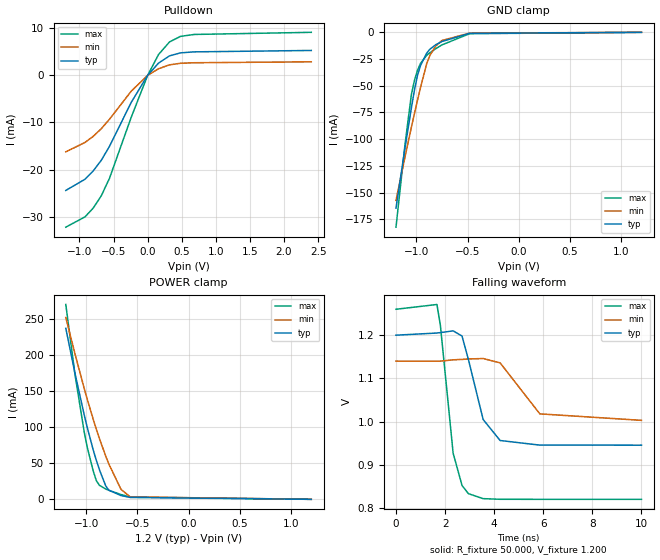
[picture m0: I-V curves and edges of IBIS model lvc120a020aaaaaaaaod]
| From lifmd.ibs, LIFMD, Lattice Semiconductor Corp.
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|   Model lvc120a020aaaaaaaaod
[Model] lvc120a020aaaaaaaaod
Model_type I/O_open_drain
Polarity   Non-Inverting
Enable   Active-Low
Vinl =  0.420V
Vinh =  0.780V
Vmeas =  0.600V
Cref =  0.0F
Rref =  10.000k
Vref =  1.20V
C_comp   5.000pF   4.000pF   5.500pF
[Temperature Range]   25.000   0.125k   -40.000
[Voltage Range]   1.200V   1.140V   1.260V
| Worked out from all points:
|   slope of the pulldown table from 0 to 0.18 V, typ, clamps not added: 63.3 ohm
|   GND clamp passes 1 mA (typ) near -0.48 V on its own axis
|   POWER clamp passes 1 mA (typ) near -0.49 V on its own axis
|   falling waveform, R_fixture 50.000, V_fixture 1.200: 20-80 % time 688ps typ, 991ps min, 500ps max; typ from 1.2 V to 0.946 V
[Pulldown]
|Voltage   I(typ)   I(min)   I(max)
-1.2V     -24.43mA   -16.24mA   -32.23mA
-920mV    -22.07mA   -14.25mA   -30.06mA
-800mV    -20.33mA   -12.97mA   -28.22mA
-680mV    -18.04mA   -11.33mA   -25.58mA
-560mV    -15.08mA   -9.331mA   -21.88mA
-240mV    -5.719mA   -3.347mA   -8.876mA
0V        -2.383fA   10.6fA     -4.549fA
160mV     2.605mA    1.409mA    4.427mA
320mV     4.133mA    2.229mA    7.092mA
480mV     4.774mA    2.565mA    8.275mA
680mV     4.991mA    2.68mA     8.687mA
2.4V      5.291mA    2.878mA    9.14mA
[GND_clamp]
|Voltage   I(typ)   I(min)   I(max)
-1.2V     -164.5mA   -157.3mA   -182.3mA
-1.11V    -107mA     -115.7mA   -103.5mA
-1.05V    -71.11mA   -89.05mA   -58.53mA
-1.02V    -54.23mA   -76.19mA   -45.11mA
-990mV    -40.37mA   -63.68mA   -35.65mA
-960mV    -31.12mA   -51.57mA   -29.01mA
-900mV    -19.51mA   -29.36mA   -21.51mA
-870mV    -15.95mA   -21.89mA   -19.19mA
-810mV    -11.49mA   -12.65mA   -15.26mA
-750mV    -8.556mA   -7.618mA   -11.71mA
-480mV    -930.3uA   -744.4uA   -1.274mA
1.2V      0A         0A         0A
[POWER_clamp]
|Voltage   I(typ)   I(min)   I(max)
-1.2V     237mA      251.9mA    270mA
-1.11V    174.5mA    201.4mA    172.7mA
-1.02V    117mA      153.7mA    93.32mA
-990mV    99.45mA    138.6mA    72.01mA
-930mV    67.46mA    109.9mA    38.25mA
-900mV    53.33mA    96.45mA    25.43mA
-870mV    40.57mA    83.67mA    19.3mA
-810mV    18.72mA    59.99mA    14.34mA
-780mV    12.67mA    49.18mA    12.59mA
-660mV    5.246mA    13.71mA    6.607mA
-570mV    2.605mA    3.346mA    3.25mA
1.2V      0A         0A         0A
[Ramp]
| variable   typ   min   max
dV/dt_r   0.156/0.663n   82.378m/1.038n   0.264/0.449n
dV/dt_f   0.153/0.704n   82.378m/0.991n   0.264/0.501n
R_load = 50.000
[Falling Waveform]
R_fixture= 50.000
V_fixture= 1.200
V_fixture_min= 1.140
V_fixture_max= 1.260
|time   V(typ)   V(min)   V(max)
0s        1.2V       1.14V      1.26V
1.668ns   1.205V     1.14V      1.271V
1.808ns   1.206V     1.14V      1.223V
2.328ns   1.21V      1.143V     927mV
2.69ns    1.198V     1.144V     852.5mV
2.949ns   1.144V     1.145V     833.5mV
3.55ns    1.005V     1.146V     821.9mV
4.242ns   956.4mV    1.136V     820.4mV
5.86ns    945.7mV    1.018V     820.3mV
10ns      945.6mV    1.003V     820.3mV
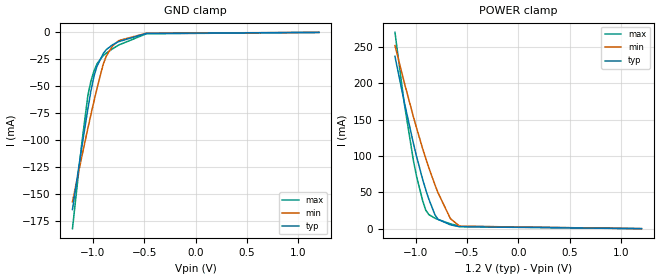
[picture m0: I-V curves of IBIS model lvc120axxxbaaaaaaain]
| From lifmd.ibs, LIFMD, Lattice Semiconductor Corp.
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|   Model lvc120axxxbaaaaaaain
[Model] lvc120axxxbaaaaaaain
Model_type Input
Polarity   Non-Inverting
Vinl =  0.420V
Vinh =  0.780V
C_comp   5.000pF   4.000pF   5.500pF
[Temperature Range]   25.000   0.125k   -40.000
[Voltage Range]   1.200V   1.140V   1.260V
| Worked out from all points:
|   GND clamp passes 1 mA (typ) near -0.48 V on its own axis
|   POWER clamp passes 1 mA (typ) near -0.48 V on its own axis
[GND_clamp]
|Voltage   I(typ)   I(min)   I(max)
-1.2V     -164.5mA   -157.3mA   -182.3mA
-1.11V    -107mA     -115.7mA   -103.5mA
-1.05V    -71.12mA   -89.05mA   -58.53mA
-1.02V    -54.24mA   -76.19mA   -45.12mA
-990mV    -40.38mA   -63.68mA   -35.66mA
-960mV    -31.12mA   -51.57mA   -29.02mA
-900mV    -19.51mA   -29.36mA   -21.52mA
-870mV    -15.95mA   -21.89mA   -19.2mA
-810mV    -11.49mA   -12.65mA   -15.26mA
-750mV    -8.56mA    -7.62mA    -11.71mA
-480mV    -934.9uA   -747.3uA   -1.282mA
1.2V      0A         0A         0A
[POWER_clamp]
|Voltage   I(typ)   I(min)   I(max)
-1.2V     237mA      251.9mA    270mA
-1.11V    174.5mA    201.4mA    172.7mA
-1.02V    117mA      153.7mA    93.33mA
-990mV    99.46mA    138.6mA    72.02mA
-930mV    67.46mA    109.9mA    38.28mA
-900mV    53.34mA    96.46mA    25.46mA
-870mV    40.58mA    83.67mA    19.34mA
-810mV    18.74mA    59.99mA    14.38mA
-780mV    12.68mA    49.19mA    12.62mA
-660mV    5.265mA    13.72mA    6.635mA
-570mV    2.622mA    3.356mA    3.275mA
1.2V      0A         0A         0A
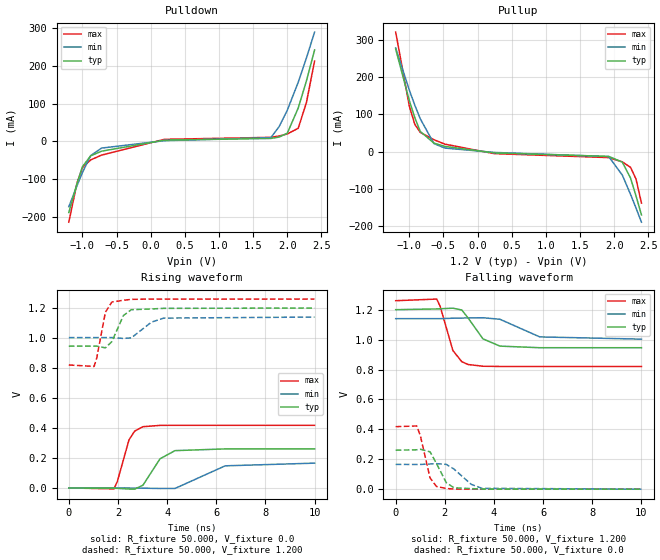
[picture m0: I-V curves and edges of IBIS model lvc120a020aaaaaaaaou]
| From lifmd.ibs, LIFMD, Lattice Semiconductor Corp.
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|   Model lvc120a020aaaaaaaaou
[Model] lvc120a020aaaaaaaaou
Model_type Output
Polarity   Non-Inverting
Vmeas =  0.600V
Cref =  0.0F
Rref =  1.000M
Vref =  0.0V
C_comp   5.000pF   4.000pF   5.500pF
[Temperature Range]   25.000   0.125k   -40.000
[Voltage Range]   1.200V   1.140V   1.260V
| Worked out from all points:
|   slope of the pulldown table from 0 to 0.18 V, typ, clamps not added: 63.3 ohm
|   slope of the pullup table from 0 to 0.18 V, typ, clamps not added: 65.9 ohm
|   rising waveform, R_fixture 50.000, V_fixture 0.0: 20-80 % time 645ps typ, 1.04ns min, 445ps max; typ from 0 V to 0.26 V
|   rising waveform, R_fixture 50.000, V_fixture 1.200: 20-80 % time 413ps typ, 647ps min, 302ps max; typ from 0.946 V to 1.2 V
|   falling waveform, R_fixture 50.000, V_fixture 1.200: 20-80 % time 688ps typ, 991ps min, 500ps max; typ from 1.2 V to 0.946 V
|   falling waveform, R_fixture 50.000, V_fixture 0.0: 20-80 % time 470ps typ, 678ps min, 346ps max; typ from 0.26 V to 0 V
[Pulldown]
|Voltage   I(typ)   I(min)   I(max)
-1.2V     -188.9mA   -173.6mA   -214.6mA
-1.08V    -112.3mA   -117.7mA   -110.6mA
-1V       -67.22mA   -82.71mA   -69.33mA
-880mV    -38.56mA   -37.96mA   -49.45mA
-720mV    -26.17mA   -17.96mA   -36.61mA
200mV     3.083mA    1.667mA    5.25mA
1.76V     7.593mA    9.833mA    10.51mA
1.88V     11.21mA    38.85mA    14.05mA
2V        21.42mA    82.4mA     19.52mA
2.16V     88.15mA    156.5mA    34.54mA
2.28V     159.9mA    220.8mA    102.5mA
2.4V      242.3mA    289.8mA    212.7mA
[Pullup]
|Voltage   I(typ)   I(min)   I(max)
-1.2V     275.5mA    278.5mA    321.2mA
-1V       136.8mA    165.1mA    122mA
-920mV    91.32mA    124.8mA    73.32mA
-840mV    54.36mA    88.32mA    51.77mA
-640mV    22.91mA    21.63mA    32.04mA
-480mV    14.02mA    9.615mA    20.14mA
240mV     -3.395mA   -2.134mA   -5.356mA
1.92V     -12.86mA   -13.28mA   -16.03mA
2.12V     -28.22mA   -63.16mA   -27.54mA
2.24V     -71.02mA   -114.7mA   -42.24mA
2.32V     -118.8mA   -151.5mA   -73.53mA
2.4V      -170.1mA   -189.6mA   -138.1mA
[Ramp]
| variable   typ   min   max
dV/dt_r   0.156/0.663n   99.250m/1.038n   0.251/0.449n
dV/dt_f   0.153/0.704n   82.378m/1.005n   0.264/0.501n
R_load = 50.000
[Rising Waveform]
R_fixture= 50.000
V_fixture= 0.0
V_fixture_min= 0.0
V_fixture_max= 0.0
|time   V(typ)   V(min)   V(max)
0s        0V         0V         0V
1.837ns   -2.233mV   48.45uV    -6.174mV
1.978ns   -2.673mV   133.1uV    44.76mV
2.448ns   -7.473mV   -303.9uV   320.6mV
2.678ns   -8.199mV   -1.148mV   379mV
3.018ns   18.57mV    -1.655mV   408.6mV
3.711ns   194.4mV    -3.758mV   417.3mV
4.321ns   248.9mV    -3.486mV   417.8mV
6.362ns   260.4mV    147.5mV    417.8mV
10ns      260.4mV    165.4mV    417.8mV
[Rising Waveform]
R_fixture= 50.000
V_fixture= 1.200
V_fixture_min= 1.140
V_fixture_max= 1.260
|time   V(typ)   V(min)   V(max)
0s        945.6mV    1.003V     820.3mV
1.028ns   946mV      1.003V     810.6mV
1.137ns   946.3mV    1.003V     867.6mV
1.488ns   934.5mV    1.003V     1.172V
1.751ns   976mV      1.003V     1.24V
2.221ns   1.15V      997.3mV    1.252V
2.541ns   1.189V     1.001V     1.258V
3.362ns   1.194V     1.106V     1.26V
3.862ns   1.198V     1.133V     1.26V
10ns      1.2V       1.14V      1.26V
[Falling Waveform]
R_fixture= 50.000
V_fixture= 1.200
V_fixture_min= 1.140
V_fixture_max= 1.260
|time   V(typ)   V(min)   V(max)
0s        1.2V       1.14V      1.26V
1.668ns   1.205V     1.14V      1.271V
1.808ns   1.206V     1.14V      1.223V
2.328ns   1.21V      1.143V     926.8mV
2.69ns    1.198V     1.144V     852.4mV
2.949ns   1.144V     1.145V     833.4mV
3.55ns    1.005V     1.146V     821.9mV
4.241ns   956.4mV    1.136V     820.4mV
5.86ns    945.7mV    1.018V     820.3mV
10ns      945.6mV    1.003V     820.3mV
[Falling Waveform]
R_fixture= 50.000
V_fixture= 0.0
V_fixture_min= 0.0
V_fixture_max= 0.0
|time   V(typ)   V(min)   V(max)
0s        260.4mV    165.4mV    417.8mV
858ps     263.3mV    165.1mV    422.7mV
1.008ns   266.7mV    165.5mV    354.4mV
1.399ns   249.7mV    168.2mV    75.16mV
1.658ns   172mV      170.6mV    18.11mV
2.061ns   42.79mV    165.4mV    4.147mV
2.37ns    9.655mV    134.8mV    1.251mV
3.071ns   3.631mV    32.44mV    83.11uV
3.51ns    1.247mV    5.804mV    14.76uV
10ns      0V         0V         0V
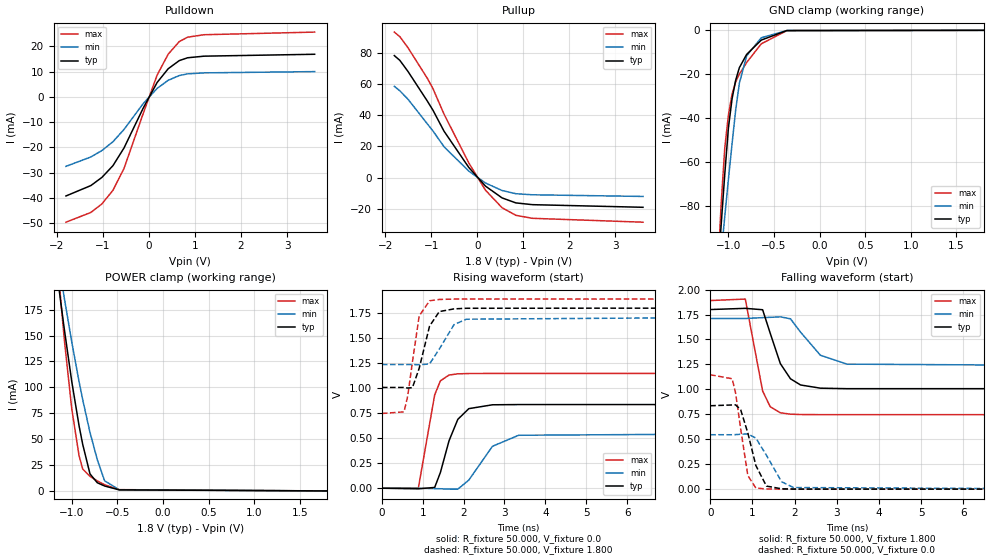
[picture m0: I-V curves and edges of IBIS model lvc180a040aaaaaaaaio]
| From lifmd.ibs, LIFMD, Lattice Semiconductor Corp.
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|   Model lvc180a040aaaaaaaaio
[Model] lvc180a040aaaaaaaaio
Model_type I/O
Polarity   Non-Inverting
Enable   Active-Low
Vinl =  0.630V
Vinh =  1.170V
Vmeas =  0.900V
Cref =  0.0F
Rref =  1.000M
Vref =  0.0V
C_comp   5.000pF   4.000pF   5.500pF
[Temperature Range]   25.000   0.125k   -40.000
[Voltage Range]   1.800V   1.710V   1.890V
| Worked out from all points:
|   slope of the pulldown table from 0 to 0.27 V, typ, clamps not added: 33.9 ohm
|   slope of the pullup table from 0 to 0.27 V, typ, clamps not added: 35.2 ohm
|   GND clamp passes 1 mA (typ) near -0.48 V on its own axis
|   POWER clamp passes 1 mA (typ) near -0.48 V on its own axis
|   rising waveform, R_fixture 50.000, V_fixture 0.0: 20-80 % time 392ps typ, 585ps min, 271ps max; typ from 0 V to 0.836 V
|   rising waveform, R_fixture 50.000, V_fixture 1.800: 20-80 % time 290ps typ, 401ps min, 231ps max; typ from 1.01 V to 1.8 V
|   falling waveform, R_fixture 50.000, V_fixture 1.800: 20-80 % time 412ps typ, 573ps min, 296ps max; typ from 1.8 V to 1.01 V
|   falling waveform, R_fixture 50.000, V_fixture 0.0: 20-80 % time 305ps typ, 420ps min, 231ps max; typ from 0.836 V to 0 V
[Pulldown]
|Voltage   I(typ)   I(min)   I(max)
-1.8V     -39.21mA   -27.5mA    -49.58mA
-1.26V    -35.1mA    -23.79mA   -45.73mA
-1.02V    -31.88mA   -21.25mA   -42.36mA
-780mV    -27.23mA   -17.76mA   -36.96mA
-540mV    -20.24mA   -12.9mA    -28.33mA
-120mV    -4.361mA   -2.624mA   -6.449mA
180mV     5.683mA    3.341mA    8.607mA
420mV     11.11mA    6.532mA    16.87mA
660mV     14.32mA    8.419mA    21.84mA
840mV     15.44mA    9.082mA    23.58mA
1.2V      16.08mA    9.469mA    24.56mA
3.6V      16.83mA    9.972mA    25.6mA
[Pullup]
|Voltage   I(typ)   I(min)   I(max)
-1.8V     78.1mA     58.42mA    93.12mA
-1.68V    75.05mA    55.59mA    90.22mA
-1.5V     67.82mA    50.08mA    83.01mA
-1.08V    48.87mA    34.31mA    63.42mA
-960mV    43.13mA    29.86mA    56.91mA
-720mV    29.72mA    19.78mA    40.63mA
-180mV    6.435mA    4.131mA    9.321mA
180mV     -5.407mA   -3.409mA   -8.023mA
540mV     -12.95mA   -8.221mA   -19.22mA
840mV     -16.14mA   -10.27mA   -24.09mA
1.2V      -17.27mA   -10.95mA   -26mA
3.6V      -18.95mA   -12.01mA   -28.48mA
[GND_clamp]
|Voltage   I(typ)   I(min)   I(max)
-1.8V     -588.7mA   -460.3mA   -776.6mA
-1.12V    -113.2mA   -120.2mA   -111.9mA
-1.08V    -88.74mA   -102.2mA   -79.17mA
-1.04V    -65.4mA    -84.73mA   -53.47mA
-1V       -44.35mA   -67.81mA   -38.46mA
-960mV    -31.12mA   -51.57mA   -29.01mA
-920mV    -22.62mA   -36.09mA   -23.42mA
-880mV    -17mA      -24.08mA   -19.92mA
-800mV    -10.94mA   -11.58mA   -14.64mA
-640mV    -4.44mA    -3.389mA   -6.157mA
-360mV    -108.5uA   -102uA     -131.2uA
1.8V      0A         0A         0A
[POWER_clamp]
|Voltage   I(typ)   I(min)   I(max)
-1.8V     714mA      632.1mA    1.122A
-1.16V    209.1mA    229.4mA    225.8mA
-1.12V    181.6mA    207.1mA    183.6mA
-1.08V    155.1mA    185.3mA    144.6mA
-1V       105.6mA    143.8mA    79.25mA
-920mV    62.93mA    105.5mA    33.98mA
-880mV    44.97mA    88.06mA    21.16mA
-800mV    16.41mA    56.47mA    14.05mA
-720mV    7.909mA    30.12mA    9.679mA
-640mV    4.764mA    9.804mA    6.006mA
-480mV    1.023mA    1.146mA    1.242mA
1.8V      0A         0A         0A
[Ramp]
| variable   typ   min   max
dV/dt_r   0.502/0.398n   0.327/0.588n   0.688/0.275n
dV/dt_f   0.476/0.412n   0.285/0.578n   0.686/0.301n
R_load = 50.000
[Rising Waveform]
R_fixture= 50.000
V_fixture= 0.0
V_fixture_min= 0.0
V_fixture_max= 0.0
|time   V(typ)   V(min)   V(max)
0s        0V         0V         0V
893ps     -5.807mV   279.4uV    2.343mV
1.292ns   7.969mV    -3.757mV   932.5mV
1.432ns   157.5mV    -5.28mV    1.073V
1.643ns   474mV      -9.08mV    1.131V
1.858ns   688.2mV    -9.315mV   1.143V
2.127ns   795.1mV    81.27mV    1.146V
2.706ns   833.7mV    419.2mV    1.147V
3.346ns   835.9mV    529.2mV    1.147V
10ns      835.9mV    545.6mV    1.147V
[Rising Waveform]
R_fixture= 50.000
V_fixture= 1.800
V_fixture_min= 1.710
V_fixture_max= 1.890
|time   V(typ)   V(min)   V(max)
0s        1.007V     1.236V     746.7mV
543ps     1.007V     1.236V     763.1mV
633ps     1.001V     1.236V     922.7mV
748ps     1.005V     1.236V     1.262V
913ps     1.198V     1.233V     1.721V
1.167ns   1.62V      1.242V     1.873V
1.406ns   1.765V     1.391V     1.886V
1.766ns   1.792V     1.635V     1.89V
2.067ns   1.798V     1.689V     1.89V
10ns      1.8V       1.71V      1.89V
[Falling Waveform]
R_fixture= 50.000
V_fixture= 1.800
V_fixture_min= 1.710
V_fixture_max= 1.890
|time   V(typ)   V(min)   V(max)
0s        1.8V       1.71V      1.89V
832ps     1.812V     1.71V      1.905V
1.243ns   1.798V     1.719V     983.2mV
1.423ns   1.562V     1.722V     826.1mV
1.663ns   1.258V     1.727V     765.5mV
1.903ns   1.106V     1.707V     751.6mV
2.143ns   1.044V     1.573V     748mV
2.612ns   1.012V     1.342V     746.8mV
3.242ns   1.007V     1.253V     746.7mV
10ns      1.007V     1.236V     746.7mV
[Falling Waveform]
R_fixture= 50.000
V_fixture= 0.0
V_fixture_min= 0.0
V_fixture_max= 0.0
|time   V(typ)   V(min)   V(max)
0s        835.9mV    545.6mV    1.147V
522ps     843.8mV    545.3mV    1.106V
602ps     844.8mV    546.6mV    964mV
722ps     796.7mV    550.2mV    605.5mV
892ps     563.3mV    553.3mV    136.9mV
1.082ns   237.4mV    512.3mV    11.2mV
1.333ns   30.97mV    339.4mV    1.971mV
1.693ns   3.658mV    74.06mV    196.9uV
1.973ns   1.052mV    16.19mV    32.28uV
10ns      0V         0V         0V
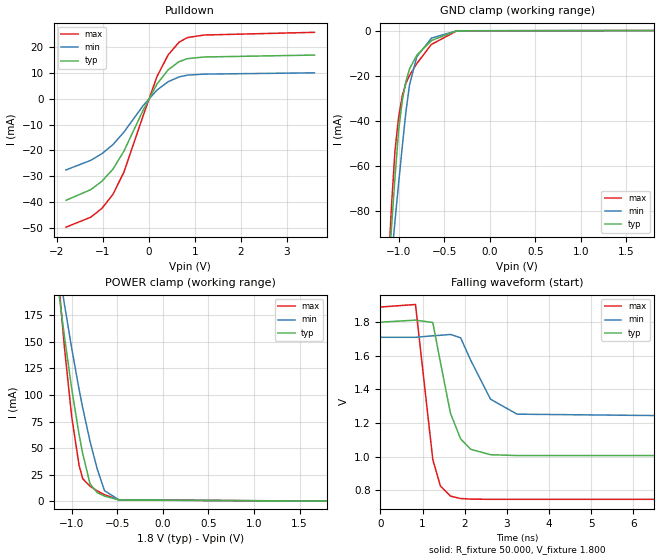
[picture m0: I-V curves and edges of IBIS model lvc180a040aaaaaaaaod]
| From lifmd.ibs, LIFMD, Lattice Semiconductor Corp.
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|   Model lvc180a040aaaaaaaaod
[Model] lvc180a040aaaaaaaaod
Model_type I/O_open_drain
Polarity   Non-Inverting
Enable   Active-Low
Vinl =  0.630V
Vinh =  1.170V
Vmeas =  0.900V
Cref =  0.0F
Rref =  10.000k
Vref =  1.80V
C_comp   5.000pF   4.000pF   5.500pF
[Temperature Range]   25.000   0.125k   -40.000
[Voltage Range]   1.800V   1.710V   1.890V
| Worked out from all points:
|   slope of the pulldown table from 0 to 0.27 V, typ, clamps not added: 33.9 ohm
|   GND clamp passes 1 mA (typ) near -0.48 V on its own axis
|   POWER clamp passes 1 mA (typ) near -0.48 V on its own axis
|   falling waveform, R_fixture 50.000, V_fixture 1.800: 20-80 % time 412ps typ, 573ps min, 296ps max; typ from 1.8 V to 1.01 V
[Pulldown]
|Voltage   I(typ)   I(min)   I(max)
-1.8V     -39.21mA   -27.5mA    -49.58mA
-1.26V    -35.1mA    -23.79mA   -45.73mA
-1.02V    -31.88mA   -21.25mA   -42.36mA
-780mV    -27.23mA   -17.76mA   -36.96mA
-540mV    -20.24mA   -12.9mA    -28.33mA
-120mV    -4.361mA   -2.624mA   -6.449mA
180mV     5.683mA    3.341mA    8.607mA
420mV     11.11mA    6.532mA    16.87mA
660mV     14.32mA    8.419mA    21.84mA
840mV     15.44mA    9.082mA    23.58mA
1.2V      16.08mA    9.469mA    24.56mA
3.6V      16.83mA    9.972mA    25.6mA
[GND_clamp]
|Voltage   I(typ)   I(min)   I(max)
-1.8V     -588.7mA   -460.3mA   -776.6mA
-1.12V    -113.2mA   -120.2mA   -111.9mA
-1.08V    -88.74mA   -102.2mA   -79.17mA
-1.04V    -65.4mA    -84.73mA   -53.47mA
-1V       -44.35mA   -67.81mA   -38.46mA
-960mV    -31.12mA   -51.57mA   -29.01mA
-920mV    -22.62mA   -36.09mA   -23.42mA
-880mV    -17mA      -24.08mA   -19.92mA
-800mV    -10.94mA   -11.58mA   -14.64mA
-640mV    -4.44mA    -3.389mA   -6.157mA
-360mV    -108.5uA   -102uA     -131.2uA
1.8V      0A         0A         0A
[POWER_clamp]
|Voltage   I(typ)   I(min)   I(max)
-1.8V     714mA      632.1mA    1.122A
-1.16V    209.1mA    229.4mA    225.8mA
-1.12V    181.6mA    207.1mA    183.6mA
-1.08V    155.1mA    185.3mA    144.6mA
-1V       105.6mA    143.8mA    79.25mA
-920mV    62.93mA    105.5mA    33.98mA
-880mV    44.97mA    88.06mA    21.16mA
-800mV    16.41mA    56.47mA    14.05mA
-720mV    7.909mA    30.12mA    9.679mA
-640mV    4.764mA    9.804mA    6.006mA
-480mV    1.023mA    1.146mA    1.242mA
1.8V      0A         0A         0A
[Ramp]
| variable   typ   min   max
dV/dt_r   0.476/0.398n   0.285/0.588n   0.688/0.275n
dV/dt_f   0.476/0.412n   0.285/0.578n   0.686/0.301n
R_load = 50.000
[Falling Waveform]
R_fixture= 50.000
V_fixture= 1.800
V_fixture_min= 1.710
V_fixture_max= 1.890
|time   V(typ)   V(min)   V(max)
0s        1.8V       1.71V      1.89V
832ps     1.812V     1.71V      1.905V
1.243ns   1.798V     1.719V     983.2mV
1.423ns   1.562V     1.722V     826.1mV
1.663ns   1.258V     1.727V     765.5mV
1.903ns   1.106V     1.707V     751.6mV
2.143ns   1.044V     1.573V     748mV
2.612ns   1.012V     1.342V     746.8mV
3.242ns   1.007V     1.253V     746.7mV
10ns      1.007V     1.236V     746.7mV
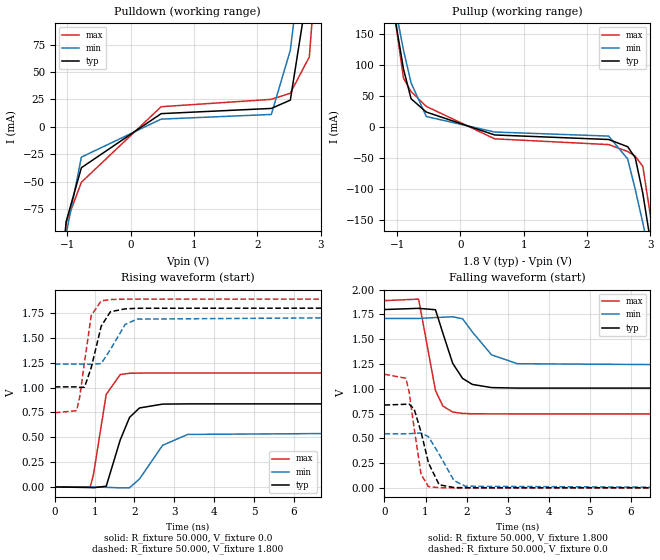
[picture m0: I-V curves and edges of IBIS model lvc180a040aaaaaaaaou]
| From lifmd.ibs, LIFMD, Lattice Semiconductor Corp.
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|   Model lvc180a040aaaaaaaaou
[Model] lvc180a040aaaaaaaaou
Model_type Output
Polarity   Non-Inverting
Vmeas =  0.900V
Cref =  0.0F
Rref =  1.000M
Vref =  0.0V
C_comp   5.000pF   4.000pF   5.500pF
[Temperature Range]   25.000   0.125k   -40.000
[Voltage Range]   1.800V   1.710V   1.890V
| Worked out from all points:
|   slope of the pulldown table from 0 to 0.27 V, typ, clamps not added: 33.9 ohm
|   slope of the pullup table from 0 to 0.27 V, typ, clamps not added: 35.2 ohm
|   rising waveform, R_fixture 50.000, V_fixture 0.0: 20-80 % time 392ps typ, 584ps min, 270ps max; typ from 0 V to 0.836 V
|   rising waveform, R_fixture 50.000, V_fixture 1.800: 20-80 % time 290ps typ, 401ps min, 231ps max; typ from 1.01 V to 1.8 V
|   falling waveform, R_fixture 50.000, V_fixture 1.800: 20-80 % time 412ps typ, 573ps min, 296ps max; typ from 1.8 V to 1.01 V
|   falling waveform, R_fixture 50.000, V_fixture 0.0: 20-80 % time 305ps typ, 420ps min, 231ps max; typ from 0.836 V to 0 V
[Pulldown]
|Voltage   I(typ)   I(min)   I(max)
-1.8V     -627.9mA   -487.8mA   -826.2mA
-1.26V    -239.5mA   -209.8mA   -283.8mA
-1.2V     -198.9mA   -180.5mA   -227.3mA
-1.02V    -86.11mA   -97.45mA   -87.47mA
-780mV    -37.15mA   -27.51mA   -50.4mA
480mV     12.11mA    7.121mA    18.42mA
2.22V     16.85mA    11.38mA    25.12mA
2.52V     24.42mA    69.93mA    30.75mA
2.82V     134mA      211.4mA    63.84mA
3V        254.1mA    314.9mA    198.8mA
3.06V     297.8mA    351.1mA    262.1mA
3.6V      730.9mA    703.4mA    1.007A
[Pullup]
|Voltage   I(typ)   I(min)   I(max)
-1.8V     792.1mA    690.5mA    1.215A
-1.08V    204mA      219.7mA    208.1mA
-900mV    93.44mA    124mA      78.8mA
-780mV    45.47mA    71.17mA    57.09mA
-540mV    24.03mA    16.84mA    33.19mA
540mV     -12.95mA   -8.221mA   -19.22mA
2.34V     -20.28mA   -14.79mA   -28.51mA
2.64V     -31.95mA   -51.63mA   -39.63mA
2.76V     -49.73mA   -100.8mA   -47.2mA
2.88V     -107.4mA   -155.1mA   -63.74mA
3.06V     -223.2mA   -241.8mA   -183.5mA
3.6V      -607.7mA   -519.4mA   -712.9mA
[Ramp]
| variable   typ   min   max
dV/dt_r   0.502/0.398n   0.327/0.588n   0.688/0.278n
dV/dt_f   0.476/0.412n   0.285/0.578n   0.686/0.301n
R_load = 50.000
[Rising Waveform]
R_fixture= 50.000
V_fixture= 0.0
V_fixture_min= 0.0
V_fixture_max= 0.0
|time   V(typ)   V(min)   V(max)
0s        0V         0V         0V
891ps     -5.762mV   273.5uV    956.5uV
971ps     -7.862mV   451.4uV    125.7mV
1.291ns   7.418mV    -3.747mV   931.4mV
1.642ns   472.7mV    -9.061mV   1.131V
1.876ns   700mV      -8.083mV   1.144V
2.126ns   795mV      80.68mV    1.146V
2.706ns   833.7mV    419.2mV    1.147V
3.337ns   835.9mV    528.7mV    1.147V
10ns      835.9mV    545.6mV    1.147V
[Rising Waveform]
R_fixture= 50.000
V_fixture= 1.800
V_fixture_min= 1.710
V_fixture_max= 1.890
|time   V(typ)   V(min)   V(max)
0s        1.007V     1.236V     746.7mV
548ps     1.007V     1.236V     767.7mV
625ps     1.002V     1.236V     902.5mV
746ps     1.004V     1.236V     1.256V
915ps     1.201V     1.233V     1.726V
1.166ns   1.619V     1.242V     1.873V
1.396ns   1.763V     1.383V     1.886V
1.766ns   1.792V     1.635V     1.89V
2.067ns   1.798V     1.689V     1.89V
10ns      1.8V       1.71V      1.89V
[Falling Waveform]
R_fixture= 50.000
V_fixture= 1.800
V_fixture_min= 1.710
V_fixture_max= 1.890
|time   V(typ)   V(min)   V(max)
0s        1.8V       1.71V      1.89V
832ps     1.812V     1.71V      1.905V
1.243ns   1.798V     1.719V     982.7mV
1.423ns   1.562V     1.722V     825.8mV
1.663ns   1.257V     1.727V     765.4mV
1.903ns   1.105V     1.707V     751.4mV
2.143ns   1.044V     1.573V     747.9mV
2.612ns   1.012V     1.342V     746.8mV
3.242ns   1.007V     1.253V     746.7mV
10ns      1.007V     1.236V     746.7mV
[Falling Waveform]
R_fixture= 50.000
V_fixture= 0.0
V_fixture_min= 0.0
V_fixture_max= 0.0
|time   V(typ)   V(min)   V(max)
0s        835.9mV    545.6mV    1.147V
522ps     843.8mV    545.3mV    1.106V
602ps     844.8mV    546.6mV    963.7mV
722ps     796.7mV    550.3mV    604.8mV
892ps     563.1mV    553.3mV    136.3mV
1.073ns   250.9mV    516.2mV    12.12mV
1.333ns   30.95mV    339.4mV    1.97mV
1.693ns   3.657mV    74.05mV    196.5uV
1.973ns   1.052mV    16.18mV    32.23uV
10ns      0V         0V         0V
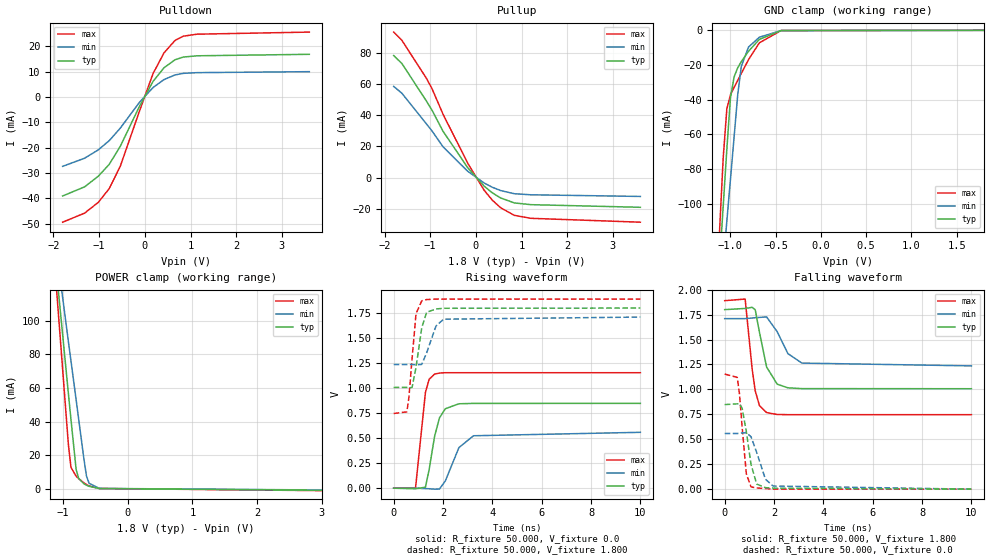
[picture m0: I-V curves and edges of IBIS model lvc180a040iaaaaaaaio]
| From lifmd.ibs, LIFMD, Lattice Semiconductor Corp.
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|   Model lvc180a040iaaaaaaaio
[Model] lvc180a040iaaaaaaaio
Model_type I/O
Polarity   Non-Inverting
Enable   Active-Low
Vinl =  0.630V
Vinh =  1.170V
Vmeas =  0.900V
Cref =  0.0F
Rref =  1.000M
Vref =  0.0V
C_comp   5.000pF   4.000pF   5.500pF
[Temperature Range]   25.000   0.125k   -40.000
[Voltage Range]   1.800V   1.710V   1.890V
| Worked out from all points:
|   slope of the pulldown table from 0 to 0.27 V, typ, clamps not added: 34.2 ohm
|   slope of the pullup table from 0 to 0.27 V, typ, clamps not added: 35.2 ohm
|   GND clamp passes 1 mA (typ) near -0.54 V on its own axis
|   POWER clamp passes 1 mA (typ) near -0.56 V on its own axis
|   rising waveform, R_fixture 50.000, V_fixture 0.0: 20-80 % time 394ps typ, 606ps min, 265ps max; typ from 0 V to 0.848 V
|   rising waveform, R_fixture 50.000, V_fixture 1.800: 20-80 % time 285ps typ, 399ps min, 225ps max; typ from 1.01 V to 1.8 V
|   falling waveform, R_fixture 50.000, V_fixture 1.800: 20-80 % time 419ps typ, 589ps min, 297ps max; typ from 1.8 V to 1.01 V
|   falling waveform, R_fixture 50.000, V_fixture 0.0: 20-80 % time 308ps typ, 433ps min, 231ps max; typ from 0.848 V to 0 V
[Pulldown]
|Voltage   I(typ)   I(min)   I(max)
-1.8V     -39.12mA   -27.42mA   -49.46mA
-1.32V    -35.52mA   -24.22mA   -45.9mA
-1.02V    -31.32mA   -20.92mA   -41.65mA
-780mV    -26.63mA   -17.28mA   -36.21mA
-540mV    -19.59mA   -12.39mA   -27.48mA
-120mV    -3.808mA   -2.191mA   -5.729mA
180mV     6.15mA     3.704mA    9.22mA
420mV     11.5mA     6.838mA    17.4mA
660mV     14.65mA    8.668mA    22.28mA
840mV     15.72mA    9.289mA    23.96mA
1.14V     16.22mA    9.571mA    24.75mA
3.6V      16.81mA    9.957mA    25.58mA
[Pullup]
|Voltage   I(typ)   I(min)   I(max)
-1.8V     78.1mA     58.42mA    93.12mA
-1.62V    73.05mA    53.99mA    87.86mA
-1.08V    48.87mA    34.31mA    63.42mA
-960mV    43.13mA    29.86mA    56.91mA
-720mV    29.72mA    19.78mA    40.63mA
-180mV    6.435mA    4.131mA    9.321mA
180mV     -5.407mA   -3.409mA   -8.023mA
360mV     -9.708mA   -6.144mA   -14.39mA
540mV     -12.95mA   -8.221mA   -19.22mA
840mV     -16.14mA   -10.27mA   -24.09mA
1.2V      -17.27mA   -10.95mA   -26mA
3.6V      -18.95mA   -12.01mA   -28.48mA
[GND_clamp]
|Voltage   I(typ)   I(min)   I(max)
-1.8V     -696.3mA   -577.9mA   -833.3mA
-1.12V    -133.9mA   -158.6mA   -115.3mA
-1.08V    -101.3mA   -134.3mA   -73.45mA
-1.04V    -68.65mA   -110.1mA   -45.28mA
-1V       -38.97mA   -85.9mA    -37.19mA
-960mV    -26.91mA   -61.71mA   -32.92mA
-920mV    -21.64mA   -37.35mA   -28.96mA
-880mV    -18.02mA   -20.78mA   -24.84mA
-800mV    -12.05mA   -9.617mA   -16.87mA
-680mV    -5.205mA   -3.967mA   -7.195mA
-440mV    -125.3uA   -155.5uA   -107.7uA
1.8V      0A         0A         0A
[POWER_clamp]
|Voltage   I(typ)   I(min)   I(max)
-1.8V     417mA      358.2mA    486.8mA
-1.16V    151.7mA    158.7mA    147.8mA
-1.12V    135.7mA    146.8mA    127.3mA
-920mV    56.89mA    87.77mA    26.5mA
-880mV    41.38mA    76.25mA    12.77mA
-800mV    11.56mA    53.05mA    7.539mA
-760mV    6.141mA    41.32mA    6.086mA
-680mV    3.009mA    17.95mA    3.597mA
-640mV    2.17mA     7.684mA    2.581mA
-600mV    1.495mA    3.327mA    1.736mA
-440mV    197.7uA    253.9uA    205.9uA
3.6V      -1.035mA   -849.1uA   -1.289mA
[Ramp]
| variable   typ   min   max
dV/dt_r   0.509/0.398n   0.335/0.606n   0.693/0.270n
dV/dt_f   0.476/0.418n   0.285/0.591n   0.686/0.299n
R_load = 50.000
[Rising Waveform]
R_fixture= 50.000
V_fixture= 0.0
V_fixture_min= 0.0
V_fixture_max= 0.0
|time   V(typ)   V(min)   V(max)
0s        0V         0V         0V
887ps     -5.81mV    301.7uV    3.354mV
1.288ns   10.34mV    -3.84mV    956.6mV
1.437ns   184.5mV    -5.464mV   1.088V
1.658ns   517.2mV    -9.519mV   1.14V
1.856ns   702mV      -8.556mV   1.151V
2.096ns   794.3mV    73.54mV    1.154V
2.646ns   843.7mV    406.2mV    1.154V
3.236ns   847.5mV    524.2mV    1.154V
10ns      847.7mV    558.5mV    1.154V
[Rising Waveform]
R_fixture= 50.000
V_fixture= 1.800
V_fixture_min= 1.710
V_fixture_max= 1.890
|time   V(typ)   V(min)   V(max)
0s        1.007V     1.236V     746.7mV
536ps     1.007V     1.236V     762.6mV
617ps     1.002V     1.236V     904.4mV
748ps     1.008V     1.236V     1.298V
907ps     1.208V     1.233V     1.744V
1.138ns   1.602V     1.237V     1.872V
1.336ns   1.758V     1.352V     1.885V
1.716ns   1.791V     1.621V     1.89V
2.026ns   1.798V     1.689V     1.89V
10ns      1.8V       1.71V      1.89V
[Falling Waveform]
R_fixture= 50.000
V_fixture= 1.800
V_fixture_min= 1.710
V_fixture_max= 1.890
|time   V(typ)   V(min)   V(max)
0s        1.8V       1.71V      1.89V
829ps     1.812V     1.71V      1.906V
1.115ns   1.823V     1.716V     1.2V
1.237ns   1.799V     1.719V     986.2mV
1.408ns   1.574V     1.722V     839.1mV
1.698ns   1.225V     1.727V     767.8mV
2.127ns   1.053V     1.579V     748.8mV
2.561ns   1.016V     1.359V     747mV
3.131ns   1.008V     1.264V     746.7mV
10ns      1.007V     1.236V     746.7mV
[Falling Waveform]
R_fixture= 50.000
V_fixture= 0.0
V_fixture_min= 0.0
V_fixture_max= 0.0
|time   V(typ)   V(min)   V(max)
0s        847.7mV    558.5mV    1.154V
509ps     855.5mV    558.3mV    1.121V
598ps     856.3mV    559.8mV    958.1mV
707ps     812.2mV    563.3mV    624.6mV
877ps     576.8mV    566.6mV    153.6mV
1.067ns   248.3mV    525.6mV    22.68mV
1.297ns   51.01mV    368mV      11.95mV
1.651ns   14.96mV    99.99mV    6.54mV
1.961ns   10.47mV    31.38mV    886.6uV
10ns      0V         0V         0V
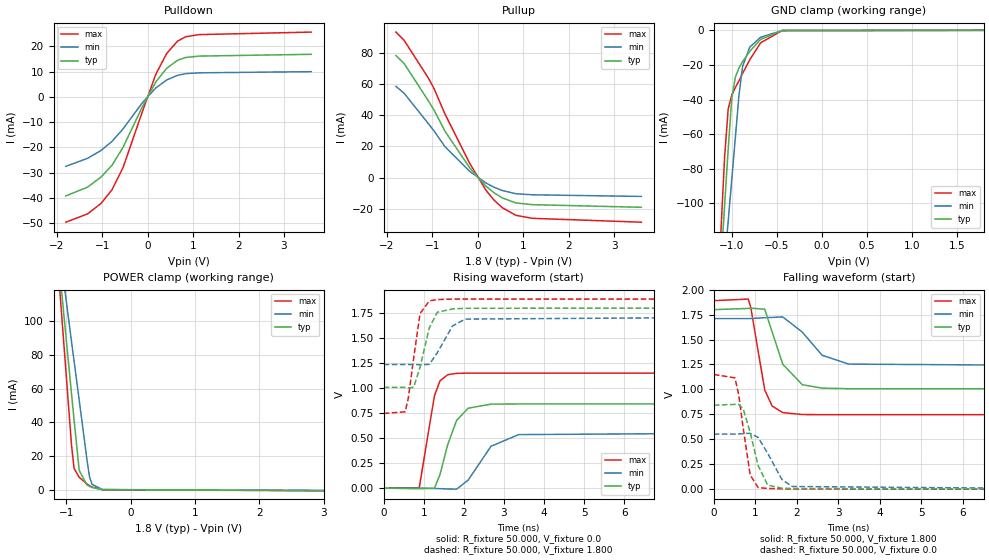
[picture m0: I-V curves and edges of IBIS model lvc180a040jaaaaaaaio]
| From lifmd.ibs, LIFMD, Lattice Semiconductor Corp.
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|   Model lvc180a040jaaaaaaaio
[Model] lvc180a040jaaaaaaaio
Model_type I/O
Polarity   Non-Inverting
Enable   Active-Low
Vinl =  0.630V
Vinh =  1.170V
Vmeas =  0.900V
Cref =  0.0F
Rref =  1.000M
Vref =  0.0V
C_comp   5.000pF   4.000pF   5.500pF
[Temperature Range]   25.000   0.125k   -40.000
[Voltage Range]   1.800V   1.710V   1.890V
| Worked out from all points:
|   slope of the pulldown table from 0 to 0.27 V, typ, clamps not added: 34 ohm
|   slope of the pullup table from 0 to 0.27 V, typ, clamps not added: 35.2 ohm
|   GND clamp passes 1 mA (typ) near -0.54 V on its own axis
|   POWER clamp passes 1 mA (typ) near -0.57 V on its own axis
|   rising waveform, R_fixture 50.000, V_fixture 0.0: 20-80 % time 388ps typ, 591ps min, 263ps max; typ from 0 V to 0.842 V
|   rising waveform, R_fixture 50.000, V_fixture 1.800: 20-80 % time 285ps typ, 399ps min, 225ps max; typ from 1.01 V to 1.8 V
|   falling waveform, R_fixture 50.000, V_fixture 1.800: 20-80 % time 414ps typ, 582ps min, 293ps max; typ from 1.8 V to 1.01 V
|   falling waveform, R_fixture 50.000, V_fixture 0.0: 20-80 % time 302ps typ, 422ps min, 228ps max; typ from 0.842 V to 0 V
[Pulldown]
|Voltage   I(typ)   I(min)   I(max)
-1.8V     -39.16mA   -27.46mA   -49.52mA
-1.32V    -35.66mA   -24.28mA   -46.23mA
-1.02V    -31.61mA   -21.12mA   -42.01mA
-780mV    -26.94mA   -17.53mA   -36.6mA
-540mV    -19.92mA   -12.65mA   -27.92mA
-120mV    -4.086mA   -2.409mA   -6.091mA
180mV     5.915mA    3.521mA    8.911mA
420mV     11.3mA     6.684mA    17.14mA
660mV     14.48mA    8.542mA    22.06mA
840mV     15.58mA    9.185mA    23.77mA
1.14V     16.12mA    9.503mA    24.61mA
3.6V      16.82mA    9.969mA    25.6mA
[Pullup]
|Voltage   I(typ)   I(min)   I(max)
-1.8V     78.1mA     58.42mA    93.12mA
-1.62V    73.05mA    53.99mA    87.86mA
-1.08V    48.87mA    34.31mA    63.42mA
-960mV    43.13mA    29.86mA    56.91mA
-720mV    29.72mA    19.78mA    40.63mA
-180mV    6.435mA    4.131mA    9.321mA
180mV     -5.407mA   -3.409mA   -8.023mA
360mV     -9.708mA   -6.144mA   -14.39mA
540mV     -12.95mA   -8.221mA   -19.22mA
840mV     -16.14mA   -10.27mA   -24.09mA
1.2V      -17.27mA   -10.95mA   -26mA
3.6V      -18.95mA   -12.01mA   -28.48mA
[GND_clamp]
|Voltage   I(typ)   I(min)   I(max)
-1.8V     -696.8mA   -578.3mA   -833.9mA
-1.12V    -134.1mA   -158.8mA   -115.5mA
-1.08V    -101.4mA   -134.5mA   -73.62mA
-1.04V    -68.77mA   -110.2mA   -45.44mA
-1V       -39.08mA   -86.02mA   -37.35mA
-960mV    -27.01mA   -61.81mA   -33.06mA
-920mV    -21.74mA   -37.43mA   -29.09mA
-880mV    -18.1mA    -20.85mA   -24.96mA
-800mV    -12.12mA   -9.665mA   -16.97mA
-680mV    -5.239mA   -3.993mA   -7.242mA
-440mV    -125.9uA   -156.3uA   -108.1uA
1.8V      0A         0A         0A
[POWER_clamp]
|Voltage   I(typ)   I(min)   I(max)
-1.8V     417mA      358.2mA    486.8mA
-1.16V    151.7mA    158.7mA    147.8mA
-1.12V    135.7mA    146.8mA    127.3mA
-1.08V    119.8mA    134.8mA    106.9mA
-920mV    56.85mA    87.76mA    26.37mA
-880mV    41.32mA    76.23mA    12.64mA
-800mV    11.47mA    53.02mA    7.417mA
-680mV    2.92mA     17.91mA    3.486mA
-640mV    2.084mA    7.63mA     2.474mA
-600mV    1.414mA    3.267mA    1.634mA
-440mV    134uA      201.9uA    126.5uA
3.6V      -514.2uA   -421.9uA   -640.6uA
[Ramp]
| variable   typ   min   max
dV/dt_r   0.505/0.392n   0.331/0.593n   0.690/0.265n
dV/dt_f   0.476/0.411n   0.285/0.581n   0.686/0.293n
R_load = 50.000
[Rising Waveform]
R_fixture= 50.000
V_fixture= 0.0
V_fixture_min= 0.0
V_fixture_max= 0.0
|time   V(typ)   V(min)   V(max)
0s        0V         0V         0V
887ps     -5.81mV    301.7uV    3.354mV
1.267ns   -307uV     -3.625mV   924.6mV
1.406ns   138.3mV    -5.068mV   1.073V
1.598ns   435.7mV    -8.414mV   1.134V
1.818ns   676mV      -10.3mV    1.147V
2.108ns   799mV      80.86mV    1.15V
2.678ns   839.7mV    418.6mV    1.15V
3.366ns   841.7mV    535.1mV    1.15V
10ns      841.8mV    552mV      1.15V
[Rising Waveform]
R_fixture= 50.000
V_fixture= 1.800
V_fixture_min= 1.710
V_fixture_max= 1.890
|time   V(typ)   V(min)   V(max)
0s        1.007V     1.236V     746.7mV
536ps     1.007V     1.236V     762.6mV
617ps     1.002V     1.236V     904.4mV
748ps     1.008V     1.236V     1.298V
907ps     1.208V     1.233V     1.744V
1.138ns   1.602V     1.237V     1.872V
1.338ns   1.758V     1.353V     1.885V
1.716ns   1.791V     1.621V     1.89V
2.036ns   1.798V     1.69V      1.89V
10ns      1.8V       1.71V      1.89V
[Falling Waveform]
R_fixture= 50.000
V_fixture= 1.800
V_fixture_min= 1.710
V_fixture_max= 1.890
|time   V(typ)   V(min)   V(max)
0s        1.8V       1.71V      1.89V
829ps     1.812V     1.71V      1.906V
890ps     1.814V     1.711V     1.824V
1.227ns   1.805V     1.719V     994.3mV
1.407ns   1.575V     1.722V     832.9mV
1.662ns   1.252V     1.727V     767.7mV
2.133ns   1.047V     1.574V     748.3mV
2.611ns   1.013V     1.342V     746.9mV
3.251ns   1.007V     1.254V     746.7mV
10ns      1.007V     1.236V     746.7mV
[Falling Waveform]
R_fixture= 50.000
V_fixture= 0.0
V_fixture_min= 0.0
V_fixture_max= 0.0
|time   V(typ)   V(min)   V(max)
0s        841.8mV    552mV      1.15V
509ps     849.7mV    551.8mV    1.116V
598ps     850.5mV    553.3mV    952.4mV
707ps     806.2mV    556.8mV    616.6mV
877ps     569.7mV    560.1mV    142.1mV
1.067ns   238.8mV    519.1mV    16.45mV
1.297ns   41.25mV    360.8mV    7.101mV
1.642ns   9.73mV     95.98mV    3.258mV
1.891ns   6.249mV    26.81mV    713.8uV
10ns      0V         0V         0V
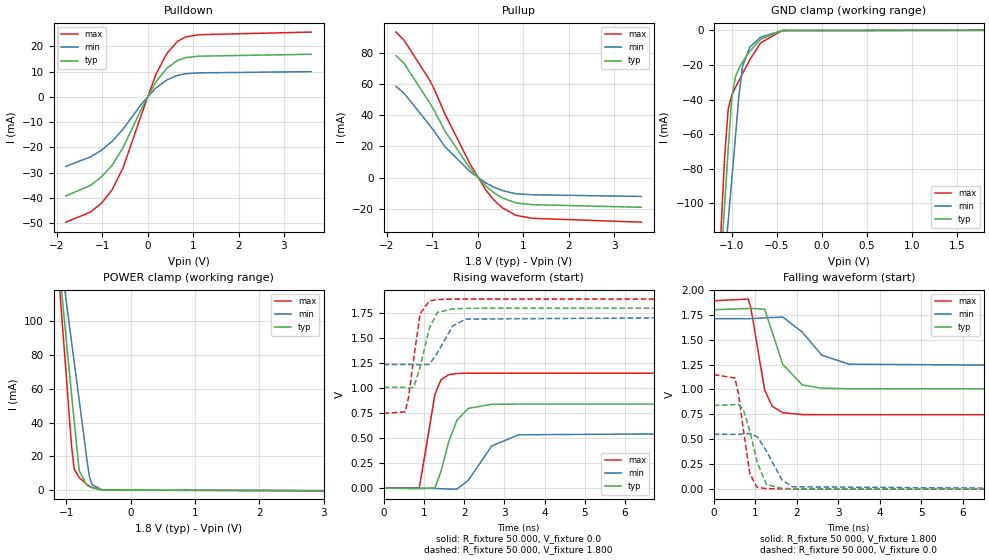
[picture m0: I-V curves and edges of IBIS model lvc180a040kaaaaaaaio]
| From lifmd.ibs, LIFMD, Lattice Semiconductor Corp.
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|   Model lvc180a040kaaaaaaaio
[Model] lvc180a040kaaaaaaaio
Model_type I/O
Polarity   Non-Inverting
Enable   Active-Low
Vinl =  0.630V
Vinh =  1.170V
Vmeas =  0.900V
Cref =  0.0F
Rref =  1.000M
Vref =  0.0V
C_comp   5.000pF   4.000pF   5.500pF
[Temperature Range]   25.000   0.125k   -40.000
[Voltage Range]   1.800V   1.710V   1.890V
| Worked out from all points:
|   slope of the pulldown table from 0 to 0.27 V, typ, clamps not added: 34 ohm
|   slope of the pullup table from 0 to 0.27 V, typ, clamps not added: 35.2 ohm
|   GND clamp passes 1 mA (typ) near -0.54 V on its own axis
|   POWER clamp passes 1 mA (typ) near -0.57 V on its own axis
|   rising waveform, R_fixture 50.000, V_fixture 0.0: 20-80 % time 387ps typ, 586ps min, 263ps max; typ from 0 V to 0.84 V
|   rising waveform, R_fixture 50.000, V_fixture 1.800: 20-80 % time 285ps typ, 399ps min, 225ps max; typ from 1.01 V to 1.8 V
|   falling waveform, R_fixture 50.000, V_fixture 1.800: 20-80 % time 412ps typ, 580ps min, 292ps max; typ from 1.8 V to 1.01 V
|   falling waveform, R_fixture 50.000, V_fixture 0.0: 20-80 % time 300ps typ, 419ps min, 227ps max; typ from 0.84 V to 0 V
[Pulldown]
|Voltage   I(typ)   I(min)   I(max)
-1.8V     -39.18mA   -27.47mA   -49.54mA
-1.26V    -35.03mA   -23.76mA   -45.57mA
-1.02V    -31.7mA    -21.17mA   -42.12mA
-780mV    -27.03mA   -17.6mA    -36.72mA
-540mV    -20.03mA   -12.73mA   -28.05mA
-120mV    -4.173mA   -2.476mA   -6.206mA
180mV     5.841mA    3.465mA    8.814mA
420mV     11.24mA    6.637mA    17.05mA
660mV     14.43mA    8.504mA    21.99mA
840mV     15.54mA    9.153mA    23.71mA
1.14V     16.09mA    9.482mA    24.57mA
3.6V      16.83mA    9.971mA    25.6mA
[Pullup]
|Voltage   I(typ)   I(min)   I(max)
-1.8V     78.1mA     58.42mA    93.12mA
-1.62V    73.05mA    53.99mA    87.86mA
-1.08V    48.87mA    34.31mA    63.42mA
-960mV    43.13mA    29.86mA    56.91mA
-720mV    29.72mA    19.78mA    40.63mA
-180mV    6.435mA    4.131mA    9.321mA
180mV     -5.407mA   -3.409mA   -8.023mA
360mV     -9.708mA   -6.144mA   -14.39mA
540mV     -12.95mA   -8.221mA   -19.22mA
840mV     -16.14mA   -10.27mA   -24.09mA
1.2V      -17.27mA   -10.95mA   -26mA
3.6V      -18.95mA   -12.01mA   -28.48mA
[GND_clamp]
|Voltage   I(typ)   I(min)   I(max)
-1.8V     -697mA     -578.4mA   -834.1mA
-1.12V    -134.1mA   -158.9mA   -115.6mA
-1.08V    -101.4mA   -134.6mA   -73.68mA
-1.04V    -68.81mA   -110.3mA   -45.5mA
-1V       -39.12mA   -86.06mA   -37.4mA
-960mV    -27.05mA   -61.84mA   -33.11mA
-920mV    -21.77mA   -37.46mA   -29.14mA
-880mV    -18.14mA   -20.87mA   -25.01mA
-800mV    -12.15mA   -9.683mA   -17.01mA
-680mV    -5.255mA   -4.004mA   -7.264mA
-440mV    -126.4uA   -157uA     -108.5uA
1.8V      0A         0A         0A
[POWER_clamp]
|Voltage   I(typ)   I(min)   I(max)
-1.8V     417mA      358.2mA    486.8mA
-1.16V    151.7mA    158.7mA    147.8mA
-1.12V    135.7mA    146.8mA    127.3mA
-1.08V    119.8mA    134.8mA    106.9mA
-920mV    56.84mA    87.75mA    26.36mA
-880mV    41.31mA    76.23mA    12.62mA
-800mV    11.46mA    53.02mA    7.396mA
-680mV    2.899mA    17.9mA     3.46mA
-640mV    2.062mA    7.617mA    2.446mA
-600mV    1.391mA    3.253mA    1.605mA
-440mV    114.2uA    186.3uA    101.5uA
3.6V      -351.3uA   -290.5uA   -436uA
[Ramp]
| variable   typ   min   max
dV/dt_r   0.504/0.391n   0.330/0.588n   0.690/0.264n
dV/dt_f   0.476/0.410n   0.285/0.579n   0.686/0.292n
R_load = 50.000
[Rising Waveform]
R_fixture= 50.000
V_fixture= 0.0
V_fixture_min= 0.0
V_fixture_max= 0.0
|time   V(typ)   V(min)   V(max)
0s        0V         0V         0V
887ps     -5.81mV    301.7uV    3.354mV
1.276ns   3.868mV    -3.718mV   938.4mV
1.425ns   166.4mV    -5.305mV   1.083V
1.622ns   469.6mV    -8.876mV   1.135V
1.822ns   678.9mV    -10.18mV   1.146V
2.106ns   797.8mV    79.62mV    1.149V
2.686ns   837.9mV    421.6mV    1.149V
3.356ns   839.9mV    533.5mV    1.149V
10ns      839.9mV    550mV      1.149V
[Rising Waveform]
R_fixture= 50.000
V_fixture= 1.800
V_fixture_min= 1.710
V_fixture_max= 1.890
|time   V(typ)   V(min)   V(max)
0s        1.007V     1.236V     746.7mV
536ps     1.007V     1.236V     762.6mV
617ps     1.002V     1.236V     904.4mV
748ps     1.008V     1.236V     1.298V
907ps     1.208V     1.233V     1.744V
1.138ns   1.602V     1.237V     1.872V
1.338ns   1.758V     1.353V     1.885V
1.716ns   1.791V     1.621V     1.89V
2.036ns   1.798V     1.69V      1.89V
10ns      1.8V       1.71V      1.89V
[Falling Waveform]
R_fixture= 50.000
V_fixture= 1.800
V_fixture_min= 1.710
V_fixture_max= 1.890
|time   V(typ)   V(min)   V(max)
0s        1.8V       1.71V      1.89V
829ps     1.812V     1.71V      1.907V
890ps     1.814V     1.711V     1.824V
1.227ns   1.805V     1.719V     992.9mV
1.407ns   1.575V     1.722V     831mV
1.661ns   1.252V     1.727V     767.1mV
2.131ns   1.046V     1.576V     748.3mV
2.602ns   1.013V     1.344V     746.9mV
3.251ns   1.007V     1.254V     746.7mV
10ns      1.007V     1.236V     746.7mV
[Falling Waveform]
R_fixture= 50.000
V_fixture= 0.0
V_fixture_min= 0.0
V_fixture_max= 0.0
|time   V(typ)   V(min)   V(max)
0s        839.9mV    550mV      1.149V
509ps     847.8mV    549.7mV    1.115V
598ps     848.7mV    551.3mV    950.7mV
707ps     804.3mV    554.8mV    614.3mV
870ps     579.9mV    558.3mV    152.7mV
1.047ns   267mV      525.5mV    16.77mV
1.267ns   47.5mV     383.5mV    6.11mV
1.642ns   8.016mV    93.28mV    2.678mV
1.891ns   4.77mV     24.06mV    676.6uV
10ns      0V         0V         0V
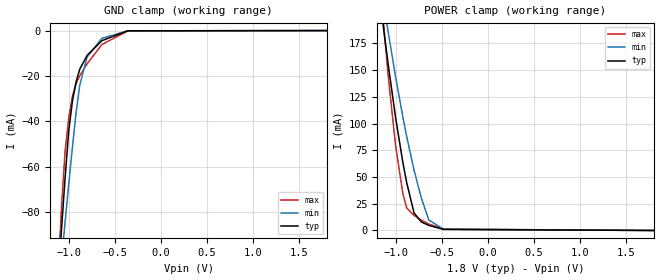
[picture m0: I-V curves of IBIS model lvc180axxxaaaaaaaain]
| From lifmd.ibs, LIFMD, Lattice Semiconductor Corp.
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|   Model lvc180axxxaaaaaaaain
[Model] lvc180axxxaaaaaaaain
Model_type Input
Polarity   Non-Inverting
Vinl =  0.630V
Vinh =  1.170V
C_comp   5.000pF   4.000pF   5.500pF
[Temperature Range]   25.000   0.125k   -40.000
[Voltage Range]   1.800V   1.710V   1.890V
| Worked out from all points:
|   GND clamp passes 1 mA (typ) near -0.48 V on its own axis
|   POWER clamp passes 1 mA (typ) near -0.48 V on its own axis
[GND_clamp]
|Voltage   I(typ)   I(min)   I(max)
-1.8V     -588.7mA   -460.3mA   -776.6mA
-1.12V    -113.2mA   -120.2mA   -111.9mA
-1.08V    -88.74mA   -102.2mA   -79.17mA
-1.04V    -65.4mA    -84.73mA   -53.47mA
-1V       -44.35mA   -67.81mA   -38.46mA
-960mV    -31.12mA   -51.57mA   -29.01mA
-920mV    -22.62mA   -36.09mA   -23.42mA
-880mV    -17mA      -24.08mA   -19.92mA
-800mV    -10.94mA   -11.58mA   -14.64mA
-640mV    -4.44mA    -3.389mA   -6.157mA
-360mV    -108.5uA   -102uA     -131.2uA
1.8V      0A         0A         0A
[POWER_clamp]
|Voltage   I(typ)   I(min)   I(max)
-1.8V     714mA      632.1mA    1.122A
-1.16V    209.1mA    229.4mA    225.8mA
-1.12V    181.6mA    207.1mA    183.6mA
-1.08V    155.1mA    185.3mA    144.6mA
-1V       105.6mA    143.8mA    79.25mA
-920mV    62.93mA    105.5mA    33.98mA
-880mV    44.97mA    88.06mA    21.16mA
-800mV    16.41mA    56.47mA    14.05mA
-720mV    7.909mA    30.12mA    9.679mA
-640mV    4.764mA    9.804mA    6.006mA
-480mV    1.023mA    1.146mA    1.242mA
1.8V      0A         0A         0A
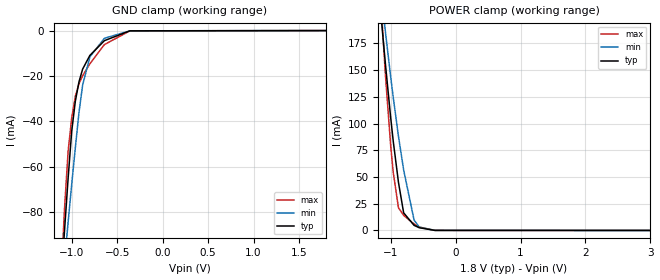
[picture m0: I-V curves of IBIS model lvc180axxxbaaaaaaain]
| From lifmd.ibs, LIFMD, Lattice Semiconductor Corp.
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|   Model lvc180axxxbaaaaaaain
[Model] lvc180axxxbaaaaaaain
Model_type Input
Polarity   Non-Inverting
Vinl =  0.630V
Vinh =  1.170V
C_comp   5.000pF   4.000pF   5.500pF
[Temperature Range]   25.000   0.125k   -40.000
[Voltage Range]   1.800V   1.710V   1.890V
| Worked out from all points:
|   GND clamp passes 1 mA (typ) near -0.48 V on its own axis
|   POWER clamp passes 1 mA (typ) near -0.48 V on its own axis
[GND_clamp]
|Voltage   I(typ)   I(min)   I(max)
-1.8V     -588.7mA   -460.2mA   -776.6mA
-1.12V    -113.2mA   -120.2mA   -111.9mA
-1.08V    -88.73mA   -102.2mA   -79.16mA
-1.04V    -65.39mA   -84.72mA   -53.46mA
-1V       -44.34mA   -67.8mA    -38.45mA
-960mV    -31.11mA   -51.56mA   -29mA
-920mV    -22.61mA   -36.09mA   -23.41mA
-880mV    -17mA      -24.08mA   -19.91mA
-800mV    -10.93mA   -11.58mA   -14.64mA
-640mV    -4.438mA   -3.387mA   -6.152mA
-360mV    -108.4uA   -101.9uA   -131.1uA
1.8V      0A         0A         0A
[POWER_clamp]
|Voltage   I(typ)   I(min)   I(max)
-1.8V     714.1mA    632.1mA    1.122A
-1.16V    209.1mA    229.4mA    225.8mA
-1.12V    181.6mA    207.1mA    183.6mA
-1.08V    155.1mA    185.3mA    144.6mA
-1V       105.6mA    143.8mA    79.28mA
-960mV    83.25mA    124.2mA    54.12mA
-880mV    44.99mA    88.06mA    21.21mA
-800mV    16.44mA    56.48mA    14.1mA
-640mV    4.792mA    9.816mA    6.046mA
-560mV    2.546mA    3.061mA    3.181mA
-320mV    52.57uA    91.81uA    52.14uA
3.6V      -18.59uA   -11.5uA    -29.6uA
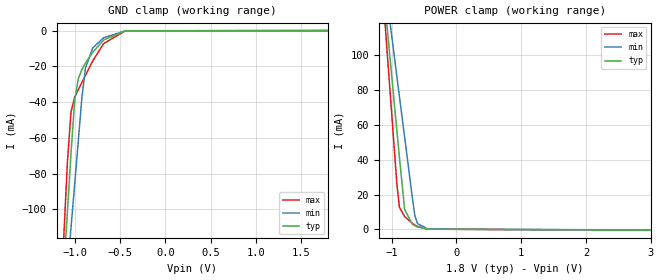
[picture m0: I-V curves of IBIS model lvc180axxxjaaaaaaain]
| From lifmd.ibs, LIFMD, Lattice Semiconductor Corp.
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|   Model lvc180axxxjaaaaaaain
[Model] lvc180axxxjaaaaaaain
Model_type Input
Polarity   Non-Inverting
Vinl =  0.630V
Vinh =  1.170V
C_comp   5.000pF   4.000pF   5.500pF
[Temperature Range]   25.000   0.125k   -40.000
[Voltage Range]   1.800V   1.710V   1.890V
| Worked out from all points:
|   GND clamp passes 1 mA (typ) near -0.54 V on its own axis
|   POWER clamp passes 1 mA (typ) near -0.57 V on its own axis
[GND_clamp]
|Voltage   I(typ)   I(min)   I(max)
-1.8V     -696.8mA   -578.3mA   -833.9mA
-1.12V    -134.1mA   -158.8mA   -115.5mA
-1.08V    -101.4mA   -134.5mA   -73.62mA
-1.04V    -68.77mA   -110.2mA   -45.44mA
-1V       -39.08mA   -86.02mA   -37.35mA
-960mV    -27.01mA   -61.81mA   -33.06mA
-920mV    -21.74mA   -37.43mA   -29.09mA
-880mV    -18.1mA    -20.85mA   -24.96mA
-800mV    -12.12mA   -9.665mA   -16.97mA
-680mV    -5.239mA   -3.993mA   -7.242mA
-440mV    -125.9uA   -156.3uA   -108.1uA
1.8V      0A         0A         0A
[POWER_clamp]
|Voltage   I(typ)   I(min)   I(max)
-1.8V     417mA      358.2mA    486.8mA
-1.16V    151.7mA    158.7mA    147.8mA
-1.12V    135.7mA    146.8mA    127.3mA
-1.08V    119.8mA    134.8mA    106.9mA
-920mV    56.85mA    87.76mA    26.37mA
-880mV    41.32mA    76.23mA    12.64mA
-800mV    11.47mA    53.02mA    7.417mA
-680mV    2.92mA     17.91mA    3.486mA
-640mV    2.084mA    7.63mA     2.474mA
-600mV    1.414mA    3.267mA    1.634mA
-440mV    134uA      201.9uA    126.5uA
3.6V      -514.2uA   -421.9uA   -640.6uA
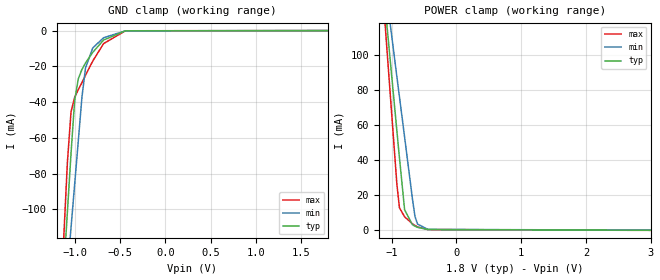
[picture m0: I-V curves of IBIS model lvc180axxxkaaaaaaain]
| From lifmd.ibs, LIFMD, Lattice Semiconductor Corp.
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|   Model lvc180axxxkaaaaaaain
[Model] lvc180axxxkaaaaaaain
Model_type Input
Polarity   Non-Inverting
Vinl =  0.630V
Vinh =  1.170V
C_comp   5.000pF   4.000pF   5.500pF
[Temperature Range]   25.000   0.125k   -40.000
[Voltage Range]   1.800V   1.710V   1.890V
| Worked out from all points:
|   GND clamp passes 1 mA (typ) near -0.54 V on its own axis
|   POWER clamp passes 1 mA (typ) near -0.57 V on its own axis
[GND_clamp]
|Voltage   I(typ)   I(min)   I(max)
-1.8V     -697mA     -578.4mA   -834.1mA
-1.12V    -134.1mA   -158.9mA   -115.6mA
-1.08V    -101.4mA   -134.6mA   -73.68mA
-1.04V    -68.81mA   -110.3mA   -45.5mA
-1V       -39.12mA   -86.06mA   -37.4mA
-960mV    -27.05mA   -61.84mA   -33.11mA
-920mV    -21.77mA   -37.46mA   -29.14mA
-880mV    -18.14mA   -20.87mA   -25.01mA
-800mV    -12.15mA   -9.683mA   -17.01mA
-680mV    -5.255mA   -4.004mA   -7.264mA
-440mV    -126.4uA   -157uA     -108.5uA
1.8V      0A         0A         0A
[POWER_clamp]
|Voltage   I(typ)   I(min)   I(max)
-1.8V     417mA      358.2mA    486.8mA
-1.16V    151.7mA    158.7mA    147.8mA
-1.12V    135.7mA    146.8mA    127.3mA
-1.08V    119.8mA    134.8mA    106.9mA
-920mV    56.84mA    87.75mA    26.36mA
-880mV    41.31mA    76.23mA    12.62mA
-800mV    11.46mA    53.02mA    7.396mA
-680mV    2.899mA    17.9mA     3.46mA
-640mV    2.062mA    7.617mA    2.446mA
-600mV    1.391mA    3.253mA    1.605mA
-440mV    114.2uA    186.3uA    101.5uA
3.6V      -351.3uA   -290.5uA   -436uA
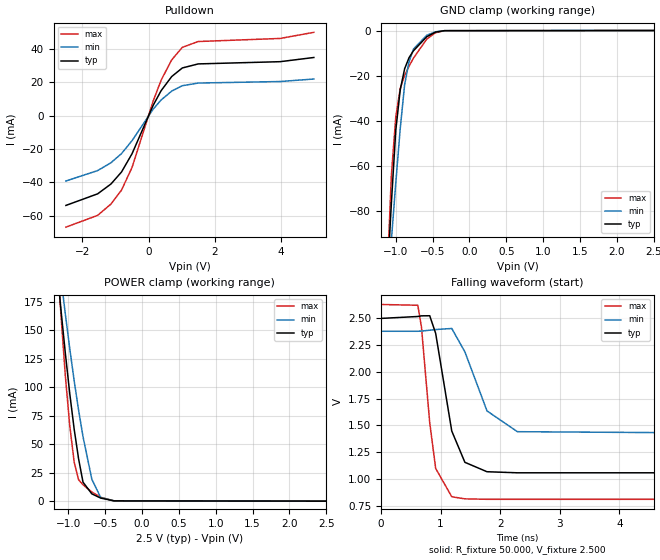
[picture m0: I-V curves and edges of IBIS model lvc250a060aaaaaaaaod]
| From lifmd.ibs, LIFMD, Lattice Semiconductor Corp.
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|   Model lvc250a060aaaaaaaaod
[Model] lvc250a060aaaaaaaaod
Model_type I/O_open_drain
Polarity   Non-Inverting
Enable   Active-Low
Vinl =  0.700V
Vinh =  1.700V
Vmeas =  1.250V
Cref =  0.0F
Rref =  10.000k
Vref =  2.50V
C_comp   5.000pF   4.000pF   5.500pF
[Temperature Range]   25.000   0.125k   -40.000
[Voltage Range]   2.500V   2.380V   2.630V
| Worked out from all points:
|   slope of the pulldown table from 0 to 0.375 V, typ, clamps not added: 25.5 ohm
|   GND clamp passes 1 mA (typ) near -0.48 V on its own axis
|   POWER clamp passes 1 mA (typ) near -0.47 V on its own axis
|   falling waveform, R_fixture 50.000, V_fixture 2.500: 20-80 % time 282ps typ, 406ps min, 192ps max; typ from 2.5 V to 1.06 V
[Pulldown]
|Voltage   I(typ)   I(min)   I(max)
-2.5V     -53.73mA   -39.13mA   -66.73mA
-1.54V    -46.8mA    -32.9mA    -59.68mA
-1.14V    -40.97mA   -28.24mA   -52.95mA
-820mV    -33.79mA   -22.77mA   -44.63mA
-500mV    -22.83mA   -15.02mA   -31.03mA
140mV     6.15mA     3.852mA    8.723mA
380mV     14.88mA    9.328mA    21.16mA
700mV     23.33mA    14.63mA    33.3mA
1.02V     28.45mA    17.84mA    40.76mA
1.5V      30.88mA    19.43mA    44.27mA
3.98V     32.22mA    20.35mA    46.11mA
5V        34.72mA    21.86mA    49.77mA
[GND_clamp]
|Voltage   I(typ)   I(min)   I(max)
-2.5V     -1.11A     -830.4mA   -1.508A
-1.12V    -113.2mA   -120.2mA   -111.9mA
-1.06V    -76.91mA   -93.41mA   -64.42mA
-1V       -44.35mA   -67.81mA   -38.46mA
-940mV    -26.44mA   -43.73mA   -25.84mA
-880mV    -17mA      -24.08mA   -19.92mA
-820mV    -12.07mA   -13.83mA   -15.88mA
-760mV    -8.998mA   -8.257mA   -12.27mA
-580mV    -2.762mA   -2.111mA   -3.825mA
-460mV    -702.7uA   -570.8uA   -955.8uA
-340mV    -67.3uA    -66.5uA    -79.08uA
2.5V      0A         0A         0A
[POWER_clamp]
|Voltage   I(typ)   I(min)   I(max)
-2.5V     1.335A     1.134A     2.299A
-1.16V    209.6mA    229.7mA    226.6mA
-1.1V     168.7mA    196.5mA    164.4mA
-1.04V    130.1mA    164.5mA    110.3mA
-980mV    94.59mA    134.1mA    66.45mA
-920mV    63.27mA    105.8mA    34.35mA
-860mV    37.18mA    79.96mA    18.78mA
-800mV    16.66mA    56.66mA    14.36mA
-680mV    6.381mA    19.15mA    8.023mA
-560mV    2.685mA    3.173mA    3.362mA
-380mV    223.7uA    310.4uA    250.2uA
2.5V      0A         0A         0A
[Ramp]
| variable   typ   min   max
dV/dt_r   0.865/0.261n   0.580/0.413n   1.106/0.185n
dV/dt_f   0.865/0.289n   0.580/0.412n   1.092/0.198n
R_load = 50.000
[Falling Waveform]
R_fixture= 50.000
V_fixture= 2.500
V_fixture_min= 2.380
V_fixture_max= 2.630
|time   V(typ)   V(min)   V(max)
0s        2.5V       2.38V      2.63V
617ps     2.518V     2.38V      2.623V
678ps     2.524V     2.382V     2.421V
817ps     2.525V     2.39V      1.526V
917ps     2.36V      2.396V     1.099V
1.187ns   1.448V     2.406V     834.2mV
1.407ns   1.156V     2.188V     814.7mV
1.778ns   1.068V     1.636V     810.5mV
2.288ns   1.058V     1.442V     810.2mV
10ns      1.058V     1.414V     810.2mV
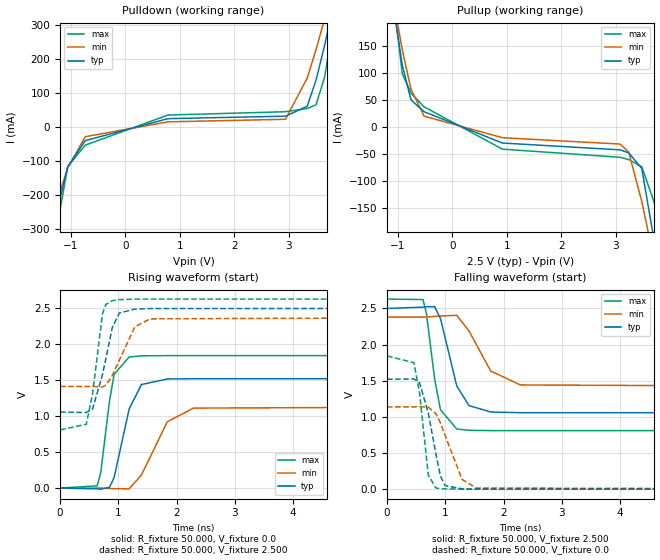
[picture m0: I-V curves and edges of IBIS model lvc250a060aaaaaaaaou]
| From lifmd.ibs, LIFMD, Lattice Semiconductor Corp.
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|   Model lvc250a060aaaaaaaaou
[Model] lvc250a060aaaaaaaaou
Model_type Output
Polarity   Non-Inverting
Vmeas =  1.250V
Cref =  0.0F
Rref =  1.000M
Vref =  0.0V
C_comp   5.000pF   4.000pF   5.500pF
[Temperature Range]   25.000   0.125k   -40.000
[Voltage Range]   2.500V   2.380V   2.630V
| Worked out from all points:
|   slope of the pulldown table from 0 to 0.375 V, typ, clamps not added: 25.5 ohm
|   slope of the pullup table from 0 to 0.375 V, typ, clamps not added: 25 ohm
|   rising waveform, R_fixture 50.000, V_fixture 0.0: 20-80 % time 257ps typ, 407ps min, 176ps max; typ from 0 V to 1.52 V
|   rising waveform, R_fixture 50.000, V_fixture 2.500: 20-80 % time 230ps typ, 319ps min, 166ps max; typ from 1.06 V to 2.5 V
|   falling waveform, R_fixture 50.000, V_fixture 2.500: 20-80 % time 282ps typ, 406ps min, 192ps max; typ from 2.5 V to 1.06 V
|   falling waveform, R_fixture 50.000, V_fixture 0.0: 20-80 % time 215ps typ, 310ps min, 147ps max; typ from 1.52 V to 0 V
[Pulldown]
|Voltage   I(typ)   I(min)   I(max)
-2.5V     -1.164A    -869.5mA   -1.575A
-1.46V    -388.7mA   -317.1mA   -491.1mA
-1.3V     -275.2mA   -235.7mA   -332.1mA
-1.06V    -116.4mA   -120.5mA   -115.7mA
-740mV    -39.66mA   -28.14mA   -53.12mA
780mV     24.92mA    15.62mA    35.6mA
2.94V     32.34mA    23.17mA    45.38mA
3.34V     61.42mA    144.5mA    54.97mA
3.5V      137.9mA    227.6mA    65.57mA
3.66V     241.6mA    319.6mA    147.9mA
3.82V     358.7mA    417.6mA    306mA
5V        1.369A     1.246A     2.12A
[Pullup]
|Voltage   I(typ)   I(min)   I(max)
-2.5V     1.42A      1.209A     2.387A
-1.16V    274.2mA    277.5mA    305.2mA
-920mV    114.7mA    143mA      98.81mA
-760mV    50.41mA    70.49mA    62.9mA
-520mV    28.57mA    20.35mA    37.57mA
920mV     -29.37mA   -19.52mA   -40.68mA
3.08V     -41.99mA   -31.27mA   -55.7mA
3.24V     -47.5mA    -46.08mA   -59.99mA
3.48V     -76.48mA   -137.4mA   -73.16mA
3.72V     -217.4mA   -251.4mA   -142.7mA
3.88V     -326.6mA   -331.7mA   -284.4mA
5V        -1.151A    -921.3mA   -1.428A
[Ramp]
| variable   typ   min   max
dV/dt_r   0.913/0.261n   0.682/0.412n   1.106/0.180n
dV/dt_f   0.865/0.289n   0.580/0.412n   1.092/0.198n
R_load = 50.000
[Rising Waveform]
R_fixture= 50.000
V_fixture= 0.0
V_fixture_min= 0.0
V_fixture_max= 0.0
|time   V(typ)   V(min)   V(max)
0s        0V         0V         0V
638ps     -10.9mV    640.9uV    31.66mV
698ps     -14.93mV   -44.11uV   221mV
848ps     10.75mV    -6.126mV   1.21V
928ps     148.8mV    -8.64mV    1.583V
1.186ns   1.101V     -10.49mV   1.824V
1.397ns   1.441V     181.1mV    1.84V
1.842ns   1.518V     923.5mV    1.843V
2.292ns   1.521V     1.113V     1.843V
10ns      1.521V     1.137V     1.843V
[Rising Waveform]
R_fixture= 50.000
V_fixture= 2.500
V_fixture_min= 2.380
V_fixture_max= 2.630
|time   V(typ)   V(min)   V(max)
0s        1.058V     1.414V     810.2mV
449ps     1.052V     1.414V     888.1mV
557ps     1.1V       1.414V     1.309V
728ps     1.581V     1.407V     2.426V
787ps     1.805V     1.433V     2.556V
896ps     2.232V     1.565V     2.608V
1.017ns   2.437V     1.778V     2.622V
1.282ns   2.49V      2.242V     2.629V
1.546ns   2.498V     2.355V     2.63V
10ns      2.5V       2.38V      2.63V
[Falling Waveform]
R_fixture= 50.000
V_fixture= 2.500
V_fixture_min= 2.380
V_fixture_max= 2.630
|time   V(typ)   V(min)   V(max)
0s        2.5V       2.38V      2.63V
617ps     2.518V     2.38V      2.623V
677ps     2.524V     2.382V     2.426V
817ps     2.525V     2.39V      1.524V
917ps     2.36V      2.396V     1.098V
1.197ns   1.426V     2.405V     832.1mV
1.407ns   1.156V     2.188V     814.6mV
1.778ns   1.068V     1.635V     810.5mV
2.288ns   1.058V     1.442V     810.2mV
10ns      1.058V     1.414V     810.2mV
[Falling Waveform]
R_fixture= 50.000
V_fixture= 0.0
V_fixture_min= 0.0
V_fixture_max= 0.0
|time   V(typ)   V(min)   V(max)
0s        1.521V     1.137V     1.843V
461ps     1.525V     1.138V     1.75V
558ps     1.472V     1.142V     1.331V
708ps     1.054V     1.135V     195.3mV
838ps     489.8mV    1.044V     16.16mV
917ps     179.9mV    915.2mV    7.447mV
997ps     49.54mV    741.3mV    3.837mV
1.288ns   4.055mV    134.3mV    356.4uV
1.528ns   933.2uV    15.86mV    50uV
10ns      0V         0V         0V
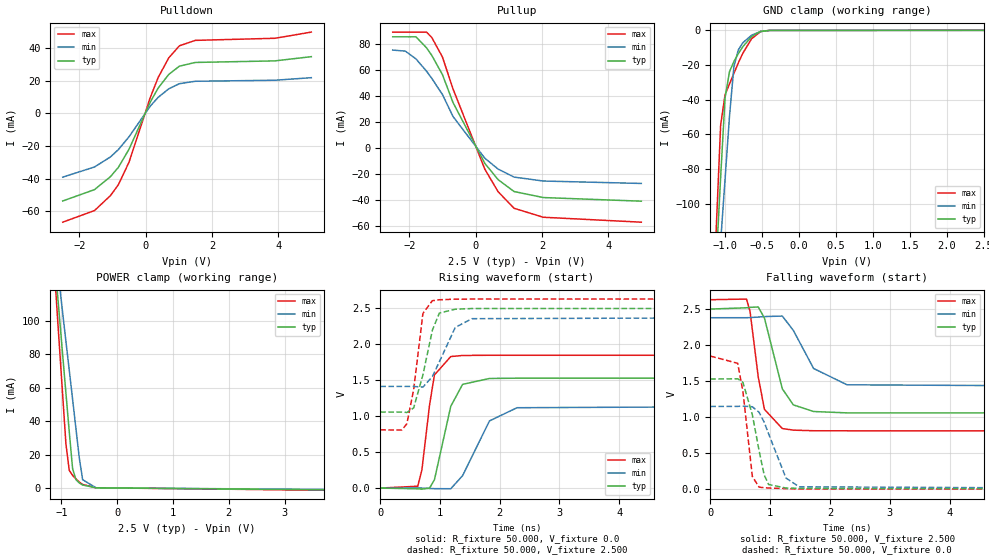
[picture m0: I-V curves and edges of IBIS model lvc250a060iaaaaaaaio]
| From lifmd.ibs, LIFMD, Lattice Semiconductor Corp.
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|   Model lvc250a060iaaaaaaaio
[Model] lvc250a060iaaaaaaaio
Model_type I/O
Polarity   Non-Inverting
Enable   Active-Low
Vinl =  0.700V
Vinh =  1.700V
Vmeas =  1.250V
Cref =  0.0F
Rref =  1.000M
Vref =  0.0V
C_comp   5.000pF   4.000pF   5.500pF
[Temperature Range]   25.000   0.125k   -40.000
[Voltage Range]   2.500V   2.380V   2.630V
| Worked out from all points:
|   slope of the pulldown table from 0 to 0.375 V, typ, clamps not added: 25.6 ohm
|   slope of the pullup table from 0 to 0.375 V, typ, clamps not added: 25 ohm
|   GND clamp passes 1 mA (typ) near -0.54 V on its own axis
|   POWER clamp passes 1 mA (typ) near -0.56 V on its own axis
|   rising waveform, R_fixture 50.000, V_fixture 0.0: 20-80 % time 250ps typ, 405ps min, 168ps max; typ from 0 V to 1.53 V
|   rising waveform, R_fixture 50.000, V_fixture 2.500: 20-80 % time 227ps typ, 316ps min, 162ps max; typ from 1.06 V to 2.5 V
|   falling waveform, R_fixture 50.000, V_fixture 2.500: 20-80 % time 282ps typ, 412ps min, 189ps max; typ from 2.5 V to 1.06 V
|   falling waveform, R_fixture 50.000, V_fixture 0.0: 20-80 % time 215ps typ, 311ps min, 146ps max; typ from 1.53 V to 0 V
[Pulldown]
|Voltage   I(typ)   I(min)   I(max)
-2.5V     -53.62mA   -39.03mA   -66.6mA
-1.54V    -46.66mA   -32.8mA    -59.47mA
-1.06V    -38.73mA   -26.67mA   -50.33mA
-820mV    -33.02mA   -22.14mA   -43.66mA
-500mV    -21.96mA   -14.34mA   -29.91mA
140mV     6.841mA    4.394mA    9.624mA
380mV     15.5mA     9.813mA    21.97mA
700mV     23.86mA    15.03mA    34mA
1.02V     28.89mA    18.17mA    41.35mA
1.5V      31.17mA    19.65mA    44.68mA
3.9V      32.12mA    20.28mA    45.96mA
5V        34.71mA    21.84mA    49.75mA
[Pullup]
|Voltage   I(typ)   I(min)   I(max)
-2.5V     85.63mA    75.44mA    89.24mA
-2.12V    85.63mA    74.62mA    89.24mA
-1.8V     85.63mA    68.69mA    89.24mA
-1.48V    77.18mA    59.23mA    89.24mA
-1.32V    71.31mA    53.67mA    85.06mA
-1V       56.6mA     41.33mA    70.1mA
-680mV    35.1mA     24.39mA    45.54mA
280mV     -11.59mA   -7.633mA   -16.08mA
680mV     -24.05mA   -15.94mA   -33.31mA
1.16V     -33.16mA   -22.09mA   -46.03mA
2.04V     -37.8mA    -25.11mA   -52.92mA
5V        -40.59mA   -26.98mA   -56.72mA
[GND_clamp]
|Voltage   I(typ)   I(min)   I(max)
-2.5V     -1.281A    -1.016A    -1.577A
-1.12V    -133.9mA   -158.5mA   -115.2mA
-1.06V    -84.89mA   -122.1mA   -54.78mA
-1V       -38.92mA   -85.86mA   -37.12mA
-940mV    -23.86mA   -49.53mA   -30.9mA
-880mV    -17.98mA   -20.76mA   -24.78mA
-820mV    -13.41mA   -11.25mA   -18.74mA
-760mV    -9.456mA   -7.171mA   -13.25mA
-640mV    -3.551mA   -2.801mA   -4.802mA
-520mV    -678.8uA   -668.4uA   -731.3uA
-400mV    -43.49uA   -63.53uA   -34.37uA
2.5V      0A         0A         0A
[POWER_clamp]
|Voltage   I(typ)   I(min)   I(max)
-2.5V     738.4mA    604.6mA    887.7mA
-1.16V    151.7mA    158.7mA    147.8mA
-1.1V     127.7mA    140.8mA    117.1mA
-1.04V    104mA      123mA      86.66mA
-920mV    56.89mA    87.78mA    26.5mA
-860mV    33.63mA    70.5mA     10.57mA
-800mV    11.56mA    53.05mA    7.541mA
-740mV    4.955mA    35.46mA    5.413mA
-680mV    3.011mA    17.96mA    3.599mA
-620mV    1.817mA    4.988mA    2.138mA
-380mV    123.7uA    130.4uA    143.8uA
5V        -1.458mA   -1.208mA   -1.806mA
[Ramp]
| variable   typ   min   max
dV/dt_r   0.917/0.256n   0.689/0.411n   1.109/0.176n
dV/dt_f   0.865/0.282n   0.580/0.415n   1.092/0.190n
R_load = 50.000
[Rising Waveform]
R_fixture= 50.000
V_fixture= 0.0
V_fixture_min= 0.0
V_fixture_max= 0.0
|time   V(typ)   V(min)   V(max)
0s        0V         0V         0V
627ps     -10.69mV   661.6uV    25.39mV
697ps     -15.34mV   -337.7uV   254.1mV
826ps     345.2uV    -5.802mV   1.163V
907ps     116.6mV    -8.334mV   1.575V
1.18ns    1.138V     -9.365mV   1.83V
1.378ns   1.443V     172.9mV    1.845V
1.828ns   1.525V     934.5mV    1.848V
2.289ns   1.529V     1.118V     1.848V
10ns      1.529V     1.148V     1.848V
[Rising Waveform]
R_fixture= 50.000
V_fixture= 2.500
V_fixture_min= 2.380
V_fixture_max= 2.630
|time   V(typ)   V(min)   V(max)
0s        1.058V     1.414V     810.2mV
361ps     1.058V     1.414V     807.4mV
446ps     1.052V     1.414V     897.1mV
559ps     1.116V     1.414V     1.371V
714ps     1.575V     1.405V     2.43V
872ps     2.197V     1.551V     2.607V
989ps     2.435V     1.758V     2.62V
1.255ns   2.489V     2.235V     2.629V
1.535ns   2.498V     2.357V     2.63V
10ns      2.5V       2.38V      2.63V
[Falling Waveform]
R_fixture= 50.000
V_fixture= 2.500
V_fixture_min= 2.380
V_fixture_max= 2.630
|time   V(typ)   V(min)   V(max)
0s        2.5V       2.38V      2.63V
605ps     2.518V     2.38V      2.639V
664ps     2.524V     2.382V     2.471V
801ps     2.529V     2.389V     1.562V
905ps     2.376V     2.396V     1.108V
1.204ns   1.393V     2.403V     841.3mV
1.388ns   1.17V      2.204V     819.5mV
1.727ns   1.078V     1.675V     811mV
2.285ns   1.059V     1.449V     810.2mV
10ns      1.058V     1.414V     810.2mV
[Falling Waveform]
R_fixture= 50.000
V_fixture= 0.0
V_fixture_min= 0.0
V_fixture_max= 0.0
|time   V(typ)   V(min)   V(max)
0s        1.529V     1.148V     1.848V
458ps     1.532V     1.149V     1.747V
546ps     1.482V     1.153V     1.355V
703ps     1.032V     1.144V     176.6mV
815ps     537.8mV    1.068V     28.9mV
900ps     198.8mV    931.6mV    19.25mV
975ps     64.84mV    767.4mV    15.51mV
1.265ns   15.84mV    154.4mV    8.218mV
1.485ns   11.85mV    32.66mV    1.691mV
10ns      0V         0V         0V
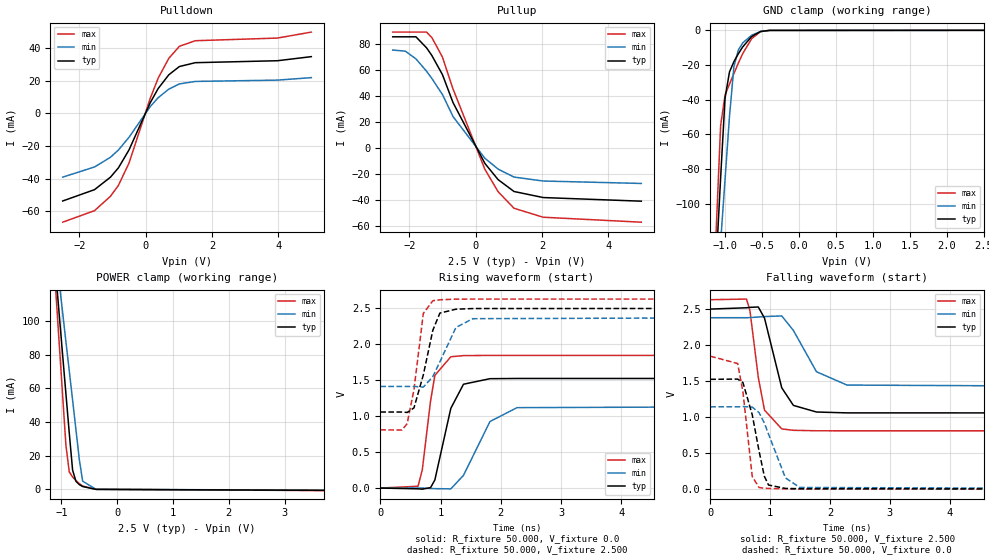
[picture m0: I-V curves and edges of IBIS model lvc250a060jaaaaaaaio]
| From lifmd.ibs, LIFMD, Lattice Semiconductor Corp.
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|   Model lvc250a060jaaaaaaaio
[Model] lvc250a060jaaaaaaaio
Model_type I/O
Polarity   Non-Inverting
Enable   Active-Low
Vinl =  0.700V
Vinh =  1.700V
Vmeas =  1.250V
Cref =  0.0F
Rref =  1.000M
Vref =  0.0V
C_comp   5.000pF   4.000pF   5.500pF
[Temperature Range]   25.000   0.125k   -40.000
[Voltage Range]   2.500V   2.380V   2.630V
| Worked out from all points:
|   slope of the pulldown table from 0 to 0.375 V, typ, clamps not added: 25.5 ohm
|   slope of the pullup table from 0 to 0.375 V, typ, clamps not added: 25 ohm
|   GND clamp passes 1 mA (typ) near -0.54 V on its own axis
|   POWER clamp passes 1 mA (typ) near -0.57 V on its own axis
|   rising waveform, R_fixture 50.000, V_fixture 0.0: 20-80 % time 248ps typ, 402ps min, 167ps max; typ from 0 V to 1.52 V
|   rising waveform, R_fixture 50.000, V_fixture 2.500: 20-80 % time 227ps typ, 316ps min, 162ps max; typ from 1.06 V to 2.5 V
|   falling waveform, R_fixture 50.000, V_fixture 2.500: 20-80 % time 279ps typ, 408ps min, 187ps max; typ from 2.5 V to 1.06 V
|   falling waveform, R_fixture 50.000, V_fixture 0.0: 20-80 % time 213ps typ, 306ps min, 145ps max; typ from 1.52 V to 0 V
[Pulldown]
|Voltage   I(typ)   I(min)   I(max)
-2.5V     -53.68mA   -39.08mA   -66.67mA
-1.54V    -46.74mA   -32.85mA   -59.61mA
-1.06V    -39.11mA   -26.92mA   -50.8mA
-820mV    -33.42mA   -22.47mA   -44.18mA
-500mV    -22.4mA    -14.68mA   -30.48mA
140mV     6.493mA    4.121mA    9.171mA
380mV     15.19mA    9.569mA    21.56mA
700mV     23.59mA    14.83mA    33.65mA
1.02V     28.67mA    18.01mA    41.05mA
1.5V      31.02mA    19.54mA    44.47mA
3.98V     32.22mA    20.34mA    46.1mA
5V        34.72mA    21.86mA    49.76mA
[Pullup]
|Voltage   I(typ)   I(min)   I(max)
-2.5V     85.63mA    75.44mA    89.24mA
-2.12V    85.63mA    74.62mA    89.24mA
-1.8V     85.63mA    68.69mA    89.24mA
-1.48V    77.18mA    59.23mA    89.24mA
-1.32V    71.31mA    53.67mA    85.06mA
-1V       56.6mA     41.33mA    70.1mA
-680mV    35.1mA     24.39mA    45.54mA
280mV     -11.59mA   -7.633mA   -16.08mA
680mV     -24.05mA   -15.94mA   -33.31mA
1.16V     -33.16mA   -22.09mA   -46.03mA
2.04V     -37.8mA    -25.11mA   -52.92mA
5V        -40.59mA   -26.98mA   -56.72mA
[GND_clamp]
|Voltage   I(typ)   I(min)   I(max)
-2.5V     -1.282A    -1.016A    -1.578A
-1.12V    -134mA     -158.8mA   -115.5mA
-1.06V    -85.04mA   -122.3mA   -54.99mA
-1V       -39.05mA   -85.98mA   -37.31mA
-940mV    -23.98mA   -49.62mA   -31.06mA
-880mV    -18.08mA   -20.83mA   -24.93mA
-820mV    -13.49mA   -11.31mA   -18.86mA
-760mV    -9.517mA   -7.215mA   -13.34mA
-640mV    -3.571mA   -2.819mA   -4.823mA
-520mV    -681uA     -671.2uA   -733uA
-400mV    -43.61uA   -63.74uA   -34.47uA
2.5V      0A         0A         0A
[POWER_clamp]
|Voltage   I(typ)   I(min)   I(max)
-2.5V     738.3mA    604.5mA    887.7mA
-1.16V    151.7mA    158.7mA    147.8mA
-1.1V     127.7mA    140.8mA    117.1mA
-1.04V    103.9mA    123mA      86.61mA
-920mV    56.85mA    87.76mA    26.37mA
-860mV    33.56mA    70.48mA    10.45mA
-800mV    11.47mA    53.03mA    7.418mA
-740mV    4.861mA    35.42mA    5.295mA
-680mV    2.921mA    17.91mA    3.487mA
-620mV    1.732mA    4.929mA    2.033mA
-380mV    67.64uA    84.1uA     74.35uA
5V        -725.6uA   -600.6uA   -898.8uA
[Ramp]
| variable   typ   min   max
dV/dt_r   0.915/0.252n   0.686/0.405n   1.107/0.174n
dV/dt_f   0.865/0.278n   0.580/0.407n   1.092/0.188n
R_load = 50.000
[Rising Waveform]
R_fixture= 50.000
V_fixture= 0.0
V_fixture_min= 0.0
V_fixture_max= 0.0
|time   V(typ)   V(min)   V(max)
0s        0V         0V         0V
627ps     -10.69mV   661.6uV    25.39mV
697ps     -15.34mV   -337.7uV   254.1mV
834ps     6.134mV    -6.071mV   1.213V
905ps     111.9mV    -8.275mV   1.568V
1.17ns    1.109V     -11.25mV   1.827V
1.38ns    1.445V     176.6mV    1.843V
1.819ns   1.522V     925.5mV    1.846V
2.268ns   1.525V     1.119V     1.846V
10ns      1.525V     1.143V     1.846V
[Rising Waveform]
R_fixture= 50.000
V_fixture= 2.500
V_fixture_min= 2.380
V_fixture_max= 2.630
|time   V(typ)   V(min)   V(max)
0s        1.058V     1.414V     810.2mV
361ps     1.058V     1.414V     807.4mV
446ps     1.052V     1.414V     897.1mV
559ps     1.116V     1.414V     1.371V
714ps     1.575V     1.405V     2.43V
872ps     2.197V     1.551V     2.607V
989ps     2.435V     1.758V     2.62V
1.255ns   2.489V     2.235V     2.629V
1.535ns   2.498V     2.357V     2.63V
10ns      2.5V       2.38V      2.63V
[Falling Waveform]
R_fixture= 50.000
V_fixture= 2.500
V_fixture_min= 2.380
V_fixture_max= 2.630
|time   V(typ)   V(min)   V(max)
0s        2.5V       2.38V      2.63V
605ps     2.518V     2.38V      2.639V
663ps     2.524V     2.382V     2.476V
802ps     2.529V     2.39V      1.552V
906ps     2.374V     2.396V     1.097V
1.194ns   1.407V     2.405V     836.6mV
1.388ns   1.163V     2.204V     817.2mV
1.774ns   1.071V     1.63V      810.6mV
2.284ns   1.059V     1.445V     810.2mV
10ns      1.058V     1.414V     810.2mV
[Falling Waveform]
R_fixture= 50.000
V_fixture= 0.0
V_fixture_min= 0.0
V_fixture_max= 0.0
|time   V(typ)   V(min)   V(max)
0s        1.525V     1.143V     1.846V
458ps     1.528V     1.143V     1.744V
546ps     1.479V     1.147V     1.348V
701ps     1.033V     1.139V     176mV
815ps     527.8mV    1.062V     22.27mV
903ps     179.7mV    919mV      13.05mV
973ps     57.42mV    764.5mV    9.836mV
1.256ns   10.27mV    156mV      4.297mV
1.495ns   6.368mV    23.53mV    822.7uV
10ns      0V         0V         0V
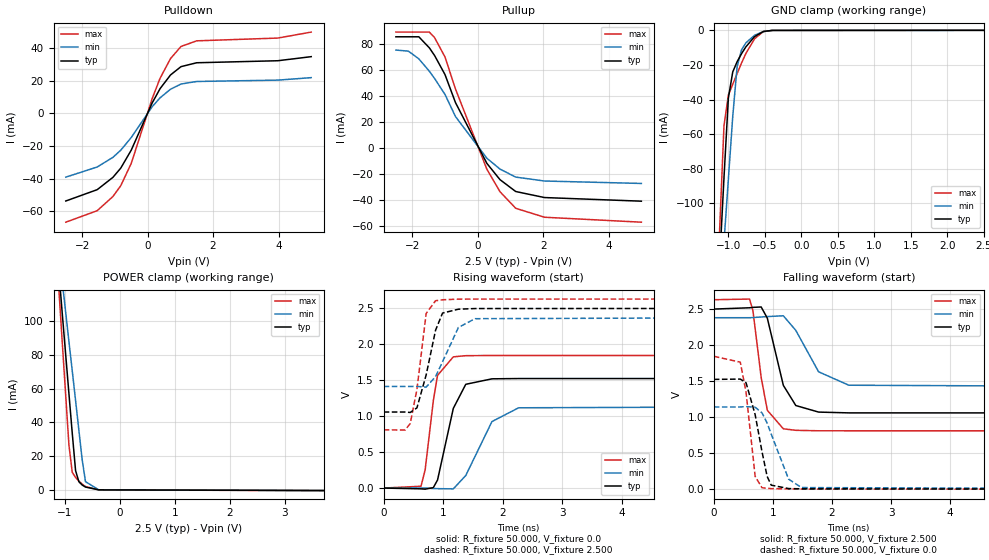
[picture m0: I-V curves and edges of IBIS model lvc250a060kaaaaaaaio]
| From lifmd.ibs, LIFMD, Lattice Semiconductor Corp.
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|   Model lvc250a060kaaaaaaaio
[Model] lvc250a060kaaaaaaaio
Model_type I/O
Polarity   Non-Inverting
Enable   Active-Low
Vinl =  0.700V
Vinh =  1.700V
Vmeas =  1.250V
Cref =  0.0F
Rref =  1.000M
Vref =  0.0V
C_comp   5.000pF   4.000pF   5.500pF
[Temperature Range]   25.000   0.125k   -40.000
[Voltage Range]   2.500V   2.380V   2.630V
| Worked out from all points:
|   slope of the pulldown table from 0 to 0.375 V, typ, clamps not added: 25.5 ohm
|   slope of the pullup table from 0 to 0.375 V, typ, clamps not added: 25 ohm
|   GND clamp passes 1 mA (typ) near -0.54 V on its own axis
|   POWER clamp passes 1 mA (typ) near -0.57 V on its own axis
|   rising waveform, R_fixture 50.000, V_fixture 0.0: 20-80 % time 248ps typ, 400ps min, 167ps max; typ from 0 V to 1.52 V
|   rising waveform, R_fixture 50.000, V_fixture 2.500: 20-80 % time 227ps typ, 316ps min, 162ps max; typ from 1.06 V to 2.5 V
|   falling waveform, R_fixture 50.000, V_fixture 2.500: 20-80 % time 278ps typ, 406ps min, 186ps max; typ from 2.5 V to 1.06 V
|   falling waveform, R_fixture 50.000, V_fixture 0.0: 20-80 % time 212ps typ, 305ps min, 145ps max; typ from 1.52 V to 0 V
[Pulldown]
|Voltage   I(typ)   I(min)   I(max)
-2.5V     -53.7mA    -39.1mA    -66.69mA
-1.54V    -46.76mA   -32.87mA   -59.63mA
-1.06V    -39.22mA   -26.97mA   -50.95mA
-820mV    -33.54mA   -22.57mA   -44.33mA
-500mV    -22.54mA   -14.79mA   -30.66mA
140mV     6.383mA    4.035mA    9.027mA
380mV     15.09mA    9.492mA    21.43mA
700mV     23.51mA    14.76mA    33.54mA
1.02V     28.6mA     17.95mA    40.96mA
1.5V      30.98mA    19.51mA    44.41mA
3.98V     32.22mA    20.34mA    46.11mA
5V        34.72mA    21.86mA    49.77mA
[Pullup]
|Voltage   I(typ)   I(min)   I(max)
-2.5V     85.63mA    75.44mA    89.24mA
-2.12V    85.63mA    74.62mA    89.24mA
-1.8V     85.63mA    68.69mA    89.24mA
-1.48V    77.18mA    59.23mA    89.24mA
-1.32V    71.31mA    53.67mA    85.06mA
-1V       56.6mA     41.33mA    70.1mA
-680mV    35.1mA     24.39mA    45.54mA
280mV     -11.59mA   -7.633mA   -16.08mA
680mV     -24.05mA   -15.94mA   -33.31mA
1.16V     -33.16mA   -22.09mA   -46.03mA
2.04V     -37.8mA    -25.11mA   -52.92mA
5V        -40.59mA   -26.98mA   -56.72mA
[GND_clamp]
|Voltage   I(typ)   I(min)   I(max)
-2.5V     -1.282A    -1.016A    -1.578A
-1.12V    -134.1mA   -158.9mA   -115.5mA
-1.06V    -85.09mA   -122.4mA   -55.06mA
-1V       -39.1mA    -86.04mA   -37.37mA
-940mV    -24.02mA   -49.66mA   -31.12mA
-880mV    -18.12mA   -20.86mA   -24.98mA
-820mV    -13.52mA   -11.33mA   -18.91mA
-760mV    -9.544mA   -7.234mA   -13.38mA
-640mV    -3.584mA   -2.829mA   -4.842mA
-520mV    -683.4uA   -673.7uA   -735.2uA
-400mV    -43.73uA   -63.95uA   -34.55uA
2.5V      0A         0A         0A
[POWER_clamp]
|Voltage   I(typ)   I(min)   I(max)
-2.5V     738.3mA    604.5mA    887.7mA
-1.16V    151.7mA    158.7mA    147.8mA
-1.1V     127.7mA    140.8mA    117.1mA
-1.04V    103.9mA    123mA      86.6mA
-920mV    56.84mA    87.75mA    26.36mA
-860mV    33.55mA    70.48mA    10.43mA
-800mV    11.46mA    53.02mA    7.397mA
-740mV    4.842mA    35.42mA    5.271mA
-680mV    2.899mA    17.9mA     3.46mA
-620mV    1.709mA    4.915mA    2.004mA
-380mV    49.91uA    69.71uA    52.26uA
5V        -493uA     -409.9uA   -609.6uA
[Ramp]
| variable   typ   min   max
dV/dt_r   0.914/0.252n   0.685/0.404n   1.107/0.174n
dV/dt_f   0.865/0.277n   0.580/0.405n   1.092/0.187n
R_load = 50.000
[Rising Waveform]
R_fixture= 50.000
V_fixture= 0.0
V_fixture_min= 0.0
V_fixture_max= 0.0
|time   V(typ)   V(min)   V(max)
0s        0V         0V         0V
627ps     -10.69mV   661.6uV    25.39mV
697ps     -15.34mV   -337.7uV   254.1mV
834ps     6.134mV    -6.071mV   1.213V
905ps     111.9mV    -8.275mV   1.568V
1.17ns    1.109V     -11.25mV   1.826V
1.379ns   1.444V     174.7mV    1.842V
1.819ns   1.52V      925.5mV    1.845V
2.267ns   1.524V     1.117V     1.845V
10ns      1.524V     1.141V     1.845V
[Rising Waveform]
R_fixture= 50.000
V_fixture= 2.500
V_fixture_min= 2.380
V_fixture_max= 2.630
|time   V(typ)   V(min)   V(max)
0s        1.058V     1.414V     810.2mV
361ps     1.058V     1.414V     807.4mV
446ps     1.052V     1.414V     897.1mV
559ps     1.116V     1.414V     1.371V
714ps     1.575V     1.405V     2.43V
872ps     2.197V     1.551V     2.607V
989ps     2.435V     1.758V     2.62V
1.255ns   2.489V     2.235V     2.629V
1.535ns   2.498V     2.357V     2.63V
10ns      2.5V       2.38V      2.63V
[Falling Waveform]
R_fixture= 50.000
V_fixture= 2.500
V_fixture_min= 2.380
V_fixture_max= 2.630
|time   V(typ)   V(min)   V(max)
0s        2.5V       2.38V      2.63V
605ps     2.518V     2.38V      2.639V
663ps     2.524V     2.382V     2.476V
802ps     2.529V     2.39V      1.551V
906ps     2.374V     2.396V     1.095V
1.177ns   1.441V     2.407V     838mV
1.388ns   1.161V     2.204V     816.9mV
1.774ns   1.07V      1.629V     810.6mV
2.284ns   1.059V     1.443V     810.2mV
10ns      1.058V     1.414V     810.2mV
[Falling Waveform]
R_fixture= 50.000
V_fixture= 0.0
V_fixture_min= 0.0
V_fixture_max= 0.0
|time   V(typ)   V(min)   V(max)
0s        1.524V     1.141V     1.845V
449ps     1.528V     1.141V     1.763V
546ps     1.477V     1.146V     1.346V
700ps     1.035V     1.138V     177.8mV
816ps     520.6mV    1.059V     20.08mV
903ps     176.6mV    917mV      11.16mV
972ps     55.67mV    764.5mV    8.066mV
1.266ns   8.154mV    138.6mV    3.362mV
1.485ns   4.84mV     22.1mV     831.7uV
10ns      0V         0V         0V
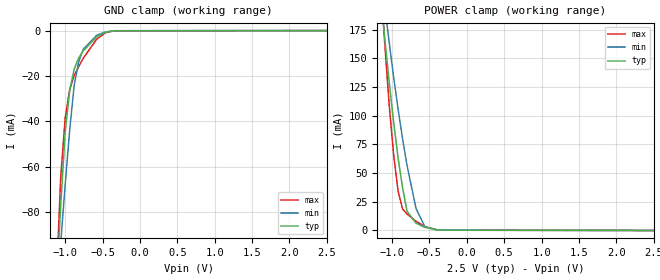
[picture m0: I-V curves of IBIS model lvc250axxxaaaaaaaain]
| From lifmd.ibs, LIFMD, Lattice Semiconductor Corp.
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|   Model lvc250axxxaaaaaaaain
[Model] lvc250axxxaaaaaaaain
Model_type Input
Polarity   Non-Inverting
Vinl =  0.700V
Vinh =  1.700V
C_comp   5.000pF   4.000pF   5.500pF
[Temperature Range]   25.000   0.125k   -40.000
[Voltage Range]   2.500V   2.380V   2.630V
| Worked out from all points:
|   GND clamp passes 1 mA (typ) near -0.48 V on its own axis
|   POWER clamp passes 1 mA (typ) near -0.47 V on its own axis
[GND_clamp]
|Voltage   I(typ)   I(min)   I(max)
-2.5V     -1.11A     -830.4mA   -1.508A
-1.12V    -113.2mA   -120.2mA   -111.9mA
-1.06V    -76.91mA   -93.41mA   -64.42mA
-1V       -44.35mA   -67.81mA   -38.46mA
-940mV    -26.44mA   -43.73mA   -25.84mA
-880mV    -17mA      -24.08mA   -19.92mA
-820mV    -12.07mA   -13.83mA   -15.88mA
-760mV    -8.998mA   -8.257mA   -12.27mA
-580mV    -2.762mA   -2.111mA   -3.825mA
-460mV    -702.7uA   -570.8uA   -955.8uA
-340mV    -67.3uA    -66.5uA    -79.08uA
2.5V      0A         0A         0A
[POWER_clamp]
|Voltage   I(typ)   I(min)   I(max)
-2.5V     1.335A     1.134A     2.299A
-1.16V    209.6mA    229.7mA    226.6mA
-1.1V     168.7mA    196.5mA    164.4mA
-1.04V    130.1mA    164.5mA    110.3mA
-980mV    94.59mA    134.1mA    66.45mA
-920mV    63.27mA    105.8mA    34.35mA
-860mV    37.18mA    79.96mA    18.78mA
-800mV    16.66mA    56.66mA    14.36mA
-680mV    6.381mA    19.15mA    8.023mA
-560mV    2.685mA    3.173mA    3.362mA
-380mV    223.7uA    310.4uA    250.2uA
2.5V      0A         0A         0A
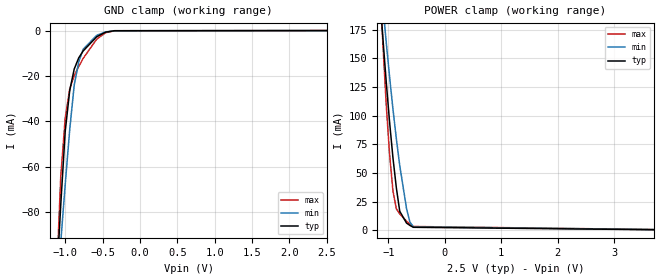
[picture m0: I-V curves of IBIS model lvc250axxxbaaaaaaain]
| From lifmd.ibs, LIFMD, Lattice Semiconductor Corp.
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|   Model lvc250axxxbaaaaaaain
[Model] lvc250axxxbaaaaaaain
Model_type Input
Polarity   Non-Inverting
Vinl =  0.700V
Vinh =  1.700V
C_comp   5.000pF   4.000pF   5.500pF
[Temperature Range]   25.000   0.125k   -40.000
[Voltage Range]   2.500V   2.380V   2.630V
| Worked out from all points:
|   GND clamp passes 1 mA (typ) near -0.48 V on its own axis
|   POWER clamp passes 1 mA (typ) near -0.46 V on its own axis
[GND_clamp]
|Voltage   I(typ)   I(min)   I(max)
-2.5V     -1.11A     -830.4mA   -1.508A
-1.12V    -113.2mA   -120.2mA   -111.9mA
-1.06V    -76.9mA    -93.39mA   -64.4mA
-1V       -44.33mA   -67.79mA   -38.44mA
-940mV    -26.43mA   -43.71mA   -25.82mA
-880mV    -16.99mA   -24.07mA   -19.9mA
-820mV    -12.06mA   -13.82mA   -15.86mA
-760mV    -8.988mA   -8.251mA   -12.26mA
-580mV    -2.757mA   -2.108mA   -3.818mA
-460mV    -701.6uA   -569.5uA   -954.5uA
-340mV    -67.17uA   -66.03uA   -79uA
2.5V      0A         0A         0A
[POWER_clamp]
|Voltage   I(typ)   I(min)   I(max)
-2.5V     1.335A     1.134A     2.299A
-1.16V    209.6mA    229.7mA    226.6mA
-1.1V     168.7mA    196.5mA    164.4mA
-1.04V    130.1mA    164.5mA    110.3mA
-980mV    94.6mA     134.1mA    66.48mA
-920mV    63.28mA    105.8mA    34.41mA
-860mV    37.2mA     79.96mA    18.84mA
-800mV    16.7mA     56.67mA    14.42mA
-680mV    6.419mA    19.17mA    8.074mA
-620mV    4.361mA    7.291mA    5.504mA
-560mV    2.717mA    3.193mA    3.406mA
5V        -43.59uA   -27.74uA   -65.11uA
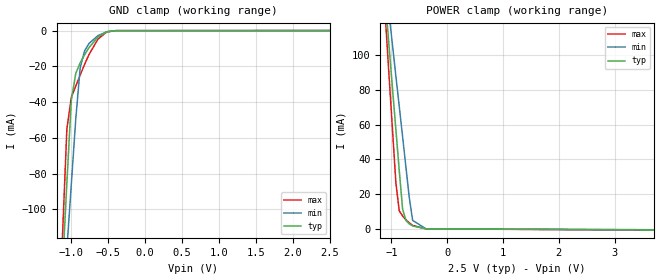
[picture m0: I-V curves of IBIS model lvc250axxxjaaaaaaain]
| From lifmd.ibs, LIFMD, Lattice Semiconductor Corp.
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|   Model lvc250axxxjaaaaaaain
[Model] lvc250axxxjaaaaaaain
Model_type Input
Polarity   Non-Inverting
Vinl =  0.700V
Vinh =  1.700V
C_comp   5.000pF   4.000pF   5.500pF
[Temperature Range]   25.000   0.125k   -40.000
[Voltage Range]   2.500V   2.380V   2.630V
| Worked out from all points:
|   GND clamp passes 1 mA (typ) near -0.54 V on its own axis
|   POWER clamp passes 1 mA (typ) near -0.57 V on its own axis
[GND_clamp]
|Voltage   I(typ)   I(min)   I(max)
-2.5V     -1.282A    -1.016A    -1.578A
-1.12V    -134mA     -158.8mA   -115.5mA
-1.06V    -85.04mA   -122.3mA   -54.99mA
-1V       -39.05mA   -85.98mA   -37.31mA
-940mV    -23.98mA   -49.62mA   -31.06mA
-880mV    -18.08mA   -20.83mA   -24.93mA
-820mV    -13.49mA   -11.31mA   -18.86mA
-760mV    -9.517mA   -7.215mA   -13.34mA
-640mV    -3.571mA   -2.819mA   -4.823mA
-520mV    -681uA     -671.2uA   -733uA
-400mV    -43.61uA   -63.74uA   -34.47uA
2.5V      0A         0A         0A
[POWER_clamp]
|Voltage   I(typ)   I(min)   I(max)
-2.5V     738.3mA    604.5mA    887.7mA
-1.16V    151.7mA    158.7mA    147.8mA
-1.1V     127.7mA    140.8mA    117.1mA
-1.04V    103.9mA    123mA      86.61mA
-920mV    56.85mA    87.76mA    26.37mA
-860mV    33.56mA    70.48mA    10.45mA
-800mV    11.47mA    53.03mA    7.418mA
-740mV    4.861mA    35.42mA    5.295mA
-680mV    2.921mA    17.91mA    3.487mA
-620mV    1.732mA    4.929mA    2.033mA
-380mV    67.64uA    84.1uA     74.35uA
5V        -725.6uA   -600.6uA   -898.8uA
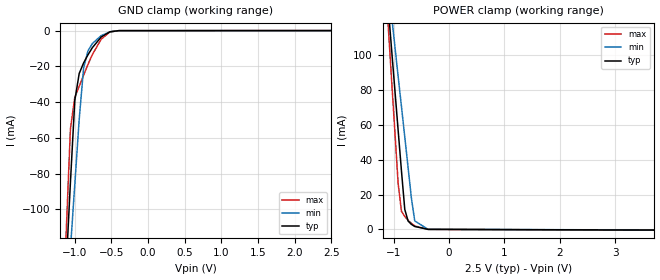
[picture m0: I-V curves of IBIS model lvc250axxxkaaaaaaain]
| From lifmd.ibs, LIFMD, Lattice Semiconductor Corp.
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|   Model lvc250axxxkaaaaaaain
[Model] lvc250axxxkaaaaaaain
Model_type Input
Polarity   Non-Inverting
Vinl =  0.700V
Vinh =  1.700V
C_comp   5.000pF   4.000pF   5.500pF
[Temperature Range]   25.000   0.125k   -40.000
[Voltage Range]   2.500V   2.380V   2.630V
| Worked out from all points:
|   GND clamp passes 1 mA (typ) near -0.54 V on its own axis
|   POWER clamp passes 1 mA (typ) near -0.57 V on its own axis
[GND_clamp]
|Voltage   I(typ)   I(min)   I(max)
-2.5V     -1.282A    -1.016A    -1.578A
-1.12V    -134.1mA   -158.9mA   -115.5mA
-1.06V    -85.09mA   -122.4mA   -55.06mA
-1V       -39.1mA    -86.04mA   -37.37mA
-940mV    -24.02mA   -49.66mA   -31.12mA
-880mV    -18.12mA   -20.86mA   -24.98mA
-820mV    -13.52mA   -11.33mA   -18.91mA
-760mV    -9.544mA   -7.234mA   -13.38mA
-640mV    -3.584mA   -2.829mA   -4.842mA
-520mV    -683.4uA   -673.7uA   -735.2uA
-400mV    -43.73uA   -63.95uA   -34.55uA
2.5V      0A         0A         0A
[POWER_clamp]
|Voltage   I(typ)   I(min)   I(max)
-2.5V     738.3mA    604.5mA    887.7mA
-1.16V    151.7mA    158.7mA    147.8mA
-1.1V     127.7mA    140.8mA    117.1mA
-1.04V    103.9mA    123mA      86.6mA
-920mV    56.84mA    87.75mA    26.36mA
-860mV    33.55mA    70.48mA    10.43mA
-800mV    11.46mA    53.02mA    7.397mA
-740mV    4.842mA    35.42mA    5.271mA
-680mV    2.899mA    17.9mA     3.46mA
-620mV    1.709mA    4.915mA    2.004mA
-380mV    49.91uA    69.71uA    52.26uA
5V        -493uA     -409.9uA   -609.6uA
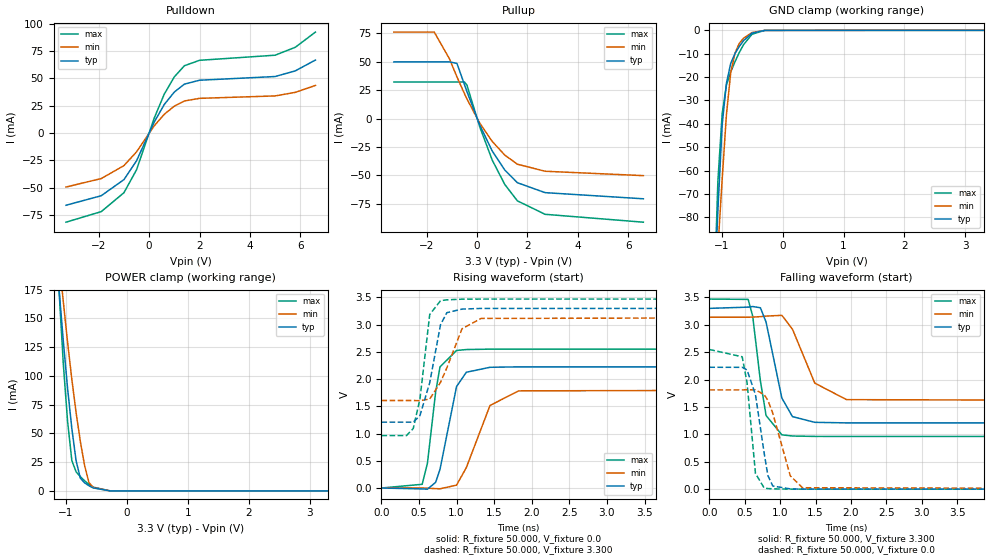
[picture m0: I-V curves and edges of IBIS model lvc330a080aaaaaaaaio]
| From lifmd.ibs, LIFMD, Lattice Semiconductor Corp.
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|   Model lvc330a080aaaaaaaaio
[Model] lvc330a080aaaaaaaaio
Model_type I/O
Polarity   Non-Inverting
Enable   Active-Low
Vinl =  0.800V
Vinh =  2.000V
Vmeas =  1.650V
Cref =  0.0F
Rref =  1.000M
Vref =  0.0V
C_comp   5.000pF   4.000pF   5.500pF
[Temperature Range]   25.000   0.125k   -40.000
[Voltage Range]   3.300V   3.140V   3.470V
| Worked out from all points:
|   slope of the pulldown table from 0 to 0.495 V, typ, clamps not added: 22.2 ohm
|   slope of the pullup table from 0 to 0.495 V, typ, clamps not added: 20.5 ohm
|   GND clamp passes 1 mA (typ) near -0.48 V on its own axis
|   POWER clamp passes 1 mA (typ) near -0.46 V on its own axis
|   rising waveform, R_fixture 50.000, V_fixture 0.0: 20-80 % time 185ps typ, 288ps min, 134ps max; typ from 0 V to 2.23 V
|   rising waveform, R_fixture 50.000, V_fixture 3.300: 20-80 % time 178ps typ, 261ps min, 124ps max; typ from 1.21 V to 3.3 V
|   falling waveform, R_fixture 50.000, V_fixture 3.300: 20-80 % time 207ps typ, 307ps min, 149ps max; typ from 3.3 V to 1.21 V
|   falling waveform, R_fixture 50.000, V_fixture 0.0: 20-80 % time 154ps typ, 231ps min, 107ps max; typ from 2.23 V to 0 V
[Pulldown]
|Voltage   I(typ)   I(min)   I(max)
-3.3V     -66.12mA   -49.45mA   -81.62mA
-1.9V     -57.38mA   -41.67mA   -71.93mA
-1V       -42.63mA   -29.84mA   -54.63mA
-500mV    -25.4mA    -17.23mA   -33.66mA
200mV     10mA       6.57mA     13.59mA
600mV     26.08mA    17.12mA    35.57mA
1V        37.51mA    24.6mA     51.39mA
1.4V      44.74mA    29.31mA    61.55mA
2V        48.29mA    31.71mA    66.54mA
5V        51.68mA    33.93mA    71.19mA
5.8V      56.86mA    37.2mA     78.45mA
6.6V      66.79mA    43.54mA    92.35mA
[Pullup]
|Voltage   I(typ)   I(min)   I(max)
-3.3V     49.76mA    75.94mA    32.09mA
-1.7V     49.76mA    75.94mA    32.09mA
-1.1V     49.76mA    52.63mA    32.09mA
-800mV    48.46mA    36.68mA    32.09mA
-500mV    29.82mA    21.85mA    32.09mA
-400mV    23.59mA    17.17mA    29.27mA
100mV     -5.404mA   -3.789mA   -6.933mA
600mV     -28.43mA   -20.06mA   -36.39mA
1.1V      -45.22mA   -32.08mA   -57.88mA
1.6V      -56.35mA   -40.11mA   -72.27mA
2.7V      -65.07mA   -46.28mA   -84.1mA
6.6V      -70.47mA   -50.13mA   -91.02mA
[GND_clamp]
|Voltage   I(typ)   I(min)   I(max)
-3.3V     -1.71A     -1.258A    -2.349A
-1.13V    -119.4mA   -124.8mA   -120.4mA
-1.06V    -76.91mA   -93.41mA   -64.42mA
-990mV    -40.37mA   -63.68mA   -35.65mA
-920mV    -22.62mA   -36.09mA   -23.42mA
-850mV    -14.16mA   -18.16mA   -17.82mA
-780mV    -9.927mA   -9.751mA   -13.44mA
-710mV    -6.91mA    -5.613mA   -9.526mA
-640mV    -4.44mA    -3.389mA   -6.157mA
-500mV    -1.202mA   -949.6uA   -1.652mA
-290mV    -17.25uA   -20.48uA   -19.31uA
3.3V      0A         0A         0A
[POWER_clamp]
|Voltage   I(typ)   I(min)   I(max)
-3.3V     2.101A     1.758A     3.757A
-1.11V    175.8mA    202.2mA    175mA
-1.04V    130.5mA    164.8mA    110.8mA
-970mV    89.45mA    129.5mA    60.76mA
-900mV    54.3mA     97.15mA    26.5mA
-830mV    26.3mA     68.21mA    16.62mA
-760mV    11.08mA    42.94mA    12.4mA
-690mV    7.003mA    21.99mA    8.787mA
-620mV    4.527mA    7.423mA    5.723mA
-550mV    2.623mA    2.943mA    3.295mA
-270mV    19.59uA    47.33uA    15.48uA
3.3V      0A         0A         0A
[Ramp]
| variable   typ   min   max
dV/dt_r   1.335/0.193n   1.087/0.298n   1.530/0.139n
dV/dt_f   1.255/0.212n   0.920/0.311n   1.505/0.156n
R_load = 50.000
[Rising Waveform]
R_fixture= 50.000
V_fixture= 0.0
V_fixture_min= 0.0
V_fixture_max= 0.0
|time   V(typ)   V(min)   V(max)
0s        0V         0V         0V
542ps     -16.67mV   648.7uV    68.39mV
612ps     -21.24mV   -3.415mV   456.9mV
721ps     104.6mV    -11.3mV    1.762V
779ps     343mV      -14.45mV   2.224V
999ps     1.863V     52.7mV     2.526V
1.129ns   2.126V     373.8mV    2.543V
1.444ns   2.217V     1.516V     2.55V
1.825ns   2.225V     1.784V     2.55V
10ns      2.225V     1.812V     2.55V
[Rising Waveform]
R_fixture= 50.000
V_fixture= 3.300
V_fixture_min= 3.140
V_fixture_max= 3.470
|time   V(typ)   V(min)   V(max)
0s        1.209V     1.607V     962.5mV
333ps     1.209V     1.607V     963.3mV
423ps     1.209V     1.607V     1.093V
512ps     1.329V     1.604V     1.633V
642ps     1.933V     1.634V     3.185V
786ps     2.999V     1.941V     3.441V
870ps     3.22V      2.207V     3.456V
1.072ns   3.286V     2.925V     3.468V
1.325ns   3.298V     3.114V     3.47V
10ns      3.3V       3.14V      3.47V
[Falling Waveform]
R_fixture= 50.000
V_fixture= 3.300
V_fixture_min= 3.140
V_fixture_max= 3.470
|time   V(typ)   V(min)   V(max)
0s        3.3V       3.14V      3.47V
548ps     3.323V     3.139V     3.464V
612ps     3.334V     3.141V     3.16V
721ps     3.311V     3.149V     1.974V
801ps     3.05V      3.159V     1.345V
1.024ns   1.663V     3.173V     991.9mV
1.174ns   1.324V     2.92V      970.1mV
1.489ns   1.22V      1.936V     963mV
1.938ns   1.21V      1.634V     962.5mV
10ns      1.209V     1.607V     962.5mV
[Falling Waveform]
R_fixture= 50.000
V_fixture= 0.0
V_fixture_min= 0.0
V_fixture_max= 0.0
|time   V(typ)   V(min)   V(max)
0s        2.225V     1.812V     2.55V
464ps     2.224V     1.812V     2.416V
532ps     2.176V     1.814V     1.95V
651ps     1.729V     1.813V     289.1mV
775ps     650.6mV    1.725V     19.02mV
827ps     247.7mV    1.621V     10.93mV
896ps     57.42mV    1.385V     5.737mV
1.143ns   4.883mV    243.5mV    610.6uV
1.315ns   1.378mV    26.1mV     127.7uV
10ns      0V         0V         0V
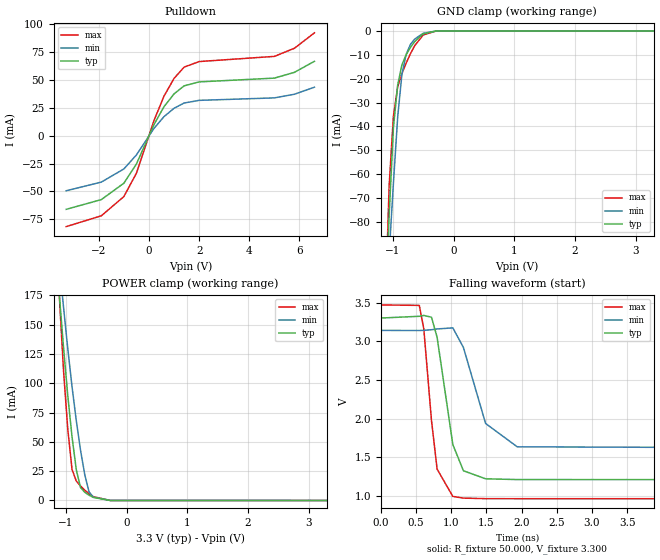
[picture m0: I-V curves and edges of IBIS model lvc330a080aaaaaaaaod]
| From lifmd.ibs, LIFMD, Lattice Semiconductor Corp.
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|   Model lvc330a080aaaaaaaaod
[Model] lvc330a080aaaaaaaaod
Model_type I/O_open_drain
Polarity   Non-Inverting
Enable   Active-Low
Vinl =  0.800V
Vinh =  2.000V
Vmeas =  1.650V
Cref =  0.0F
Rref =  10.000k
Vref =  3.30V
C_comp   5.000pF   4.000pF   5.500pF
[Temperature Range]   25.000   0.125k   -40.000
[Voltage Range]   3.300V   3.140V   3.470V
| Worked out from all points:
|   slope of the pulldown table from 0 to 0.495 V, typ, clamps not added: 22.2 ohm
|   GND clamp passes 1 mA (typ) near -0.48 V on its own axis
|   POWER clamp passes 1 mA (typ) near -0.46 V on its own axis
|   falling waveform, R_fixture 50.000, V_fixture 3.300: 20-80 % time 207ps typ, 307ps min, 149ps max; typ from 3.3 V to 1.21 V
[Pulldown]
|Voltage   I(typ)   I(min)   I(max)
-3.3V     -66.12mA   -49.45mA   -81.62mA
-1.9V     -57.38mA   -41.67mA   -71.93mA
-1V       -42.63mA   -29.84mA   -54.63mA
-500mV    -25.4mA    -17.23mA   -33.66mA
200mV     10mA       6.57mA     13.59mA
600mV     26.08mA    17.12mA    35.57mA
1V        37.51mA    24.6mA     51.39mA
1.4V      44.74mA    29.31mA    61.55mA
2V        48.29mA    31.71mA    66.54mA
5V        51.68mA    33.93mA    71.19mA
5.8V      56.86mA    37.2mA     78.45mA
6.6V      66.79mA    43.54mA    92.35mA
[GND_clamp]
|Voltage   I(typ)   I(min)   I(max)
-3.3V     -1.71A     -1.258A    -2.349A
-1.13V    -119.4mA   -124.8mA   -120.4mA
-1.06V    -76.91mA   -93.41mA   -64.42mA
-990mV    -40.37mA   -63.68mA   -35.65mA
-920mV    -22.62mA   -36.09mA   -23.42mA
-850mV    -14.16mA   -18.16mA   -17.82mA
-780mV    -9.927mA   -9.751mA   -13.44mA
-710mV    -6.91mA    -5.613mA   -9.526mA
-640mV    -4.44mA    -3.389mA   -6.157mA
-500mV    -1.202mA   -949.6uA   -1.652mA
-290mV    -17.25uA   -20.48uA   -19.31uA
3.3V      0A         0A         0A
[POWER_clamp]
|Voltage   I(typ)   I(min)   I(max)
-3.3V     2.101A     1.758A     3.757A
-1.11V    175.8mA    202.2mA    175mA
-1.04V    130.5mA    164.8mA    110.8mA
-970mV    89.45mA    129.5mA    60.76mA
-900mV    54.3mA     97.15mA    26.5mA
-830mV    26.3mA     68.21mA    16.62mA
-760mV    11.08mA    42.94mA    12.4mA
-690mV    7.003mA    21.99mA    8.787mA
-620mV    4.527mA    7.423mA    5.723mA
-550mV    2.623mA    2.943mA    3.295mA
-270mV    19.59uA    47.33uA    15.48uA
3.3V      0A         0A         0A
[Ramp]
| variable   typ   min   max
dV/dt_r   1.254/0.193n   0.920/0.298n   1.530/0.139n
dV/dt_f   1.255/0.212n   0.920/0.311n   1.505/0.156n
R_load = 50.000
[Falling Waveform]
R_fixture= 50.000
V_fixture= 3.300
V_fixture_min= 3.140
V_fixture_max= 3.470
|time   V(typ)   V(min)   V(max)
0s        3.3V       3.14V      3.47V
548ps     3.323V     3.139V     3.464V
612ps     3.334V     3.141V     3.16V
721ps     3.311V     3.149V     1.974V
801ps     3.05V      3.159V     1.345V
1.024ns   1.663V     3.173V     991.9mV
1.174ns   1.324V     2.92V      970.1mV
1.489ns   1.22V      1.936V     963mV
1.938ns   1.21V      1.634V     962.5mV
10ns      1.209V     1.607V     962.5mV
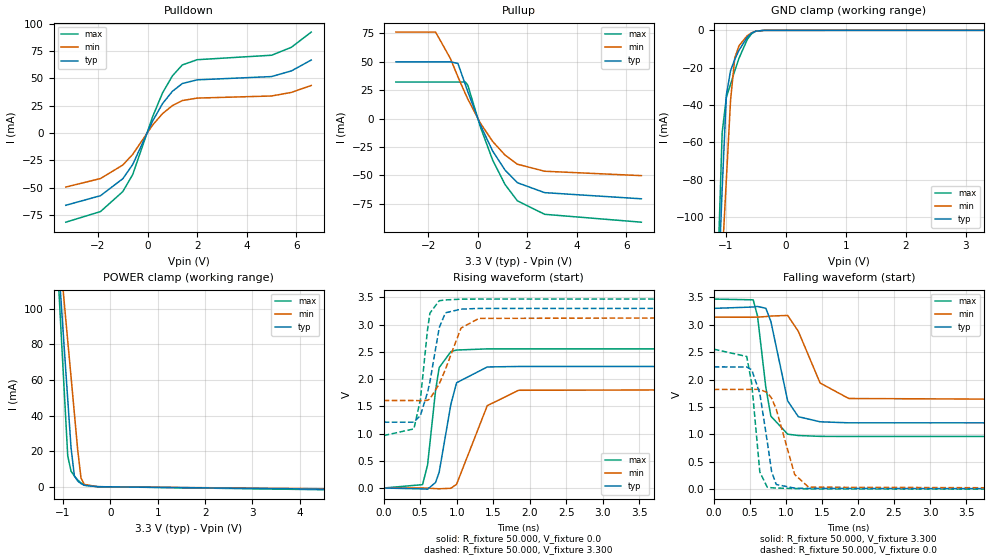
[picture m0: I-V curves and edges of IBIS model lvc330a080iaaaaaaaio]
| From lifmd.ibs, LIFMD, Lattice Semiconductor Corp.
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|   Model lvc330a080iaaaaaaaio
[Model] lvc330a080iaaaaaaaio
Model_type I/O
Polarity   Non-Inverting
Enable   Active-Low
Vinl =  0.800V
Vinh =  2.000V
Vmeas =  1.650V
Cref =  0.0F
Rref =  1.000M
Vref =  0.0V
C_comp   5.000pF   4.000pF   5.500pF
[Temperature Range]   25.000   0.125k   -40.000
[Voltage Range]   3.300V   3.140V   3.470V
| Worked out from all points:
|   slope of the pulldown table from 0 to 0.495 V, typ, clamps not added: 22.3 ohm
|   slope of the pullup table from 0 to 0.495 V, typ, clamps not added: 20.5 ohm
|   GND clamp passes 1 mA (typ) near -0.54 V on its own axis
|   POWER clamp passes 1 mA (typ) near -0.56 V on its own axis
|   rising waveform, R_fixture 50.000, V_fixture 0.0: 20-80 % time 177ps typ, 280ps min, 126ps max; typ from 0 V to 2.23 V
|   rising waveform, R_fixture 50.000, V_fixture 3.300: 20-80 % time 174ps typ, 258ps min, 121ps max; typ from 1.21 V to 3.3 V
|   falling waveform, R_fixture 50.000, V_fixture 3.300: 20-80 % time 203ps typ, 306ps min, 144ps max; typ from 3.3 V to 1.21 V
|   falling waveform, R_fixture 50.000, V_fixture 0.0: 20-80 % time 153ps typ, 230ps min, 105ps max; typ from 2.23 V to 0 V
[Pulldown]
|Voltage   I(typ)   I(min)   I(max)
-3.3V     -66mA      -49.35mA   -81.47mA
-1.9V     -57.24mA   -41.55mA   -71.75mA
-1V       -41.71mA   -29.19mA   -53.48mA
-600mV    -28.71mA   -19.43mA   -37.89mA
200mV     10.92mA    7.29mA     14.78mA
600mV     26.87mA    17.74mA    36.61mA
1V        38.19mA    25.12mA    52.29mA
1.4V      45.3mA     29.73mA    62.31mA
2V        48.67mA    31.99mA    67.08mA
5V        51.66mA    33.91mA    71.17mA
5.8V      56.84mA    37.19mA    78.43mA
6.6V      66.78mA    43.52mA    92.33mA
[Pullup]
|Voltage   I(typ)   I(min)   I(max)
-3.3V     49.76mA    75.94mA    32.09mA
-1.7V     49.76mA    75.94mA    32.09mA
-1.1V     49.76mA    52.63mA    32.09mA
-800mV    48.46mA    36.68mA    32.09mA
-500mV    29.82mA    21.85mA    32.09mA
-400mV    23.59mA    17.17mA    29.27mA
100mV     -5.404mA   -3.789mA   -6.933mA
600mV     -28.43mA   -20.06mA   -36.39mA
1.1V      -45.22mA   -32.08mA   -57.88mA
1.6V      -56.35mA   -40.11mA   -72.27mA
2.7V      -65.07mA   -46.28mA   -84.1mA
6.6V      -70.47mA   -50.13mA   -91.02mA
[GND_clamp]
|Voltage   I(typ)   I(min)   I(max)
-3.3V     -1.952A    -1.519A    -2.427A
-1.13V    -142mA     -164.6mA   -125.6mA
-1.06V    -84.84mA   -122.1mA   -54.71mA
-990mV    -34.57mA   -79.78mA   -35.86mA
-920mV    -21.56mA   -37.29mA   -28.84mA
-850mV    -15.58mA   -14.77mA   -21.67mA
-780mV    -10.69mA   -8.258mA   -14.98mA
-640mV    -3.549mA   -2.798mA   -4.8mA
-570mV    -1.511mA   -1.328mA   -1.856mA
-500mV    -467.6uA   -484.9uA   -473.3uA
-360mV    -12.93uA   -23.94uA   -8.743uA
3.3V      0A         0A         0A
[POWER_clamp]
|Voltage   I(typ)   I(min)   I(max)
-3.3V     1.153A     923.9mA    1.395A
-1.18V    159.7mA    164.8mA    158.1mA
-1.11V    131.7mA    143.8mA    122.2mA
-1.04V    104mA      123mA      86.66mA
-900mV    49.13mA    82mA       17.35mA
-830mV    21.96mA    61.81mA    8.795mA
-760mV    6.145mA    41.32mA    6.089mA
-690mV    3.258mA    20.86mA    3.879mA
-620mV    1.818mA    4.989mA    2.139mA
-550mV    856.3uA    1.358mA    942.2uA
-270mV    80.02uA    68.71uA    98.5uA
6.6V      -1.936mA   -1.612mA   -2.389mA
[Ramp]
| variable   typ   min   max
dV/dt_r   1.339/0.182n   1.092/0.287n   1.533/0.136n
dV/dt_f   1.255/0.206n   0.920/0.307n   1.505/0.147n
R_load = 50.000
[Rising Waveform]
R_fixture= 50.000
V_fixture= 0.0
V_fixture_min= 0.0
V_fixture_max= 0.0
|time   V(typ)   V(min)   V(max)
0s        0V         0V         0V
533ps     -16.5mV    682.2uV    61.67mV
602ps     -21.26mV   -3.459mV   426.3mV
711ps     101.2mV    -11.37mV   1.79V
760ps     287.4mV    -13.95mV   2.21V
921ps     1.539V     -5.199mV   2.505V
999ps     1.933V     69.18mV    2.534V
1.419ns   2.223V     1.512V     2.555V
1.849ns   2.232V     1.795V     2.555V
10ns      2.232V     1.82V      2.555V
[Rising Waveform]
R_fixture= 50.000
V_fixture= 3.300
V_fixture_min= 3.140
V_fixture_max= 3.470
|time   V(typ)   V(min)   V(max)
0s        1.209V     1.607V     962.5mV
414ps     1.209V     1.607V     1.086V
503ps     1.33V      1.604V     1.62V
601ps     1.755V     1.61V      2.909V
634ps     1.953V     1.637V     3.213V
761ps     2.943V     1.911V     3.44V
845ps     3.217V     2.175V     3.454V
1.059ns   3.285V     2.937V     3.468V
1.305ns   3.298V     3.115V     3.47V
10ns      3.3V       3.14V      3.47V
[Falling Waveform]
R_fixture= 50.000
V_fixture= 3.300
V_fixture_min= 3.140
V_fixture_max= 3.470
|time   V(typ)   V(min)   V(max)
0s        3.3V       3.14V      3.47V
547ps     3.325V     3.139V     3.456V
607ps     3.335V     3.141V     3.16V
722ps     3.302V     3.15V      1.86V
792ps     3.063V     3.16V      1.333V
1.025ns   1.613V     3.171V     1.004V
1.173ns   1.323V     2.882V     979.5mV
1.475ns   1.23V      1.938V     964mV
1.873ns   1.211V     1.655V     962.5mV
10ns      1.209V     1.607V     962.5mV
[Falling Waveform]
R_fixture= 50.000
V_fixture= 0.0
V_fixture_min= 0.0
V_fixture_max= 0.0
|time   V(typ)   V(min)   V(max)
0s        2.232V     1.82V      2.555V
457ps     2.23V      1.82V      2.422V
527ps     2.178V     1.823V     1.925V
639ps     1.746V     1.822V     311.3mV
742ps     871.1mV    1.763V     35.7mV
802ps     325mV      1.661V     25.6mV
866ps     85.48mV    1.462V     20.42mV
1.122ns   18.62mV    267.7mV    11.44mV
1.316ns   13.93mV    36.21mV    3.076mV
10ns      0V         0V         0V
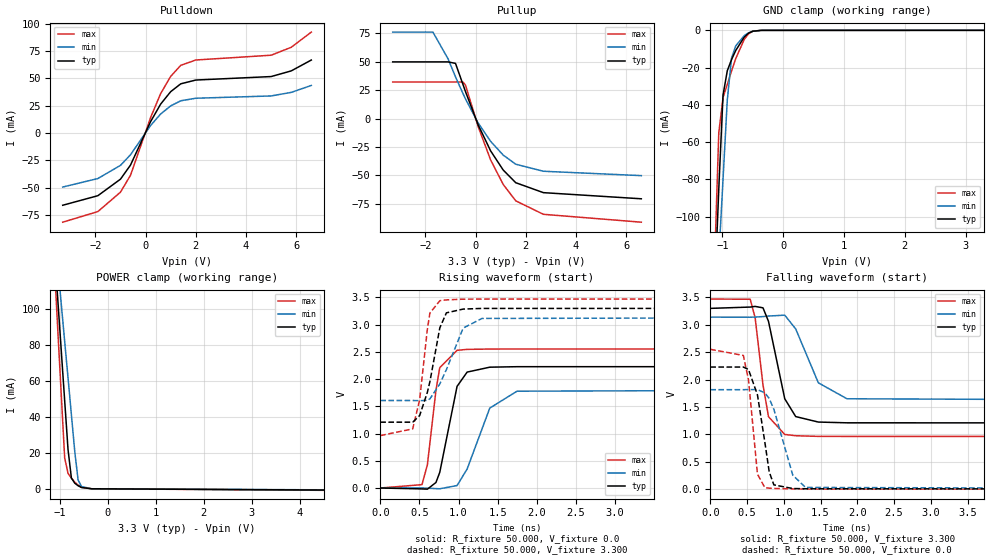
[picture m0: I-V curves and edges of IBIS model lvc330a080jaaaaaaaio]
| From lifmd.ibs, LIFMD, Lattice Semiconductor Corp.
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|   Model lvc330a080jaaaaaaaio
[Model] lvc330a080jaaaaaaaio
Model_type I/O
Polarity   Non-Inverting
Enable   Active-Low
Vinl =  0.800V
Vinh =  2.000V
Vmeas =  1.650V
Cref =  0.0F
Rref =  1.000M
Vref =  0.0V
C_comp   5.000pF   4.000pF   5.500pF
[Temperature Range]   25.000   0.125k   -40.000
[Voltage Range]   3.300V   3.140V   3.470V
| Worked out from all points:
|   slope of the pulldown table from 0 to 0.495 V, typ, clamps not added: 22.2 ohm
|   slope of the pullup table from 0 to 0.495 V, typ, clamps not added: 20.5 ohm
|   GND clamp passes 1 mA (typ) near -0.54 V on its own axis
|   POWER clamp passes 1 mA (typ) near -0.57 V on its own axis
|   rising waveform, R_fixture 50.000, V_fixture 0.0: 20-80 % time 177ps typ, 279ps min, 126ps max; typ from 0 V to 2.23 V
|   rising waveform, R_fixture 50.000, V_fixture 3.300: 20-80 % time 174ps typ, 258ps min, 121ps max; typ from 1.21 V to 3.3 V
|   falling waveform, R_fixture 50.000, V_fixture 3.300: 20-80 % time 201ps typ, 303ps min, 143ps max; typ from 3.3 V to 1.21 V
|   falling waveform, R_fixture 50.000, V_fixture 0.0: 20-80 % time 152ps typ, 228ps min, 105ps max; typ from 2.23 V to 0 V
[Pulldown]
|Voltage   I(typ)   I(min)   I(max)
-3.3V     -66.06mA   -49.4mA    -81.55mA
-1.9V     -57.31mA   -41.62mA   -71.84mA
-1V       -42.19mA   -29.57mA   -54.08mA
-600mV    -29.28mA   -19.88mA   -38.63mA
200mV     10.46mA    6.928mA    14.18mA
600mV     26.47mA    17.43mA    36.09mA
1V        37.85mA    24.86mA    51.84mA
1.4V      45.02mA    29.52mA    61.93mA
2V        48.48mA    31.84mA    66.81mA
5V        51.67mA    33.93mA    71.19mA
5.8V      56.85mA    37.2mA     78.45mA
6.6V      66.79mA    43.54mA    92.35mA
[Pullup]
|Voltage   I(typ)   I(min)   I(max)
-3.3V     49.76mA    75.94mA    32.09mA
-1.7V     49.76mA    75.94mA    32.09mA
-1.1V     49.76mA    52.63mA    32.09mA
-800mV    48.46mA    36.68mA    32.09mA
-500mV    29.82mA    21.85mA    32.09mA
-400mV    23.59mA    17.17mA    29.27mA
100mV     -5.404mA   -3.789mA   -6.933mA
600mV     -28.43mA   -20.06mA   -36.39mA
1.1V      -45.22mA   -32.08mA   -57.88mA
1.6V      -56.35mA   -40.11mA   -72.27mA
2.7V      -65.07mA   -46.28mA   -84.1mA
6.6V      -70.47mA   -50.13mA   -91.02mA
[GND_clamp]
|Voltage   I(typ)   I(min)   I(max)
-3.3V     -1.953A    -1.52A     -2.429A
-1.13V    -142.2mA   -164.8mA   -125.9mA
-1.06V    -85.01mA   -122.3mA   -54.94mA
-990mV    -34.72mA   -79.9mA    -36.06mA
-920mV    -21.68mA   -37.38mA   -29.02mA
-850mV    -15.68mA   -14.84mA   -21.81mA
-780mV    -10.75mA   -8.308mA   -15.07mA
-640mV    -3.563mA   -2.813mA   -4.814mA
-570mV    -1.515mA   -1.333mA   -1.859mA
-500mV    -468.4uA   -486.1uA   -473.9uA
-360mV    -12.99uA   -24.02uA   -8.824uA
3.3V      0A         0A         0A
[POWER_clamp]
|Voltage   I(typ)   I(min)   I(max)
-3.3V     1.153A     923.9mA    1.395A
-1.18V    159.7mA    164.7mA    158mA
-1.11V    131.7mA    143.8mA    122.2mA
-1.04V    103.9mA    123mA      86.61mA
-900mV    49.08mA    81.98mA    17.22mA
-830mV    21.88mA    61.79mA    8.669mA
-760mV    6.05mA     41.29mA    5.969mA
-690mV    3.166mA    20.82mA    3.766mA
-620mV    1.732mA    4.929mA    2.034mA
-550mV    777.9uA    1.295mA    845.2uA
-340mV    53.28uA    55.84uA    62.85uA
6.6V      -964.4uA   -802.6uA   -1.19mA
[Ramp]
| variable   typ   min   max
dV/dt_r   1.337/0.179n   1.090/0.285n   1.532/0.135n
dV/dt_f   1.255/0.204n   0.920/0.304n   1.505/0.145n
R_load = 50.000
[Rising Waveform]
R_fixture= 50.000
V_fixture= 0.0
V_fixture_min= 0.0
V_fixture_max= 0.0
|time   V(typ)   V(min)   V(max)
0s        0V         0V         0V
533ps     -16.5mV    682.2uV    61.67mV
602ps     -21.26mV   -3.459mV   426.3mV
711ps     101.2mV    -11.37mV   1.79V
760ps     287.4mV    -13.95mV   2.21V
981ps     1.867V     45.16mV    2.529V
1.11ns    2.129V     349.8mV    2.546V
1.399ns   2.219V     1.468V     2.552V
1.747ns   2.228V     1.778V     2.553V
10ns      2.229V     1.816V     2.553V
[Rising Waveform]
R_fixture= 50.000
V_fixture= 3.300
V_fixture_min= 3.140
V_fixture_max= 3.470
|time   V(typ)   V(min)   V(max)
0s        1.209V     1.607V     962.5mV
414ps     1.209V     1.607V     1.086V
503ps     1.33V      1.604V     1.62V
601ps     1.755V     1.61V      2.909V
634ps     1.953V     1.637V     3.213V
761ps     2.943V     1.911V     3.44V
845ps     3.217V     2.175V     3.455V
1.059ns   3.286V     2.937V     3.468V
1.299ns   3.298V     3.114V     3.47V
10ns      3.3V       3.14V      3.47V
[Falling Waveform]
R_fixture= 50.000
V_fixture= 3.300
V_fixture_min= 3.140
V_fixture_max= 3.470
|time   V(typ)   V(min)   V(max)
0s        3.3V       3.14V      3.47V
543ps     3.324V     3.139V     3.467V
610ps     3.336V     3.141V     3.132V
717ps     3.31V      3.15V      1.904V
792ps     3.063V     3.16V      1.323V
1.013ns   1.65V      3.176V     998.9mV
1.162ns   1.325V     2.925V     975.3mV
1.47ns    1.225V     1.941V     963.6mV
1.86ns    1.211V     1.65V      962.5mV
10ns      1.209V     1.607V     962.5mV
[Falling Waveform]
R_fixture= 50.000
V_fixture= 0.0
V_fixture_min= 0.0
V_fixture_max= 0.0
|time   V(typ)   V(min)   V(max)
0s        2.229V     1.816V     2.553V
450ps     2.229V     1.816V     2.441V
520ps     2.184V     1.818V     1.995V
642ps     1.72V      1.817V     274.2mV
742ps     860.3mV    1.758V     28.16mV
802ps     314.2mV    1.655V     18.4mV
865ps     78.28mV    1.459V     13.47mV
1.122ns   11.82mV    256mV      5.86mV
1.296ns   7.841mV    31.37mV    1.852mV
10ns      0V         0V         0V
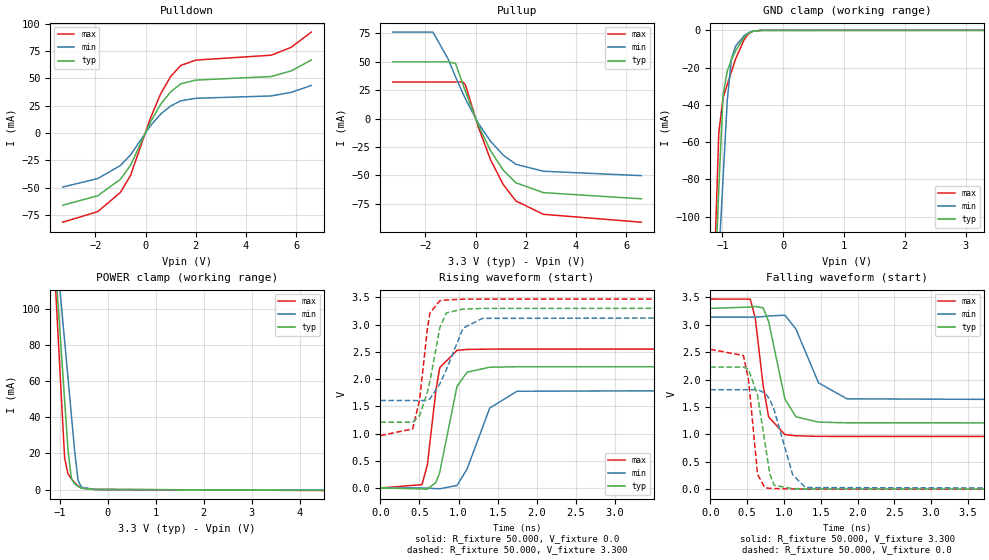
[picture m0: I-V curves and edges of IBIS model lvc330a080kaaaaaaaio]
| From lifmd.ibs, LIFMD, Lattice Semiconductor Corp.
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|   Model lvc330a080kaaaaaaaio
[Model] lvc330a080kaaaaaaaio
Model_type I/O
Polarity   Non-Inverting
Enable   Active-Low
Vinl =  0.800V
Vinh =  2.000V
Vmeas =  1.650V
Cref =  0.0F
Rref =  1.000M
Vref =  0.0V
C_comp   5.000pF   4.000pF   5.500pF
[Temperature Range]   25.000   0.125k   -40.000
[Voltage Range]   3.300V   3.140V   3.470V
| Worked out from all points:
|   slope of the pulldown table from 0 to 0.495 V, typ, clamps not added: 22.2 ohm
|   slope of the pullup table from 0 to 0.495 V, typ, clamps not added: 20.5 ohm
|   GND clamp passes 1 mA (typ) near -0.54 V on its own axis
|   POWER clamp passes 1 mA (typ) near -0.57 V on its own axis
|   rising waveform, R_fixture 50.000, V_fixture 0.0: 20-80 % time 177ps typ, 279ps min, 126ps max; typ from 0 V to 2.23 V
|   rising waveform, R_fixture 50.000, V_fixture 3.300: 20-80 % time 174ps typ, 258ps min, 121ps max; typ from 1.21 V to 3.3 V
|   falling waveform, R_fixture 50.000, V_fixture 3.300: 20-80 % time 201ps typ, 302ps min, 143ps max; typ from 3.3 V to 1.21 V
|   falling waveform, R_fixture 50.000, V_fixture 0.0: 20-80 % time 152ps typ, 227ps min, 104ps max; typ from 2.23 V to 0 V
[Pulldown]
|Voltage   I(typ)   I(min)   I(max)
-3.3V     -66.08mA   -49.42mA   -81.58mA
-1.9V     -57.33mA   -41.63mA   -71.87mA
-1V       -42.33mA   -29.67mA   -54.26mA
-600mV    -29.46mA   -20.02mA   -38.85mA
200mV     10.31mA    6.813mA    13.99mA
600mV     26.34mA    17.33mA    35.92mA
1V        37.74mA    24.77mA    51.7mA
1.4V      44.93mA    29.45mA    61.81mA
2V        48.42mA    31.8mA     66.72mA
5V        51.68mA    33.93mA    71.19mA
5.8V      56.85mA    37.2mA     78.45mA
6.6V      66.79mA    43.54mA    92.35mA
[Pullup]
|Voltage   I(typ)   I(min)   I(max)
-3.3V     49.76mA    75.94mA    32.09mA
-1.7V     49.76mA    75.94mA    32.09mA
-1.1V     49.76mA    52.63mA    32.09mA
-800mV    48.46mA    36.68mA    32.09mA
-500mV    29.82mA    21.85mA    32.09mA
-400mV    23.59mA    17.17mA    29.27mA
100mV     -5.404mA   -3.789mA   -6.933mA
600mV     -28.43mA   -20.06mA   -36.39mA
1.1V      -45.22mA   -32.08mA   -57.88mA
1.6V      -56.35mA   -40.11mA   -72.27mA
2.7V      -65.07mA   -46.28mA   -84.1mA
6.6V      -70.47mA   -50.13mA   -91.02mA
[GND_clamp]
|Voltage   I(typ)   I(min)   I(max)
-3.3V     -1.953A    -1.52A     -2.429A
-1.13V    -142.2mA   -164.9mA   -126mA
-1.06V    -85.07mA   -122.3mA   -55.02mA
-990mV    -34.78mA   -79.96mA   -36.14mA
-920mV    -21.73mA   -37.42mA   -29.09mA
-850mV    -15.72mA   -14.87mA   -21.87mA
-780mV    -10.79mA   -8.332mA   -15.12mA
-640mV    -3.576mA   -2.823mA   -4.831mA
-570mV    -1.52mA    -1.338mA   -1.864mA
-500mV    -469.6uA   -487.6uA   -474.9uA
-360mV    -13.02uA   -24.08uA   -8.843uA
3.3V      0A         0A         0A
[POWER_clamp]
|Voltage   I(typ)   I(min)   I(max)
-3.3V     1.153A     923.9mA    1.395A
-1.18V    159.7mA    164.7mA    158mA
-1.11V    131.7mA    143.8mA    122.2mA
-1.04V    103.9mA    123mA      86.6mA
-900mV    49.07mA    81.98mA    17.21mA
-830mV    21.86mA    61.79mA    8.649mA
-760mV    6.031mA    41.28mA    5.945mA
-690mV    3.144mA    20.81mA    3.739mA
-620mV    1.709mA    4.915mA    2.004mA
-550mV    754.4uA    1.278mA    815.8uA
-270mV    27.09uA    24.73uA    33.18uA
6.6V      -653.7uA   -545.5uA   -806.5uA
[Ramp]
| variable   typ   min   max
dV/dt_r   1.337/0.179n   1.089/0.284n   1.531/0.135n
dV/dt_f   1.255/0.203n   0.920/0.303n   1.505/0.145n
R_load = 50.000
[Rising Waveform]
R_fixture= 50.000
V_fixture= 0.0
V_fixture_min= 0.0
V_fixture_max= 0.0
|time   V(typ)   V(min)   V(max)
0s        0V         0V         0V
533ps     -16.5mV    682.2uV    61.67mV
602ps     -21.26mV   -3.459mV   426.3mV
711ps     101.2mV    -11.37mV   1.79V
760ps     287.4mV    -13.95mV   2.21V
981ps     1.867V     45.16mV    2.528V
1.111ns   2.129V     353.8mV    2.545V
1.399ns   2.218V     1.468V     2.551V
1.748ns   2.227V     1.777V     2.552V
10ns      2.228V     1.815V     2.552V
[Rising Waveform]
R_fixture= 50.000
V_fixture= 3.300
V_fixture_min= 3.140
V_fixture_max= 3.470
|time   V(typ)   V(min)   V(max)
0s        1.209V     1.607V     962.5mV
414ps     1.209V     1.607V     1.086V
503ps     1.33V      1.604V     1.62V
601ps     1.755V     1.61V      2.909V
634ps     1.953V     1.637V     3.213V
761ps     2.943V     1.911V     3.44V
845ps     3.217V     2.175V     3.454V
1.059ns   3.286V     2.937V     3.468V
1.305ns   3.298V     3.115V     3.47V
10ns      3.3V       3.14V      3.47V
[Falling Waveform]
R_fixture= 50.000
V_fixture= 3.300
V_fixture_min= 3.140
V_fixture_max= 3.470
|time   V(typ)   V(min)   V(max)
0s        3.3V       3.14V      3.47V
543ps     3.324V     3.139V     3.468V
610ps     3.336V     3.141V     3.132V
717ps     3.31V      3.15V      1.903V
792ps     3.063V     3.16V      1.321V
1.013ns   1.648V     3.176V     996.5mV
1.162ns   1.322V     2.925V     974.3mV
1.47ns    1.224V     1.94V      963.6mV
1.857ns   1.211V     1.649V     962.5mV
10ns      1.209V     1.607V     962.5mV
[Falling Waveform]
R_fixture= 50.000
V_fixture= 0.0
V_fixture_min= 0.0
V_fixture_max= 0.0
|time   V(typ)   V(min)   V(max)
0s        2.228V     1.815V     2.552V
450ps     2.228V     1.815V     2.44V
520ps     2.183V     1.817V     1.993V
642ps     1.718V     1.816V     271.7mV
742ps     857.8mV    1.757V     25.92mV
807ps     280.9mV    1.641V     15.64mV
868ps     71.04mV    1.445V     11.1mV
1.118ns   9.831mV    266.6mV    4.764mV
1.291ns   5.956mV    29.86mV    1.78mV
10ns      0V         0V         0V
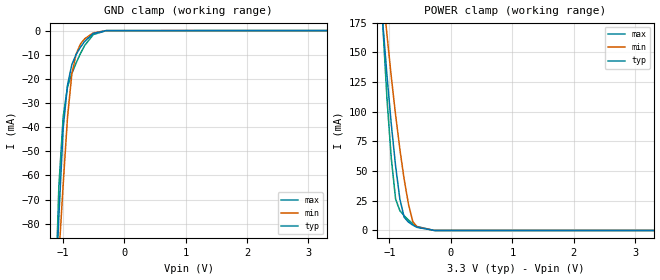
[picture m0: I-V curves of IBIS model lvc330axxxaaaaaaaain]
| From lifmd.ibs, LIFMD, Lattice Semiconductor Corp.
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|   Model lvc330axxxaaaaaaaain
[Model] lvc330axxxaaaaaaaain
Model_type Input
Polarity   Non-Inverting
Vinl =  0.800V
Vinh =  2.000V
C_comp   5.000pF   4.000pF   5.500pF
[Temperature Range]   25.000   0.125k   -40.000
[Voltage Range]   3.300V   3.140V   3.470V
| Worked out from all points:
|   GND clamp passes 1 mA (typ) near -0.48 V on its own axis
|   POWER clamp passes 1 mA (typ) near -0.46 V on its own axis
[GND_clamp]
|Voltage   I(typ)   I(min)   I(max)
-3.3V     -1.71A     -1.258A    -2.349A
-1.13V    -119.4mA   -124.8mA   -120.4mA
-1.06V    -76.91mA   -93.41mA   -64.42mA
-990mV    -40.37mA   -63.68mA   -35.65mA
-920mV    -22.62mA   -36.09mA   -23.42mA
-850mV    -14.16mA   -18.16mA   -17.82mA
-780mV    -9.927mA   -9.751mA   -13.44mA
-710mV    -6.91mA    -5.613mA   -9.526mA
-640mV    -4.44mA    -3.389mA   -6.157mA
-500mV    -1.202mA   -949.6uA   -1.652mA
-290mV    -17.25uA   -20.48uA   -19.31uA
3.3V      0A         0A         0A
[POWER_clamp]
|Voltage   I(typ)   I(min)   I(max)
-3.3V     2.101A     1.758A     3.757A
-1.11V    175.8mA    202.2mA    175mA
-1.04V    130.5mA    164.8mA    110.8mA
-970mV    89.45mA    129.5mA    60.76mA
-900mV    54.3mA     97.15mA    26.5mA
-830mV    26.3mA     68.21mA    16.62mA
-760mV    11.08mA    42.94mA    12.4mA
-690mV    7.003mA    21.99mA    8.787mA
-620mV    4.527mA    7.423mA    5.723mA
-550mV    2.623mA    2.943mA    3.295mA
-270mV    19.59uA    47.33uA    15.48uA
3.3V      0A         0A         0A
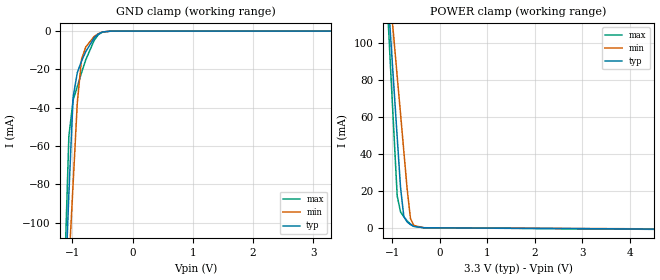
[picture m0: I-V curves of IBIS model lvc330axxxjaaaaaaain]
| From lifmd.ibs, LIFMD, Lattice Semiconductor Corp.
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|   Model lvc330axxxjaaaaaaain
[Model] lvc330axxxjaaaaaaain
Model_type Input
Polarity   Non-Inverting
Vinl =  0.800V
Vinh =  2.000V
C_comp   5.000pF   4.000pF   5.500pF
[Temperature Range]   25.000   0.125k   -40.000
[Voltage Range]   3.300V   3.140V   3.470V
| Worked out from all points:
|   GND clamp passes 1 mA (typ) near -0.54 V on its own axis
|   POWER clamp passes 1 mA (typ) near -0.57 V on its own axis
[GND_clamp]
|Voltage   I(typ)   I(min)   I(max)
-3.3V     -1.953A    -1.52A     -2.429A
-1.13V    -142.2mA   -164.8mA   -125.9mA
-1.06V    -85.01mA   -122.3mA   -54.94mA
-990mV    -34.72mA   -79.9mA    -36.06mA
-920mV    -21.68mA   -37.38mA   -29.02mA
-850mV    -15.68mA   -14.84mA   -21.81mA
-780mV    -10.75mA   -8.308mA   -15.07mA
-640mV    -3.563mA   -2.813mA   -4.814mA
-570mV    -1.515mA   -1.333mA   -1.859mA
-500mV    -468.4uA   -486.1uA   -473.9uA
-360mV    -12.99uA   -24.02uA   -8.824uA
3.3V      0A         0A         0A
[POWER_clamp]
|Voltage   I(typ)   I(min)   I(max)
-3.3V     1.153A     923.9mA    1.395A
-1.18V    159.7mA    164.7mA    158mA
-1.11V    131.7mA    143.8mA    122.2mA
-1.04V    103.9mA    123mA      86.61mA
-900mV    49.08mA    81.98mA    17.22mA
-830mV    21.88mA    61.79mA    8.669mA
-760mV    6.05mA     41.29mA    5.969mA
-690mV    3.166mA    20.82mA    3.766mA
-620mV    1.732mA    4.929mA    2.034mA
-550mV    777.9uA    1.295mA    845.2uA
-340mV    53.28uA    55.84uA    62.85uA
6.6V      -964.4uA   -802.6uA   -1.19mA
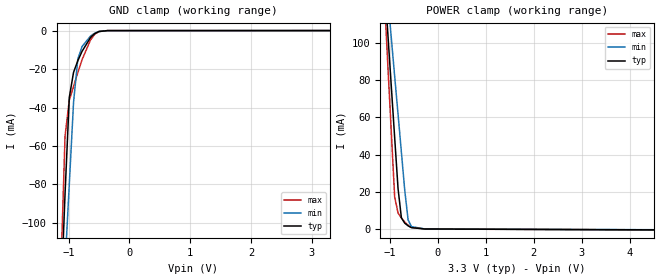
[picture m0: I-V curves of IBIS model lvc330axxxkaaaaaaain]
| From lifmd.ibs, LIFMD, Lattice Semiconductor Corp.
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|   Model lvc330axxxkaaaaaaain
[Model] lvc330axxxkaaaaaaain
Model_type Input
Polarity   Non-Inverting
Vinl =  0.800V
Vinh =  2.000V
C_comp   5.000pF   4.000pF   5.500pF
[Temperature Range]   25.000   0.125k   -40.000
[Voltage Range]   3.300V   3.140V   3.470V
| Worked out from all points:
|   GND clamp passes 1 mA (typ) near -0.54 V on its own axis
|   POWER clamp passes 1 mA (typ) near -0.57 V on its own axis
[GND_clamp]
|Voltage   I(typ)   I(min)   I(max)
-3.3V     -1.953A    -1.52A     -2.429A
-1.13V    -142.2mA   -164.9mA   -126mA
-1.06V    -85.07mA   -122.3mA   -55.02mA
-990mV    -34.78mA   -79.96mA   -36.14mA
-920mV    -21.73mA   -37.42mA   -29.09mA
-850mV    -15.72mA   -14.87mA   -21.87mA
-780mV    -10.79mA   -8.332mA   -15.12mA
-640mV    -3.576mA   -2.823mA   -4.831mA
-570mV    -1.52mA    -1.338mA   -1.864mA
-500mV    -469.6uA   -487.6uA   -474.9uA
-360mV    -13.02uA   -24.08uA   -8.843uA
3.3V      0A         0A         0A
[POWER_clamp]
|Voltage   I(typ)   I(min)   I(max)
-3.3V     1.153A     923.9mA    1.395A
-1.18V    159.7mA    164.7mA    158mA
-1.11V    131.7mA    143.8mA    122.2mA
-1.04V    103.9mA    123mA      86.6mA
-900mV    49.07mA    81.98mA    17.21mA
-830mV    21.86mA    61.79mA    8.649mA
-760mV    6.031mA    41.28mA    5.945mA
-690mV    3.144mA    20.81mA    3.739mA
-620mV    1.709mA    4.915mA    2.004mA
-550mV    754.4uA    1.278mA    815.8uA
-270mV    27.09uA    24.73uA    33.18uA
6.6V      -653.7uA   -545.5uA   -806.5uA
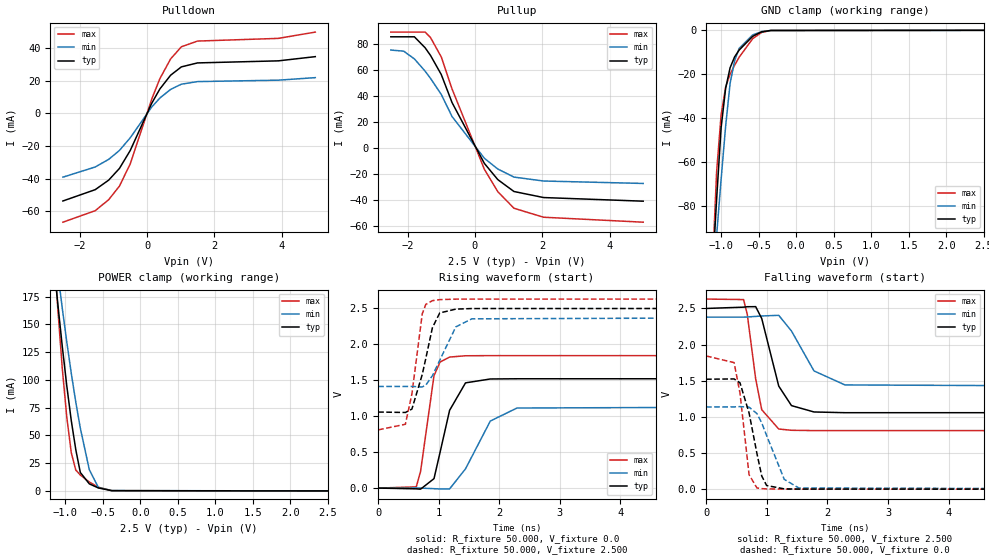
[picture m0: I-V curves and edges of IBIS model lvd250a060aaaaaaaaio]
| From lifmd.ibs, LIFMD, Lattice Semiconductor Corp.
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|   Model lvd250a060aaaaaaaaio
[Model] lvd250a060aaaaaaaaio
Model_type I/O
Polarity   Non-Inverting
Enable   Active-Low
Vinl =  0.700V
Vinh =  1.700V
Vmeas =  1.250V
Cref =  0.0F
Rref =  1.000M
Vref =  0.0V
C_comp   5.000pF   4.000pF   5.500pF
[Temperature Range]   25.000   0.125k   -40.000
[Voltage Range]   2.500V   2.380V   2.630V
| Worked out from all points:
|   slope of the pulldown table from 0 to 0.375 V, typ, clamps not added: 25.5 ohm
|   slope of the pullup table from 0 to 0.375 V, typ, clamps not added: 25 ohm
|   GND clamp passes 1 mA (typ) near -0.48 V on its own axis
|   POWER clamp passes 1 mA (typ) near -0.47 V on its own axis
|   rising waveform, R_fixture 50.000, V_fixture 0.0: 20-80 % time 257ps typ, 408ps min, 176ps max; typ from 0 V to 1.52 V
|   rising waveform, R_fixture 50.000, V_fixture 2.500: 20-80 % time 230ps typ, 319ps min, 166ps max; typ from 1.06 V to 2.5 V
|   falling waveform, R_fixture 50.000, V_fixture 2.500: 20-80 % time 282ps typ, 406ps min, 192ps max; typ from 2.5 V to 1.06 V
|   falling waveform, R_fixture 50.000, V_fixture 0.0: 20-80 % time 216ps typ, 310ps min, 147ps max; typ from 1.52 V to 0 V
[Pulldown]
|Voltage   I(typ)   I(min)   I(max)
-2.5V     -53.73mA   -39.13mA   -66.73mA
-1.54V    -46.8mA    -32.9mA    -59.68mA
-1.14V    -40.97mA   -28.24mA   -52.95mA
-820mV    -33.79mA   -22.77mA   -44.63mA
-500mV    -22.83mA   -15.02mA   -31.03mA
140mV     6.15mA     3.852mA    8.723mA
380mV     14.88mA    9.328mA    21.16mA
700mV     23.33mA    14.63mA    33.3mA
1.02V     28.45mA    17.84mA    40.76mA
1.5V      30.88mA    19.43mA    44.27mA
3.9V      32.14mA    20.3mA     45.91mA
5V        34.72mA    21.86mA    49.77mA
[Pullup]
|Voltage   I(typ)   I(min)   I(max)
-2.5V     85.63mA    75.44mA    89.24mA
-2.12V    85.63mA    74.62mA    89.24mA
-1.8V     85.63mA    68.69mA    89.24mA
-1.48V    77.18mA    59.23mA    89.24mA
-1.32V    71.31mA    53.67mA    85.06mA
-1V       56.6mA     41.33mA    70.1mA
-680mV    35.1mA     24.39mA    45.54mA
280mV     -11.59mA   -7.633mA   -16.08mA
680mV     -24.05mA   -15.94mA   -33.31mA
1.16V     -33.16mA   -22.09mA   -46.03mA
2.04V     -37.8mA    -25.11mA   -52.92mA
5V        -40.59mA   -26.98mA   -56.72mA
[GND_clamp]
|Voltage   I(typ)   I(min)   I(max)
-2.5V     -1.11A     -830.4mA   -1.508A
-1.12V    -113.2mA   -120.2mA   -111.9mA
-1.06V    -76.91mA   -93.41mA   -64.42mA
-1V       -44.35mA   -67.81mA   -38.46mA
-940mV    -26.44mA   -43.73mA   -25.84mA
-880mV    -17mA      -24.08mA   -19.92mA
-820mV    -12.07mA   -13.83mA   -15.88mA
-760mV    -8.998mA   -8.257mA   -12.27mA
-580mV    -2.762mA   -2.111mA   -3.825mA
-460mV    -702.7uA   -570.8uA   -955.8uA
-340mV    -67.3uA    -66.5uA    -79.08uA
2.5V      0A         0A         0A
[POWER_clamp]
|Voltage   I(typ)   I(min)   I(max)
-2.5V     1.335A     1.134A     2.299A
-1.16V    209.6mA    229.7mA    226.6mA
-1.1V     168.7mA    196.5mA    164.4mA
-1.04V    130.1mA    164.5mA    110.3mA
-980mV    94.59mA    134.1mA    66.45mA
-920mV    63.27mA    105.8mA    34.35mA
-860mV    37.18mA    79.96mA    18.78mA
-800mV    16.66mA    56.66mA    14.36mA
-680mV    6.381mA    19.15mA    8.023mA
-560mV    2.685mA    3.173mA    3.362mA
-380mV    223.7uA    310.4uA    250.2uA
2.5V      0A         0A         0A
[Ramp]
| variable   typ   min   max
dV/dt_r   0.913/0.258n   0.682/0.411n   1.106/0.179n
dV/dt_f   0.865/0.289n   0.580/0.412n   1.092/0.198n
R_load = 50.000
[Rising Waveform]
R_fixture= 50.000
V_fixture= 0.0
V_fixture_min= 0.0
V_fixture_max= 0.0
|time   V(typ)   V(min)   V(max)
0s        0V         0V         0V
629ps     -10.41mV   612.6uV    17.12mV
700ps     -15.07mV   -96.88uV   230.3mV
922ps     131.4mV    -8.45mV    1.563V
1.021ns   492.1mV    -11.96mV   1.753V
1.18ns    1.082V     -11.56mV   1.823V
1.443ns   1.464V     267.9mV    1.841V
1.853ns   1.518V     933.2mV    1.843V
2.294ns   1.521V     1.114V     1.843V
10ns      1.521V     1.137V     1.843V
[Rising Waveform]
R_fixture= 50.000
V_fixture= 2.500
V_fixture_min= 2.380
V_fixture_max= 2.630
|time   V(typ)   V(min)   V(max)
0s        1.058V     1.414V     810.2mV
449ps     1.052V     1.414V     887.8mV
557ps     1.099V     1.414V     1.308V
728ps     1.58V      1.407V     2.425V
787ps     1.805V     1.433V     2.556V
896ps     2.232V     1.564V     2.608V
1.017ns   2.437V     1.778V     2.622V
1.282ns   2.49V      2.242V     2.629V
1.546ns   2.498V     2.355V     2.63V
10ns      2.5V       2.38V      2.63V
[Falling Waveform]
R_fixture= 50.000
V_fixture= 2.500
V_fixture_min= 2.380
V_fixture_max= 2.630
|time   V(typ)   V(min)   V(max)
0s        2.5V       2.38V      2.63V
617ps     2.518V     2.38V      2.623V
678ps     2.524V     2.382V     2.421V
817ps     2.525V     2.39V      1.525V
917ps     2.36V      2.396V     1.099V
1.197ns   1.426V     2.405V     832.2mV
1.407ns   1.156V     2.188V     814.6mV
1.778ns   1.068V     1.636V     810.5mV
2.288ns   1.058V     1.442V     810.2mV
10ns      1.058V     1.414V     810.2mV
[Falling Waveform]
R_fixture= 50.000
V_fixture= 0.0
V_fixture_min= 0.0
V_fixture_max= 0.0
|time   V(typ)   V(min)   V(max)
0s        1.521V     1.137V     1.843V
461ps     1.525V     1.138V     1.751V
558ps     1.472V     1.142V     1.331V
708ps     1.055V     1.135V     200.6mV
838ps     492.2mV    1.045V     16.46mV
917ps     182mV      915.8mV    7.52mV
997ps     50.45mV    742.3mV    3.853mV
1.288ns   4.065mV    135.7mV    356.9uV
1.528ns   936.2uV    15.99mV    49.68uV
10ns      0V         0V         0V
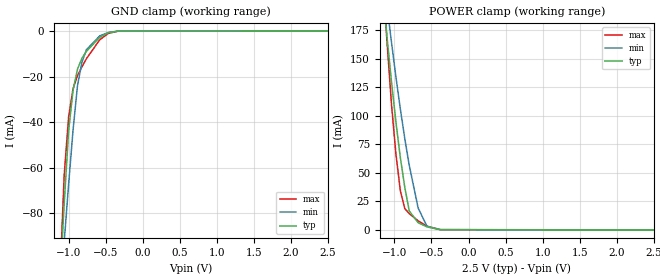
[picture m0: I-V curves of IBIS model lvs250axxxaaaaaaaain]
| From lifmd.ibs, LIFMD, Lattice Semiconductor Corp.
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|   Model lvs250axxxaaaaaaaain
[Model] lvs250axxxaaaaaaaain
Model_type Input
Polarity   Non-Inverting
Vinl =  1.150V
Vinh =  1.350V
C_comp   5.000pF   4.000pF   5.500pF
[Temperature Range]   25.000   0.125k   -40.000
[Voltage Range]   2.500V   2.380V   2.630V
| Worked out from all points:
|   GND clamp passes 1 mA (typ) near -0.48 V on its own axis
|   POWER clamp passes 1 mA (typ) near -0.47 V on its own axis
[GND_clamp]
|Voltage   I(typ)   I(min)   I(max)
-2.5V     -1.109A    -829.9mA   -1.507A
-1.12V    -111.9mA   -119.3mA   -110.4mA
-1.06V    -75.93mA   -92.62mA   -63.23mA
-1V       -43.62mA   -67.19mA   -37.57mA
-940mV    -25.94mA   -43.28mA   -25.22mA
-880mV    -16.68mA   -23.79mA   -19.51mA
-820mV    -11.88mA   -13.64mA   -15.64mA
-760mV    -8.886mA   -8.15mA    -12.13mA
-580mV    -2.744mA   -2.094mA   -3.802mA
-460mV    -700.1uA   -568.2uA   -952.3uA
-340mV    -67.24uA   -66.42uA   -79.03uA
2.5V      0A         0A         0A
[POWER_clamp]
|Voltage   I(typ)   I(min)   I(max)
-2.5V     1.335A     1.134A     2.298A
-1.16V    209.5mA    229.7mA    226.4mA
-1.1V     168.6mA    196.4mA    164.2mA
-1.04V    130mA      164.5mA    110.1mA
-980mV    94.49mA    134.1mA    66.35mA
-920mV    63.19mA    105.8mA    34.27mA
-860mV    37.12mA    79.93mA    18.71mA
-800mV    16.62mA    56.63mA    14.31mA
-680mV    6.356mA    19.13mA    7.994mA
-560mV    2.675mA    3.162mA    3.351mA
-380mV    223.3uA    309.7uA    249.8uA
2.5V      0A         0A         0A
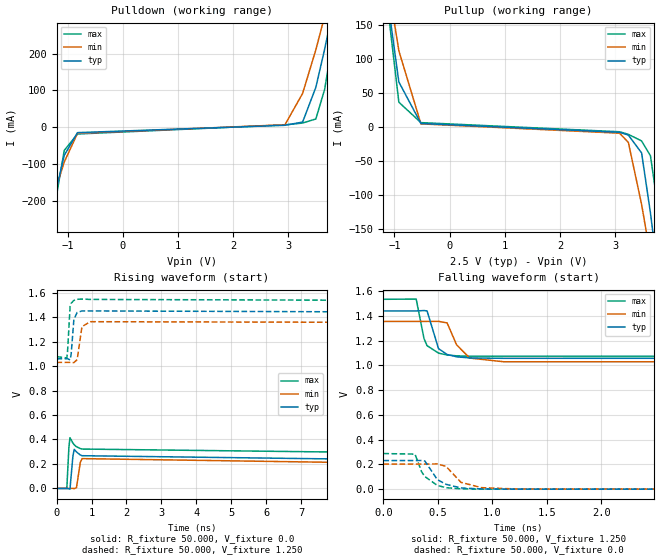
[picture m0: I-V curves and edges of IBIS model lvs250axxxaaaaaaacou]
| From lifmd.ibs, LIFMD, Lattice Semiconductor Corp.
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|   Model lvs250axxxaaaaaaacou
[Model] lvs250axxxaaaaaaacou
Model_type Output
Polarity   Non-Inverting
Vmeas =  1.250V
Cref =  3.000pF
Rref =  50.000
Vref =  1.250V
C_comp   5.000pF   4.000pF   5.500pF
[Temperature Range]   25.000   0.125k   -40.000
[Voltage Range]   2.500V   2.380V   2.630V
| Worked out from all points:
|   slope of the pulldown table from 0 to 0.375 V, typ, clamps not added: 196 ohm
|   slope of the pullup table from 0 to 0.375 V, typ, clamps not added: 199 ohm
|   rising waveform, R_fixture 50.000, V_fixture 0.0: 20-80 % time 35.3ps typ, 57.7ps min, 27.1ps max; typ from 0 V to 0.233 V
|   rising waveform, R_fixture 50.000, V_fixture 1.250: 20-80 % time 59.4ps typ, 86.9ps min, 46.5ps max; typ from 1.06 V to 1.44 V
|   falling waveform, R_fixture 50.000, V_fixture 1.250: 20-80 % time 73.1ps typ, 103ps min, 64ps max; typ from 1.44 V to 1.06 V
|   falling waveform, R_fixture 50.000, V_fixture 0.0: 20-80 % time 139ps typ, 163ps min, 122ps max; typ from 0.231 V to 0 V
[Pulldown]
|Voltage   I(typ)   I(min)   I(max)
-2.5V     -1.122A    -841.2mA   -1.521A
-1.46V    -345.9mA   -290.5mA   -432.1mA
-1.3V     -231.9mA   -209.2mA   -273.7mA
-1.06V    -76.76mA   -95.01mA   -63.36mA
-820mV    -14.96mA   -16.88mA   -18.66mA
2.94V     5.027mA    6.492mA    6.229mA
3.26V     13.76mA    91.73mA    11.15mA
3.5V      108.4mA    210.7mA    22.25mA
3.66V     212.6mA    302.7mA    103.1mA
3.74V     270mA      351.1mA    175.4mA
3.82V     329.8mA    400.7mA    261.6mA
5V        1.339A     1.23A      2.076A
[Pullup]
|Voltage   I(typ)   I(min)   I(max)
-2.5V     1.351A     1.151A     2.311A
-1.16V    217mA      238.9mA    229.9mA
-1.08V    161.4mA    194mA      147.1mA
-920mV    66.34mA    112.2mA    36.62mA
-520mV    5.395mA    4.792mA    6.657mA
3.08V     -7.586mA   -8.876mA   -6.794mA
3.24V     -11.65mA   -22.46mA   -10.6mA
3.48V     -37.91mA   -113.6mA   -20.29mA
3.64V     -125.9mA   -189mA     -42.07mA
3.72V     -178mA     -228.3mA   -86.69mA
3.88V     -288mA     -308.8mA   -227.3mA
5V        -1.114A    -898mA     -1.376A
[Ramp]
| variable   typ   min   max
dV/dt_r   0.140/36.835p   0.122/61.094p   0.174/28.645p
dV/dt_f   0.140/44.421p   0.111/67.636p   0.186/36.551p
R_load = 50.000
[Rising Waveform]
R_fixture= 50.000
V_fixture= 0.0
V_fixture_min= 0.0
V_fixture_max= 0.0
|time   V(typ)   V(min)   V(max)
0s        0V         3.063uV    0V
294ps     307.9uV    -8.124uV   -812uV
354ps     -3.547mV   11.2uV     336.3mV
384ps     -6.264mV   30.44uV    414.4mV
469ps     265.7mV    405.8uV    370.3mV
507ps     319.1mV    -2.553mV   356.3mV
571ps     297.9mV    6.883mV    340.5mV
679ps     273.4mV    211.4mV    325.9mV
729ps     267.3mV    243.5mV    321.7mV
10ns      233.1mV    204.1mV    290.3mV
[Rising Waveform]
R_fixture= 50.000
V_fixture= 1.250
V_fixture_min= 1.188
V_fixture_max= 1.313
|time   V(typ)   V(min)   V(max)
0s        1.059V     1.03V      1.077V
294ps     1.06V      1.03V      1.067V
314ps     1.06V      1.03V      1.115V
389ps     1.051V     1.03V      1.49V
419ps     1.099V     1.03V      1.514V
496ps     1.382V     1.028V     1.537V
591ps     1.439V     1.054V     1.546V
727ps     1.451V     1.323V     1.548V
966ps     1.451V     1.363V     1.545V
10ns      1.442V     1.357V     1.537V
[Falling Waveform]
R_fixture= 50.000
V_fixture= 1.250
V_fixture_min= 1.188
V_fixture_max= 1.313
|time   V(typ)   V(min)   V(max)
0s        1.441V     1.356V     1.535V
301ps     1.441V     1.356V     1.537V
373ps     1.444V     1.356V     1.217V
401ps     1.441V     1.356V     1.16V
506ps     1.136V     1.357V     1.1V
585ps     1.089V     1.344V     1.085V
672ps     1.07V      1.167V     1.078V
792ps     1.061V     1.06V      1.075V
1.105ns   1.058V     1.03V      1.075V
10ns      1.059V     1.029V     1.076V
[Falling Waveform]
R_fixture= 50.000
V_fixture= 0.0
V_fixture_min= 0.0
V_fixture_max= 0.0
|time   V(typ)   V(min)   V(max)
0s        231.3mV    203.1mV    288mV
290ps     231.3mV    203.1mV    283.2mV
351ps     231.8mV    203.1mV    140mV
380ps     228.2mV    203.1mV    102.2mV
495ps     77.12mV    203.8mV    30.35mV
575ps     39.2mV     183.9mV    11.84mV
712ps     9.761mV    55.37mV    2.501mV
901ps     1.602mV    12.08mV    274.6uV
1.241ns   20.24uV    890.6uV    -74.8uV
10ns      1.045uV    4.238uV    1.219uV
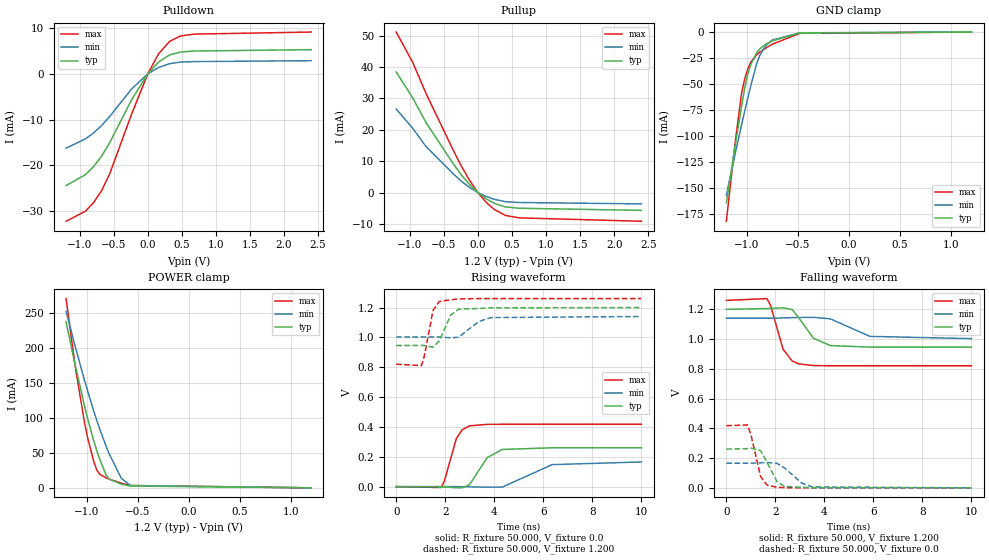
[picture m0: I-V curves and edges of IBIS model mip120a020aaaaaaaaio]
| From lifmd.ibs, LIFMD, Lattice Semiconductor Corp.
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|   Model mip120a020aaaaaaaaio
[Model] mip120a020aaaaaaaaio
Model_type I/O
Polarity   Non-Inverting
Enable   Active-Low
Vinl =  0.500V
Vinh =  0.880V
Vmeas =  0.700V
Cref =  0.0F
Rref =  1.000M
Vref =  0.0V
C_comp   5.000pF   4.000pF   5.500pF
[Temperature Range]   25.000   0.125k   -40.000
[Voltage Range]   1.200V   1.140V   1.260V
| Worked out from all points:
|   slope of the pulldown table from 0 to 0.18 V, typ, clamps not added: 63.3 ohm
|   slope of the pullup table from 0 to 0.18 V, typ, clamps not added: 65.9 ohm
|   GND clamp passes 1 mA (typ) near -0.48 V on its own axis
|   POWER clamp passes 1 mA (typ) near -0.49 V on its own axis
|   rising waveform, R_fixture 50.000, V_fixture 0.0: 20-80 % time 646ps typ, 1.04ns min, 446ps max; typ from 0 V to 0.26 V
|   rising waveform, R_fixture 50.000, V_fixture 1.200: 20-80 % time 413ps typ, 647ps min, 302ps max; typ from 0.946 V to 1.2 V
|   falling waveform, R_fixture 50.000, V_fixture 1.200: 20-80 % time 688ps typ, 991ps min, 499ps max; typ from 1.2 V to 0.946 V
|   falling waveform, R_fixture 50.000, V_fixture 0.0: 20-80 % time 470ps typ, 678ps min, 347ps max; typ from 0.26 V to 0 V
[Pulldown]
|Voltage   I(typ)   I(min)   I(max)
-1.2V     -24.43mA   -16.24mA   -32.23mA
-920mV    -22.07mA   -14.25mA   -30.06mA
-800mV    -20.33mA   -12.97mA   -28.22mA
-680mV    -18.04mA   -11.33mA   -25.58mA
-560mV    -15.08mA   -9.331mA   -21.88mA
-240mV    -5.719mA   -3.347mA   -8.876mA
0V        -2.429fA   -2.8fA     1.259fA
160mV     2.605mA    1.409mA    4.427mA
320mV     4.133mA    2.229mA    7.092mA
480mV     4.774mA    2.565mA    8.275mA
680mV     4.991mA    2.68mA     8.687mA
2.4V      5.291mA    2.878mA    9.14mA
[Pullup]
|Voltage   I(typ)   I(min)   I(max)
-1.2V     38.41mA    26.62mA    51.1mA
-960mV    30.22mA    20.53mA    41.55mA
-760mV    22.22mA    14.59mA    31.44mA
-360mV    9.102mA    5.929mA    13.38mA
-240mV    5.535mA    3.566mA    8.284mA
-120mV    2.498mA    1.585mA    3.821mA
0V        -28.4fA    28fA       56.84fA
120mV     -1.956mA   -1.223mA   -3.074mA
240mV     -3.395mA   -2.134mA   -5.356mA
400mV     -4.544mA   -2.875mA   -7.236mA
600mV     -4.976mA   -3.156mA   -8.04mA
2.4V      -5.654mA   -3.597mA   -9.127mA
[GND_clamp]
|Voltage   I(typ)   I(min)   I(max)
-1.2V     -164.5mA   -157.3mA   -182.3mA
-1.11V    -107mA     -115.7mA   -103.5mA
-1.05V    -71.11mA   -89.05mA   -58.53mA
-1.02V    -54.23mA   -76.19mA   -45.11mA
-990mV    -40.37mA   -63.68mA   -35.65mA
-960mV    -31.12mA   -51.57mA   -29.01mA
-900mV    -19.51mA   -29.36mA   -21.51mA
-870mV    -15.95mA   -21.89mA   -19.19mA
-810mV    -11.49mA   -12.65mA   -15.26mA
-750mV    -8.556mA   -7.618mA   -11.71mA
-480mV    -930.3uA   -744.4uA   -1.274mA
1.2V      0A         0A         0A
[POWER_clamp]
|Voltage   I(typ)   I(min)   I(max)
-1.2V     237mA      251.9mA    270mA
-1.11V    174.5mA    201.4mA    172.7mA
-1.02V    117mA      153.7mA    93.32mA
-990mV    99.45mA    138.6mA    72.01mA
-930mV    67.46mA    109.9mA    38.25mA
-900mV    53.33mA    96.45mA    25.43mA
-870mV    40.57mA    83.67mA    19.3mA
-810mV    18.72mA    59.99mA    14.34mA
-780mV    12.67mA    49.18mA    12.59mA
-660mV    5.246mA    13.71mA    6.607mA
-570mV    2.605mA    3.346mA    3.25mA
1.2V      0A         0A         0A
[Ramp]
| variable   typ   min   max
dV/dt_r   0.156/0.647n   99.248m/1.043n   0.251/0.450n
dV/dt_f   0.153/0.704n   82.378m/0.991n   0.264/0.502n
R_load = 50.000
[Rising Waveform]
R_fixture= 50.000
V_fixture= 0.0
V_fixture_min= 0.0
V_fixture_max= 0.0
|time   V(typ)   V(min)   V(max)
0s        0V         0V         0V
1.837ns   -2.23mV    48.3uV     -6.154mV
1.965ns   -2.627mV   125.7uV    37.58mV
2.452ns   -7.505mV   -320.4uV   321.7mV
2.682ns   -8.163mV   -1.158mV   379.5mV
2.991ns   13.39mV    -1.628mV   407.4mV
3.713ns   194.5mV    -3.763mV   417.3mV
4.322ns   248.8mV    -3.48mV    417.8mV
6.358ns   260.4mV    147.3mV    417.8mV
10ns      260.4mV    165.4mV    417.8mV
[Rising Waveform]
R_fixture= 50.000
V_fixture= 1.200
V_fixture_min= 1.140
V_fixture_max= 1.260
|time   V(typ)   V(min)   V(max)
0s        945.6mV    1.003V     820.3mV
1.028ns   946mV      1.003V     810.7mV
1.141ns   946.3mV    1.003V     870.3mV
1.502ns   934.1mV    1.003V     1.18V
1.751ns   975.8mV    1.003V     1.24V
2.221ns   1.149V     997.3mV    1.252V
2.541ns   1.189V     1.001V     1.258V
3.362ns   1.194V     1.106V     1.26V
3.863ns   1.198V     1.133V     1.26V
10ns      1.2V       1.14V      1.26V
[Falling Waveform]
R_fixture= 50.000
V_fixture= 1.200
V_fixture_min= 1.140
V_fixture_max= 1.260
|time   V(typ)   V(min)   V(max)
0s        1.2V       1.14V      1.26V
1.658ns   1.205V     1.14V      1.272V
1.799ns   1.206V     1.14V      1.228V
2.318ns   1.21V      1.142V     930.2mV
2.69ns    1.198V     1.144V     852.4mV
2.95ns    1.144V     1.145V     833.4mV
3.55ns    1.006V     1.146V     821.9mV
4.241ns   956.4mV    1.136V     820.4mV
5.86ns    945.7mV    1.018V     820.3mV
10ns      945.6mV    1.003V     820.3mV
[Falling Waveform]
R_fixture= 50.000
V_fixture= 0.0
V_fixture_min= 0.0
V_fixture_max= 0.0
|time   V(typ)   V(min)   V(max)
0s        260.4mV    165.4mV    417.8mV
859ps     263.3mV    165.1mV    422.5mV
1.008ns   266.7mV    165.5mV    354.4mV
1.399ns   249.9mV    168.2mV    75.75mV
1.658ns   172.3mV    170.6mV    18.2mV
2.061ns   43.02mV    165.4mV    4.151mV
2.37ns    9.693mV    134.8mV    1.251mV
3.071ns   3.633mV    32.52mV    82.98uV
3.51ns    1.247mV    5.817mV    14.92uV
10ns      0V         0V         0V
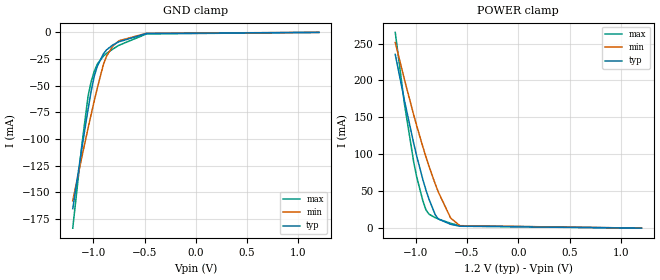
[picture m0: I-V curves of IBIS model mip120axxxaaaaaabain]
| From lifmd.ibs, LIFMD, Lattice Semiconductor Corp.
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|   Model mip120axxxaaaaaabain
[Model] mip120axxxaaaaaabain
Model_type Input
Polarity   Non-Inverting
Vinl =  0.500V
Vinh =  0.880V
C_comp   5.000pF   4.000pF   5.500pF
[Temperature Range]   25.000   0.125k   -40.000
[Voltage Range]   1.200V   1.140V   1.260V
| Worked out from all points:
|   GND clamp passes 1 mA (typ) near -0.48 V on its own axis
|   POWER clamp passes 1 mA (typ) near -0.49 V on its own axis
[GND_clamp]
|Voltage   I(typ)   I(min)   I(max)
-1.2V     -165.4mA   -157.9mA   -183.6mA
-1.11V    -107.7mA   -116.2mA   -104.5mA
-1.05V    -71.74mA   -89.52mA   -59.35mA
-1.02V    -54.82mA   -76.63mA   -45.88mA
-990mV    -40.91mA   -64.09mA   -36.36mA
-960mV    -31.62mA   -51.95mA   -29.67mA
-900mV    -19.94mA   -29.69mA   -22.08mA
-870mV    -16.35mA   -22.19mA   -19.72mA
-810mV    -11.83mA   -12.91mA   -15.71mA
-750mV    -8.853mA   -7.848mA   -12.1mA
-480mV    -1.056mA   -838.7uA   -1.452mA
1.2V      0A         0A         0A
[POWER_clamp]
|Voltage   I(typ)   I(min)   I(max)
-1.2V     235.3mA    251.4mA    265.1mA
-1.11V    172.5mA    200.9mA    167.8mA
-1.02V    114.7mA    153.3mA    89.39mA
-990mV    97.09mA    138.2mA    68.78mA
-930mV    65.21mA    109.6mA    36.59mA
-900mV    51.31mA    96.13mA    24.47mA
-870mV    38.92mA    83.34mA    18.85mA
-810mV    18.03mA    59.67mA    14.15mA
-780mV    12.34mA    48.89mA    12.44mA
-660mV    5.175mA    13.63mA    6.547mA
-570mV    2.577mA    3.308mA    3.224mA
1.2V      0A         0A         0A
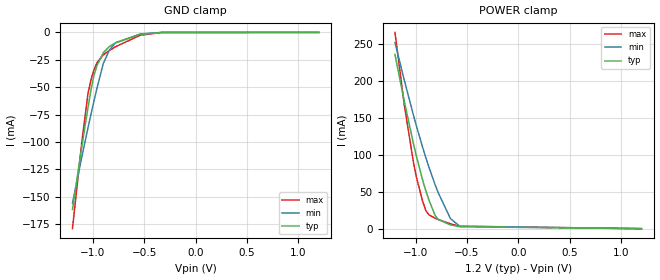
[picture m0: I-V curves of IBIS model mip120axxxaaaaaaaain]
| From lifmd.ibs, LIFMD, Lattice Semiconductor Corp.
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|   Model mip120axxxaaaaaaaain
[Model] mip120axxxaaaaaaaain
Model_type Input
Polarity   Non-Inverting
Vinl =  0.500V
Vinh =  0.880V
C_comp   5.000pF   4.000pF   5.500pF
[Temperature Range]   25.000   0.125k   -40.000
[Voltage Range]   1.200V   1.140V   1.260V
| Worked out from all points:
|   GND clamp passes 1 mA (typ) near -0.49 V on its own axis
|   POWER clamp passes 1 mA (typ) near -0.49 V on its own axis
[GND_clamp]
|Voltage   I(typ)   I(min)   I(max)
-1.2V     -161.5mA   -155.7mA   -179mA
-1.11V    -104.6mA   -114mA     -100.9mA
-1.05V    -69.18mA   -87.52mA   -56.37mA
-1.02V    -52.51mA   -74.76mA   -43.19mA
-990mV    -38.86mA   -62.37mA   -33.96mA
-960mV    -29.81mA   -50.4mA    -27.55mA
-900mV    -18.58mA   -28.48mA   -20.49mA
-840mV    -12.8mA    -15.97mA   -16.5mA
-780mV    -9.574mA   -9.378mA   -13.05mA
-540mV    -1.86mA    -1.434mA   -2.575mA
-330mV    -52.19uA   -53.03uA   -60.64uA
1.2V      0A         0A         0A
[POWER_clamp]
|Voltage   I(typ)   I(min)   I(max)
-1.2V     235.3mA    251.4mA    265.1mA
-1.11V    172.5mA    200.9mA    167.8mA
-1.02V    114.7mA    153.3mA    89.39mA
-990mV    97.09mA    138.2mA    68.78mA
-930mV    65.21mA    109.6mA    36.59mA
-900mV    51.31mA    96.13mA    24.47mA
-870mV    38.92mA    83.34mA    18.85mA
-810mV    18.03mA    59.67mA    14.15mA
-780mV    12.34mA    48.89mA    12.44mA
-660mV    5.175mA    13.63mA    6.547mA
-570mV    2.577mA    3.308mA    3.224mA
1.2V      0A         0A         0A
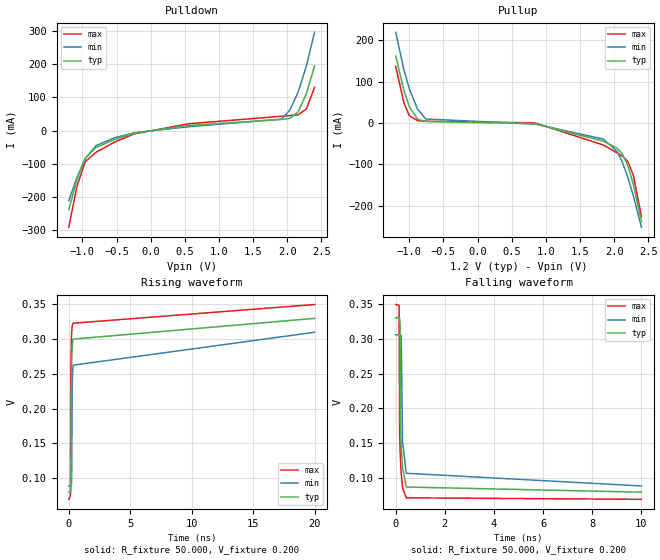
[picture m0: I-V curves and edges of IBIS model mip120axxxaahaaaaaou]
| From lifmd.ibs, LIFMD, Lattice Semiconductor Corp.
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|   Model mip120axxxaahaaaaaou
[Model] mip120axxxaahaaaaaou
Model_type Output
Polarity   Non-Inverting
Vmeas =  0.200V
Cref =  0.0F
Rref =  1.000M
Vref =  0.0V
C_comp   5.000pF   4.000pF   5.500pF
[Temperature Range]   25.000   0.125k   -40.000
[Voltage Range]   1.200V   1.140V   1.260V
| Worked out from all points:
|   slope of the pulldown table from 0 to 0.18 V, typ, clamps not added: 33.6 ohm
|   slope of the pullup table from 0 to 0.18 V, typ, clamps not added: 13.1 kohm
|   rising waveform, R_fixture 50.000, V_fixture 0.200: 20-80 % time 71.4ps typ, 103ps min, 56ps max; typ from 0.08 V to 0.33 V
|   falling waveform, R_fixture 50.000, V_fixture 0.200: 20-80 % time 64ps typ, 79.5ps min, 50.9ps max; typ from 0.33 V to 0.08 V
[Pulldown]
|Voltage   I(typ)   I(min)   I(max)
-1.2V     -237.8mA   -211.1mA   -290.5mA
-1.08V    -146.8mA   -140.2mA   -167.3mA
-960mV    -83.33mA   -84.82mA   -93.67mA
-800mV    -50.58mA   -45.13mA   -64.92mA
-520mV    -25.87mA   -21.03mA   -33.62mA
-240mV    -7.736mA   -6.347mA   -10.05mA
560mV     15.39mA    11.56mA    20.59mA
1.92V     33.54mA    34.42mA    43.11mA
2.04V     36.77mA    62.55mA    45.05mA
2.16V     56.92mA    115.9mA    47.41mA
2.28V     110.8mA    194.7mA    65.2mA
2.4V      194.4mA    295.4mA    129.9mA
[Pullup]
|Voltage   I(typ)   I(min)   I(max)
-1.2V     161.8mA    218.9mA    136.7mA
-1.08V    78.74mA    129.1mA    49.09mA
-1V       39.26mA    82.19mA    17.57mA
-880mV    9.155mA    33.6mA     5.7mA
-760mV    3.599mA    9.676mA    4.267mA
840mV     -1.641mA   -2.449mA   288.3uA
1.84V     -43.63mA   -38.74mA   -52.98mA
2.04V     -60.44mA   -67.81mA   -71.76mA
2.12V     -74.32mA   -94.23mA   -79.81mA
2.2V      -102.5mA   -130.8mA   -92.85mA
2.28V     -147.7mA   -175.2mA   -125.3mA
2.4V      -237.3mA   -251.4mA   -225.5mA
[Ramp]
| variable   typ   min   max
dV/dt_r   0.152/36.775p   0.132/32.538p   0.171/38.346p
dV/dt_f   0.403/68.397p   0.334/82.893p   0.473/55.901p
R_load = 50.000
[Rising Waveform]
R_fixture= 50.000
V_fixture= 0.200
V_fixture_min= 0.190
V_fixture_max= 0.210
|time   V(typ)   V(min)   V(max)
0s        79.53mV    88.44mV    69.23mV
128ps     79.53mV    88.44mV    74.07mV
144ps     79.55mV    88.44mV    123.7mV
157ps     79.08mV    88.44mV    233.7mV
164ps     81.57mV    88.44mV    254.7mV
219ps     255.9mV    89.32mV    304mV
241ps     272.3mV    113.6mV    312mV
277ps     287.8mV    231.3mV    319.2mV
337ps     300.1mV    262.5mV    323mV
20ns      330mV      310mV      350mV
[Falling Waveform]
R_fixture= 50.000
V_fixture= 0.200
V_fixture_min= 0.190
V_fixture_max= 0.210
|time   V(typ)   V(min)   V(max)
0s        330.1mV    305.6mV    349.2mV
135ps     330.1mV    305.6mV    348.2mV
141ps     330.1mV    305.6mV    334.2mV
160ps     330.1mV    305.6mV    166.4mV
177ps     320.6mV    305.6mV    142.6mV
199ps     178.2mV    305.6mV    123.1mV
226ps     143.4mV    304.3mV    105.3mV
279ps     115.2mV    152.9mV    86.28mV
429ps     86.92mV    106.7mV    71.39mV
10ns      79.53mV    88.44mV    69.23mV
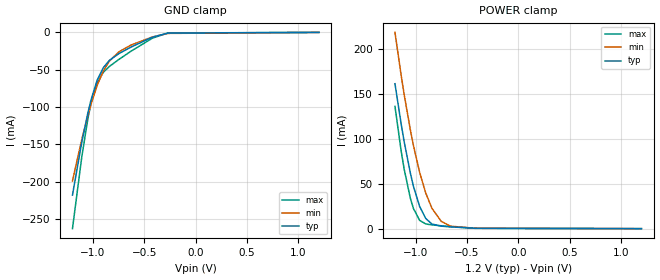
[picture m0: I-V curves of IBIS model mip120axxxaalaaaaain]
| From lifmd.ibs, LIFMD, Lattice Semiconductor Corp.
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|   Model mip120axxxaalaaaaain
[Model] mip120axxxaalaaaaain
Model_type Input
Polarity   Non-Inverting
Vinl =  0.0V
Vinh =  1.200V
C_comp   5.000pF   4.000pF   5.500pF
[Temperature Range]   25.000   0.125k   -40.000
[Voltage Range]   1.200V   1.140V   1.260V
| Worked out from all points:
|   GND clamp passes 1 mA (typ) near -0.27 V on its own axis
|   POWER clamp passes 1 mA (typ) near -0.52 V on its own axis
[GND_clamp]
|Voltage   I(typ)   I(min)   I(max)
-1.2V     -217.9mA   -199mA     -262.9mA
-1.11V    -147.6mA   -143.8mA   -167.4mA
-1.05V    -107.8mA   -111.1mA   -115.7mA
-1.02V    -90.79mA   -96.46mA   -95.34mA
-960mV    -64.12mA   -71.13mA   -67.62mA
-900mV    -47.28mA   -51.8mA    -53.55mA
-840mV    -37.47mA   -38.36mA   -45.55mA
-750mV    -28.59mA   -26.19mA   -36.4mA
-630mV    -19.65mA   -16.92mA   -25.19mA
-420mV    -6.348mA   -6.021mA   -7.605mA
-270mV    -917.3uA   -1.322mA   -797.8uA
1.2V      0A         0A         0A
[POWER_clamp]
|Voltage   I(typ)   I(min)   I(max)
-1.2V     161.2mA    218.3mA    136mA
-1.14V    116.6mA    170.7mA    86.54mA
-1.11V    96.51mA    148.9mA    65.91mA
-1.05V    61.64mA    109.7mA    33.67mA
-1.02V    47.09mA    92.4mA     22.42mA
-960mV    24.75mA    62.63mA    9.252mA
-900mV    11.25mA    39.43mA    5.21mA
-840mV    5.142mA    22.64mA    4.17mA
-750mV    2.79mA     8.127mA    3.21mA
-660mV    1.982mA    2.729mA    2.323mA
-420mV    414.8uA    474.9uA    400.7uA
1.2V      0A         0A         0A
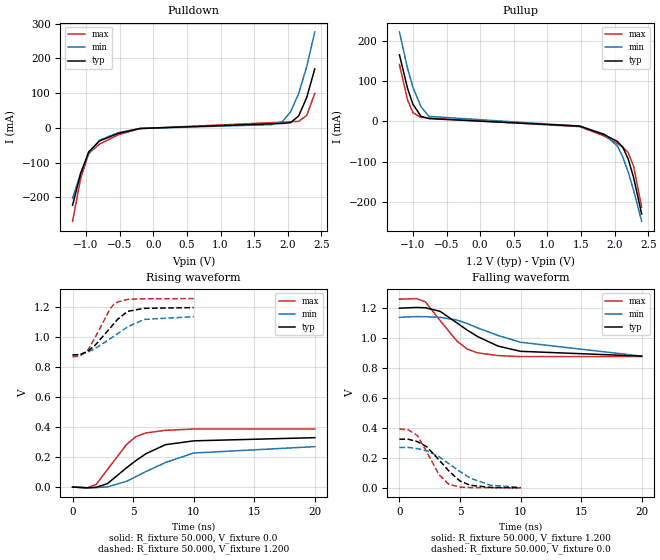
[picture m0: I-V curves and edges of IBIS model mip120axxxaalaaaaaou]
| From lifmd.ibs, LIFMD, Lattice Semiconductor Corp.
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|   Model mip120axxxaalaaaaaou
[Model] mip120axxxaalaaaaaou
Model_type Output
Polarity   Non-Inverting
Vmeas =  0.600V
Cref =  0.0F
Rref =  1.000M
Vref =  0.0V
C_comp   5.000pF   4.000pF   5.500pF
[Temperature Range]   25.000   0.125k   -40.000
[Voltage Range]   1.200V   1.140V   1.260V
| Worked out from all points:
|   slope of the pulldown table from 0 to 0.18 V, typ, clamps not added: 134 ohm
|   slope of the pullup table from 0 to 0.18 V, typ, clamps not added: 132 ohm
|   rising waveform, R_fixture 50.000, V_fixture 0.0: 20-80 % time 3.45ns typ, 4.56ns min, 2.22ns max; typ from 0 V to 0.33 V
|   rising waveform, R_fixture 50.000, V_fixture 1.200: 20-80 % time 2.06ns typ, 2.83ns min, 1.5ns max; typ from 0.882 V to 1.2 V
|   falling waveform, R_fixture 50.000, V_fixture 1.200: 20-80 % time 4.06ns typ, 8.5ns min, 2.33ns max; typ from 1.2 V to 0.88 V
|   falling waveform, R_fixture 50.000, V_fixture 0.0: 20-80 % time 2.23ns typ, 2.92ns min, 1.57ns max; typ from 0.326 V to 0.001 V
[Pulldown]
|Voltage   I(typ)   I(min)   I(max)
-1.2V     -222.5mA   -202.4mA   -268.6mA
-1.08V    -131.4mA   -130.3mA   -145.6mA
-960mV    -68.67mA   -74.55mA   -73.21mA
-800mV    -37.46mA   -35.47mA   -46.75mA
-520mV    -15.77mA   -13.6mA    -19.76mA
-200mV    -1.664mA   -1.627mA   -1.933mA
1.76V     11.97mA    9.46mA     15.2mA
1.92V     12.97mA    18.76mA    16.63mA
2.04V     15.25mA    45.98mA    17.67mA
2.16V     34.37mA    98.4mA     19.05mA
2.28V     87.21mA    176.2mA    35.75mA
2.4V      169.6mA    275.9mA    99.26mA
[Pullup]
|Voltage   I(typ)   I(min)   I(max)
-1.2V     165.2mA    221.7mA    141mA
-1.08V    82.09mA    131.8mA    53.28mA
-1V       42.55mA    84.83mA    21.67mA
-880mV    12.33mA    36.16mA    9.645mA
-760mV    6.631mA    12.13mA    8.02mA
1.48V     -11.94mA   -12.04mA   -13.37mA
1.84V     -32.9mA    -31.86mA   -36.23mA
2.04V     -50.2mA    -61.83mA   -55.33mA
2.12V     -64.62mA   -88.88mA   -63.92mA
2.2V      -93.42mA   -126.1mA   -77.78mA
2.28V     -139.4mA   -171.2mA   -111.2mA
2.4V      -230.3mA   -248.4mA   -213.1mA
[Ramp]
| variable   typ   min   max
dV/dt_r   0.195/3.396n   0.162/3.560n   0.233/2.224n
dV/dt_f   0.191/3.360n   0.153/3.273n   0.230/2.331n
R_load = 50.000
[Rising Waveform]
R_fixture= 50.000
V_fixture= 0.0
V_fixture_min= 0.0
V_fixture_max= 0.0
|time   V(typ)   V(min)   V(max)
0s        10uV       67.98uV    3.271uV
1.198ns   -5.232mV   -4.626mV   -4.962mV
1.948ns   -1.79mV    -3.551mV   17.24mV
2.881ns   22.9mV     1.177mV    117.2mV
4.468ns   129.4mV    38.5mV     285.4mV
5.238ns   177.1mV    70.32mV    337mV
6.041ns   221.8mV    102.9mV    361.3mV
7.66ns    282.8mV    163.6mV    379.1mV
10ns      308.7mV    227.2mV    387.5mV
20ns      330mV      270mV      387.5mV
[Rising Waveform]
R_fixture= 50.000
V_fixture= 1.200
V_fixture_min= 1.140
V_fixture_max= 1.260
|time   V(typ)   V(min)   V(max)
0s        882.4mV    883.8mV    870.7mV
597ps     884.5mV    885.4mV    874.4mV
1.248ns   906.7mV    901.5mV    912.7mV
1.871ns   948.2mV    925.6mV    1V
3.087ns   1.061V     989.8mV    1.189V
3.408ns   1.091V     1.008V     1.221V
3.738ns   1.122V     1.026V     1.237V
4.55ns    1.174V     1.07V      1.254V
5.903ns   1.194V     1.12V      1.258V
10ns      1.199V     1.138V     1.259V
[Falling Waveform]
R_fixture= 50.000
V_fixture= 1.200
V_fixture_min= 1.140
V_fixture_max= 1.260
|time   V(typ)   V(min)   V(max)
0s        1.2V       1.139V     1.26V
1.401ns   1.205V     1.144V     1.264V
2.135ns   1.203V     1.143V     1.243V
3.356ns   1.179V     1.139V     1.118V
4.743ns   1.102V     1.121V     981mV
5.591ns   1.054V     1.098V     927.6mV
6.442ns   1.011V     1.069V     902mV
8.14ns    946.9mV    1.018V     883.7mV
10ns      912.1mV    972.5mV    876.7mV
20ns      880mV      880mV      876.7mV
[Falling Waveform]
R_fixture= 50.000
V_fixture= 0.0
V_fixture_min= 0.0
V_fixture_max= 0.0
|time   V(typ)   V(min)   V(max)
0s        325.6mV    269.6mV    393.1mV
736ps     324.8mV    270.6mV    388mV
1.485ns   309.2mV    261.9mV    349.4mV
2.266ns   274mV      247.5mV    239.5mV
3.261ns   187.7mV    209.6mV    89.31mV
4.091ns   112.3mV    161.2mV    23.39mV
4.975ns   47.23mV    110.5mV    5.617mV
5.845ns   17.93mV    65.94mV    2.32mV
7.505ns   3.304mV    18.09mV    1.233mV
10ns      1.201mV    3.306mV    534uV
